VERSION 5.8 ;
BUSBITCHARS "[]" ;
DIVIDERCHAR "/" ;
UNITS
    DATABASE MICRONS 1000 ;
END UNITS

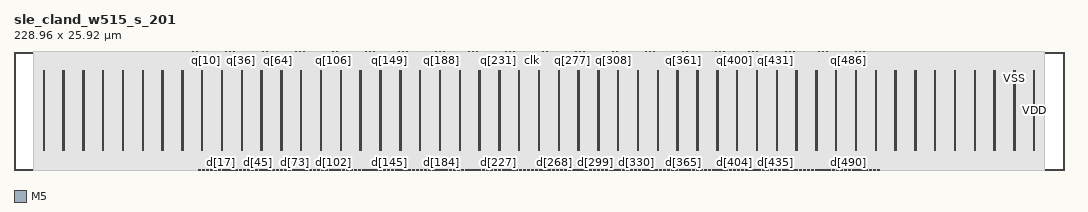
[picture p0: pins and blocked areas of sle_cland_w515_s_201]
MACRO sle_cland_w515_s_201
  FOREIGN sle_cland_w515_s_201 0 0 ;
  CLASS BLOCK ;
  SIZE 228.96 BY 25.92 ;
  PIN clk
    DIRECTION INPUT ;
    USE SIGNAL ;
    PORT
      LAYER M5 ;
        RECT  113.04 25.836 113.064 25.92 ;
    END
  END clk
  PIN d[0]
    DIRECTION INPUT ;
    USE SIGNAL ;
    PORT
      LAYER M5 ;
        RECT  40.176 0 40.2 0.084 ;
    END
  END d[0]
  PIN d[100]
    DIRECTION INPUT ;
    USE SIGNAL ;
    PORT
      LAYER M5 ;
        RECT  68.976 0 69 0.084 ;
    END
  END d[100]
  PIN d[101]
    DIRECTION INPUT ;
    USE SIGNAL ;
    PORT
      LAYER M5 ;
        RECT  69.264 0 69.288 0.084 ;
    END
  END d[101]
  PIN d[102]
    DIRECTION INPUT ;
    USE SIGNAL ;
    PORT
      LAYER M5 ;
        RECT  69.552 0 69.576 0.084 ;
    END
  END d[102]
  PIN d[103]
    DIRECTION INPUT ;
    USE SIGNAL ;
    PORT
      LAYER M5 ;
        RECT  69.84 0 69.864 0.084 ;
    END
  END d[103]
  PIN d[104]
    DIRECTION INPUT ;
    USE SIGNAL ;
    PORT
      LAYER M5 ;
        RECT  70.128 0 70.152 0.084 ;
    END
  END d[104]
  PIN d[105]
    DIRECTION INPUT ;
    USE SIGNAL ;
    PORT
      LAYER M5 ;
        RECT  70.416 0 70.44 0.084 ;
    END
  END d[105]
  PIN d[106]
    DIRECTION INPUT ;
    USE SIGNAL ;
    PORT
      LAYER M5 ;
        RECT  70.704 0 70.728 0.084 ;
    END
  END d[106]
  PIN d[107]
    DIRECTION INPUT ;
    USE SIGNAL ;
    PORT
      LAYER M5 ;
        RECT  70.992 0 71.016 0.084 ;
    END
  END d[107]
  PIN d[108]
    DIRECTION INPUT ;
    USE SIGNAL ;
    PORT
      LAYER M5 ;
        RECT  71.28 0 71.304 0.084 ;
    END
  END d[108]
  PIN d[109]
    DIRECTION INPUT ;
    USE SIGNAL ;
    PORT
      LAYER M5 ;
        RECT  71.568 0 71.592 0.084 ;
    END
  END d[109]
  PIN d[10]
    DIRECTION INPUT ;
    USE SIGNAL ;
    PORT
      LAYER M5 ;
        RECT  43.056 0 43.08 0.084 ;
    END
  END d[10]
  PIN d[110]
    DIRECTION INPUT ;
    USE SIGNAL ;
    PORT
      LAYER M5 ;
        RECT  71.856 0 71.88 0.084 ;
    END
  END d[110]
  PIN d[111]
    DIRECTION INPUT ;
    USE SIGNAL ;
    PORT
      LAYER M5 ;
        RECT  72.144 0 72.168 0.084 ;
    END
  END d[111]
  PIN d[112]
    DIRECTION INPUT ;
    USE SIGNAL ;
    PORT
      LAYER M5 ;
        RECT  72.432 0 72.456 0.084 ;
    END
  END d[112]
  PIN d[113]
    DIRECTION INPUT ;
    USE SIGNAL ;
    PORT
      LAYER M5 ;
        RECT  72.72 0 72.744 0.084 ;
    END
  END d[113]
  PIN d[114]
    DIRECTION INPUT ;
    USE SIGNAL ;
    PORT
      LAYER M5 ;
        RECT  73.008 0 73.032 0.084 ;
    END
  END d[114]
  PIN d[115]
    DIRECTION INPUT ;
    USE SIGNAL ;
    PORT
      LAYER M5 ;
        RECT  73.296 0 73.32 0.084 ;
    END
  END d[115]
  PIN d[116]
    DIRECTION INPUT ;
    USE SIGNAL ;
    PORT
      LAYER M5 ;
        RECT  73.584 0 73.608 0.084 ;
    END
  END d[116]
  PIN d[117]
    DIRECTION INPUT ;
    USE SIGNAL ;
    PORT
      LAYER M5 ;
        RECT  73.872 0 73.896 0.084 ;
    END
  END d[117]
  PIN d[118]
    DIRECTION INPUT ;
    USE SIGNAL ;
    PORT
      LAYER M5 ;
        RECT  74.16 0 74.184 0.084 ;
    END
  END d[118]
  PIN d[119]
    DIRECTION INPUT ;
    USE SIGNAL ;
    PORT
      LAYER M5 ;
        RECT  74.448 0 74.472 0.084 ;
    END
  END d[119]
  PIN d[11]
    DIRECTION INPUT ;
    USE SIGNAL ;
    PORT
      LAYER M5 ;
        RECT  43.344 0 43.368 0.084 ;
    END
  END d[11]
  PIN d[120]
    DIRECTION INPUT ;
    USE SIGNAL ;
    PORT
      LAYER M5 ;
        RECT  74.736 0 74.76 0.084 ;
    END
  END d[120]
  PIN d[121]
    DIRECTION INPUT ;
    USE SIGNAL ;
    PORT
      LAYER M5 ;
        RECT  75.024 0 75.048 0.084 ;
    END
  END d[121]
  PIN d[122]
    DIRECTION INPUT ;
    USE SIGNAL ;
    PORT
      LAYER M5 ;
        RECT  75.312 0 75.336 0.084 ;
    END
  END d[122]
  PIN d[123]
    DIRECTION INPUT ;
    USE SIGNAL ;
    PORT
      LAYER M5 ;
        RECT  75.6 0 75.624 0.084 ;
    END
  END d[123]
  PIN d[124]
    DIRECTION INPUT ;
    USE SIGNAL ;
    PORT
      LAYER M5 ;
        RECT  75.888 0 75.912 0.084 ;
    END
  END d[124]
  PIN d[125]
    DIRECTION INPUT ;
    USE SIGNAL ;
    PORT
      LAYER M5 ;
        RECT  76.176 0 76.2 0.084 ;
    END
  END d[125]
  PIN d[126]
    DIRECTION INPUT ;
    USE SIGNAL ;
    PORT
      LAYER M5 ;
        RECT  76.464 0 76.488 0.084 ;
    END
  END d[126]
  PIN d[127]
    DIRECTION INPUT ;
    USE SIGNAL ;
    PORT
      LAYER M5 ;
        RECT  76.752 0 76.776 0.084 ;
    END
  END d[127]
  PIN d[128]
    DIRECTION INPUT ;
    USE SIGNAL ;
    PORT
      LAYER M5 ;
        RECT  77.04 0 77.064 0.084 ;
    END
  END d[128]
  PIN d[129]
    DIRECTION INPUT ;
    USE SIGNAL ;
    PORT
      LAYER M5 ;
        RECT  77.328 0 77.352 0.084 ;
    END
  END d[129]
  PIN d[12]
    DIRECTION INPUT ;
    USE SIGNAL ;
    PORT
      LAYER M5 ;
        RECT  43.632 0 43.656 0.084 ;
    END
  END d[12]
  PIN d[130]
    DIRECTION INPUT ;
    USE SIGNAL ;
    PORT
      LAYER M5 ;
        RECT  77.616 0 77.64 0.084 ;
    END
  END d[130]
  PIN d[131]
    DIRECTION INPUT ;
    USE SIGNAL ;
    PORT
      LAYER M5 ;
        RECT  77.904 0 77.928 0.084 ;
    END
  END d[131]
  PIN d[132]
    DIRECTION INPUT ;
    USE SIGNAL ;
    PORT
      LAYER M5 ;
        RECT  78.192 0 78.216 0.084 ;
    END
  END d[132]
  PIN d[133]
    DIRECTION INPUT ;
    USE SIGNAL ;
    PORT
      LAYER M5 ;
        RECT  78.48 0 78.504 0.084 ;
    END
  END d[133]
  PIN d[134]
    DIRECTION INPUT ;
    USE SIGNAL ;
    PORT
      LAYER M5 ;
        RECT  78.768 0 78.792 0.084 ;
    END
  END d[134]
  PIN d[135]
    DIRECTION INPUT ;
    USE SIGNAL ;
    PORT
      LAYER M5 ;
        RECT  79.056 0 79.08 0.084 ;
    END
  END d[135]
  PIN d[136]
    DIRECTION INPUT ;
    USE SIGNAL ;
    PORT
      LAYER M5 ;
        RECT  79.344 0 79.368 0.084 ;
    END
  END d[136]
  PIN d[137]
    DIRECTION INPUT ;
    USE SIGNAL ;
    PORT
      LAYER M5 ;
        RECT  79.632 0 79.656 0.084 ;
    END
  END d[137]
  PIN d[138]
    DIRECTION INPUT ;
    USE SIGNAL ;
    PORT
      LAYER M5 ;
        RECT  79.92 0 79.944 0.084 ;
    END
  END d[138]
  PIN d[139]
    DIRECTION INPUT ;
    USE SIGNAL ;
    PORT
      LAYER M5 ;
        RECT  80.208 0 80.232 0.084 ;
    END
  END d[139]
  PIN d[13]
    DIRECTION INPUT ;
    USE SIGNAL ;
    PORT
      LAYER M5 ;
        RECT  43.92 0 43.944 0.084 ;
    END
  END d[13]
  PIN d[140]
    DIRECTION INPUT ;
    USE SIGNAL ;
    PORT
      LAYER M5 ;
        RECT  80.496 0 80.52 0.084 ;
    END
  END d[140]
  PIN d[141]
    DIRECTION INPUT ;
    USE SIGNAL ;
    PORT
      LAYER M5 ;
        RECT  80.784 0 80.808 0.084 ;
    END
  END d[141]
  PIN d[142]
    DIRECTION INPUT ;
    USE SIGNAL ;
    PORT
      LAYER M5 ;
        RECT  81.072 0 81.096 0.084 ;
    END
  END d[142]
  PIN d[143]
    DIRECTION INPUT ;
    USE SIGNAL ;
    PORT
      LAYER M5 ;
        RECT  81.36 0 81.384 0.084 ;
    END
  END d[143]
  PIN d[144]
    DIRECTION INPUT ;
    USE SIGNAL ;
    PORT
      LAYER M5 ;
        RECT  81.648 0 81.672 0.084 ;
    END
  END d[144]
  PIN d[145]
    DIRECTION INPUT ;
    USE SIGNAL ;
    PORT
      LAYER M5 ;
        RECT  81.936 0 81.96 0.084 ;
    END
  END d[145]
  PIN d[146]
    DIRECTION INPUT ;
    USE SIGNAL ;
    PORT
      LAYER M5 ;
        RECT  82.224 0 82.248 0.084 ;
    END
  END d[146]
  PIN d[147]
    DIRECTION INPUT ;
    USE SIGNAL ;
    PORT
      LAYER M5 ;
        RECT  82.512 0 82.536 0.084 ;
    END
  END d[147]
  PIN d[148]
    DIRECTION INPUT ;
    USE SIGNAL ;
    PORT
      LAYER M5 ;
        RECT  82.8 0 82.824 0.084 ;
    END
  END d[148]
  PIN d[149]
    DIRECTION INPUT ;
    USE SIGNAL ;
    PORT
      LAYER M5 ;
        RECT  83.088 0 83.112 0.084 ;
    END
  END d[149]
  PIN d[14]
    DIRECTION INPUT ;
    USE SIGNAL ;
    PORT
      LAYER M5 ;
        RECT  44.208 0 44.232 0.084 ;
    END
  END d[14]
  PIN d[150]
    DIRECTION INPUT ;
    USE SIGNAL ;
    PORT
      LAYER M5 ;
        RECT  83.376 0 83.4 0.084 ;
    END
  END d[150]
  PIN d[151]
    DIRECTION INPUT ;
    USE SIGNAL ;
    PORT
      LAYER M5 ;
        RECT  83.664 0 83.688 0.084 ;
    END
  END d[151]
  PIN d[152]
    DIRECTION INPUT ;
    USE SIGNAL ;
    PORT
      LAYER M5 ;
        RECT  83.952 0 83.976 0.084 ;
    END
  END d[152]
  PIN d[153]
    DIRECTION INPUT ;
    USE SIGNAL ;
    PORT
      LAYER M5 ;
        RECT  84.24 0 84.264 0.084 ;
    END
  END d[153]
  PIN d[154]
    DIRECTION INPUT ;
    USE SIGNAL ;
    PORT
      LAYER M5 ;
        RECT  84.528 0 84.552 0.084 ;
    END
  END d[154]
  PIN d[155]
    DIRECTION INPUT ;
    USE SIGNAL ;
    PORT
      LAYER M5 ;
        RECT  84.816 0 84.84 0.084 ;
    END
  END d[155]
  PIN d[156]
    DIRECTION INPUT ;
    USE SIGNAL ;
    PORT
      LAYER M5 ;
        RECT  85.104 0 85.128 0.084 ;
    END
  END d[156]
  PIN d[157]
    DIRECTION INPUT ;
    USE SIGNAL ;
    PORT
      LAYER M5 ;
        RECT  85.392 0 85.416 0.084 ;
    END
  END d[157]
  PIN d[158]
    DIRECTION INPUT ;
    USE SIGNAL ;
    PORT
      LAYER M5 ;
        RECT  85.68 0 85.704 0.084 ;
    END
  END d[158]
  PIN d[159]
    DIRECTION INPUT ;
    USE SIGNAL ;
    PORT
      LAYER M5 ;
        RECT  85.968 0 85.992 0.084 ;
    END
  END d[159]
  PIN d[15]
    DIRECTION INPUT ;
    USE SIGNAL ;
    PORT
      LAYER M5 ;
        RECT  44.496 0 44.52 0.084 ;
    END
  END d[15]
  PIN d[160]
    DIRECTION INPUT ;
    USE SIGNAL ;
    PORT
      LAYER M5 ;
        RECT  86.256 0 86.28 0.084 ;
    END
  END d[160]
  PIN d[161]
    DIRECTION INPUT ;
    USE SIGNAL ;
    PORT
      LAYER M5 ;
        RECT  86.544 0 86.568 0.084 ;
    END
  END d[161]
  PIN d[162]
    DIRECTION INPUT ;
    USE SIGNAL ;
    PORT
      LAYER M5 ;
        RECT  86.832 0 86.856 0.084 ;
    END
  END d[162]
  PIN d[163]
    DIRECTION INPUT ;
    USE SIGNAL ;
    PORT
      LAYER M5 ;
        RECT  87.12 0 87.144 0.084 ;
    END
  END d[163]
  PIN d[164]
    DIRECTION INPUT ;
    USE SIGNAL ;
    PORT
      LAYER M5 ;
        RECT  87.408 0 87.432 0.084 ;
    END
  END d[164]
  PIN d[165]
    DIRECTION INPUT ;
    USE SIGNAL ;
    PORT
      LAYER M5 ;
        RECT  87.696 0 87.72 0.084 ;
    END
  END d[165]
  PIN d[166]
    DIRECTION INPUT ;
    USE SIGNAL ;
    PORT
      LAYER M5 ;
        RECT  87.984 0 88.008 0.084 ;
    END
  END d[166]
  PIN d[167]
    DIRECTION INPUT ;
    USE SIGNAL ;
    PORT
      LAYER M5 ;
        RECT  88.272 0 88.296 0.084 ;
    END
  END d[167]
  PIN d[168]
    DIRECTION INPUT ;
    USE SIGNAL ;
    PORT
      LAYER M5 ;
        RECT  88.56 0 88.584 0.084 ;
    END
  END d[168]
  PIN d[169]
    DIRECTION INPUT ;
    USE SIGNAL ;
    PORT
      LAYER M5 ;
        RECT  88.848 0 88.872 0.084 ;
    END
  END d[169]
  PIN d[16]
    DIRECTION INPUT ;
    USE SIGNAL ;
    PORT
      LAYER M5 ;
        RECT  44.784 0 44.808 0.084 ;
    END
  END d[16]
  PIN d[170]
    DIRECTION INPUT ;
    USE SIGNAL ;
    PORT
      LAYER M5 ;
        RECT  89.136 0 89.16 0.084 ;
    END
  END d[170]
  PIN d[171]
    DIRECTION INPUT ;
    USE SIGNAL ;
    PORT
      LAYER M5 ;
        RECT  89.424 0 89.448 0.084 ;
    END
  END d[171]
  PIN d[172]
    DIRECTION INPUT ;
    USE SIGNAL ;
    PORT
      LAYER M5 ;
        RECT  89.712 0 89.736 0.084 ;
    END
  END d[172]
  PIN d[173]
    DIRECTION INPUT ;
    USE SIGNAL ;
    PORT
      LAYER M5 ;
        RECT  90 0 90.024 0.084 ;
    END
  END d[173]
  PIN d[174]
    DIRECTION INPUT ;
    USE SIGNAL ;
    PORT
      LAYER M5 ;
        RECT  90.288 0 90.312 0.084 ;
    END
  END d[174]
  PIN d[175]
    DIRECTION INPUT ;
    USE SIGNAL ;
    PORT
      LAYER M5 ;
        RECT  90.576 0 90.6 0.084 ;
    END
  END d[175]
  PIN d[176]
    DIRECTION INPUT ;
    USE SIGNAL ;
    PORT
      LAYER M5 ;
        RECT  90.864 0 90.888 0.084 ;
    END
  END d[176]
  PIN d[177]
    DIRECTION INPUT ;
    USE SIGNAL ;
    PORT
      LAYER M5 ;
        RECT  91.152 0 91.176 0.084 ;
    END
  END d[177]
  PIN d[178]
    DIRECTION INPUT ;
    USE SIGNAL ;
    PORT
      LAYER M5 ;
        RECT  91.44 0 91.464 0.084 ;
    END
  END d[178]
  PIN d[179]
    DIRECTION INPUT ;
    USE SIGNAL ;
    PORT
      LAYER M5 ;
        RECT  91.728 0 91.752 0.084 ;
    END
  END d[179]
  PIN d[17]
    DIRECTION INPUT ;
    USE SIGNAL ;
    PORT
      LAYER M5 ;
        RECT  45.072 0 45.096 0.084 ;
    END
  END d[17]
  PIN d[180]
    DIRECTION INPUT ;
    USE SIGNAL ;
    PORT
      LAYER M5 ;
        RECT  92.016 0 92.04 0.084 ;
    END
  END d[180]
  PIN d[181]
    DIRECTION INPUT ;
    USE SIGNAL ;
    PORT
      LAYER M5 ;
        RECT  92.304 0 92.328 0.084 ;
    END
  END d[181]
  PIN d[182]
    DIRECTION INPUT ;
    USE SIGNAL ;
    PORT
      LAYER M5 ;
        RECT  92.592 0 92.616 0.084 ;
    END
  END d[182]
  PIN d[183]
    DIRECTION INPUT ;
    USE SIGNAL ;
    PORT
      LAYER M5 ;
        RECT  92.88 0 92.904 0.084 ;
    END
  END d[183]
  PIN d[184]
    DIRECTION INPUT ;
    USE SIGNAL ;
    PORT
      LAYER M5 ;
        RECT  93.168 0 93.192 0.084 ;
    END
  END d[184]
  PIN d[185]
    DIRECTION INPUT ;
    USE SIGNAL ;
    PORT
      LAYER M5 ;
        RECT  93.456 0 93.48 0.084 ;
    END
  END d[185]
  PIN d[186]
    DIRECTION INPUT ;
    USE SIGNAL ;
    PORT
      LAYER M5 ;
        RECT  93.744 0 93.768 0.084 ;
    END
  END d[186]
  PIN d[187]
    DIRECTION INPUT ;
    USE SIGNAL ;
    PORT
      LAYER M5 ;
        RECT  94.032 0 94.056 0.084 ;
    END
  END d[187]
  PIN d[188]
    DIRECTION INPUT ;
    USE SIGNAL ;
    PORT
      LAYER M5 ;
        RECT  94.32 0 94.344 0.084 ;
    END
  END d[188]
  PIN d[189]
    DIRECTION INPUT ;
    USE SIGNAL ;
    PORT
      LAYER M5 ;
        RECT  94.608 0 94.632 0.084 ;
    END
  END d[189]
  PIN d[18]
    DIRECTION INPUT ;
    USE SIGNAL ;
    PORT
      LAYER M5 ;
        RECT  45.36 0 45.384 0.084 ;
    END
  END d[18]
  PIN d[190]
    DIRECTION INPUT ;
    USE SIGNAL ;
    PORT
      LAYER M5 ;
        RECT  94.896 0 94.92 0.084 ;
    END
  END d[190]
  PIN d[191]
    DIRECTION INPUT ;
    USE SIGNAL ;
    PORT
      LAYER M5 ;
        RECT  95.184 0 95.208 0.084 ;
    END
  END d[191]
  PIN d[192]
    DIRECTION INPUT ;
    USE SIGNAL ;
    PORT
      LAYER M5 ;
        RECT  95.472 0 95.496 0.084 ;
    END
  END d[192]
  PIN d[193]
    DIRECTION INPUT ;
    USE SIGNAL ;
    PORT
      LAYER M5 ;
        RECT  95.76 0 95.784 0.084 ;
    END
  END d[193]
  PIN d[194]
    DIRECTION INPUT ;
    USE SIGNAL ;
    PORT
      LAYER M5 ;
        RECT  96.048 0 96.072 0.084 ;
    END
  END d[194]
  PIN d[195]
    DIRECTION INPUT ;
    USE SIGNAL ;
    PORT
      LAYER M5 ;
        RECT  96.336 0 96.36 0.084 ;
    END
  END d[195]
  PIN d[196]
    DIRECTION INPUT ;
    USE SIGNAL ;
    PORT
      LAYER M5 ;
        RECT  96.624 0 96.648 0.084 ;
    END
  END d[196]
  PIN d[197]
    DIRECTION INPUT ;
    USE SIGNAL ;
    PORT
      LAYER M5 ;
        RECT  96.912 0 96.936 0.084 ;
    END
  END d[197]
  PIN d[198]
    DIRECTION INPUT ;
    USE SIGNAL ;
    PORT
      LAYER M5 ;
        RECT  97.2 0 97.224 0.084 ;
    END
  END d[198]
  PIN d[199]
    DIRECTION INPUT ;
    USE SIGNAL ;
    PORT
      LAYER M5 ;
        RECT  97.488 0 97.512 0.084 ;
    END
  END d[199]
  PIN d[19]
    DIRECTION INPUT ;
    USE SIGNAL ;
    PORT
      LAYER M5 ;
        RECT  45.648 0 45.672 0.084 ;
    END
  END d[19]
  PIN d[1]
    DIRECTION INPUT ;
    USE SIGNAL ;
    PORT
      LAYER M5 ;
        RECT  40.464 0 40.488 0.084 ;
    END
  END d[1]
  PIN d[200]
    DIRECTION INPUT ;
    USE SIGNAL ;
    PORT
      LAYER M5 ;
        RECT  97.776 0 97.8 0.084 ;
    END
  END d[200]
  PIN d[201]
    DIRECTION INPUT ;
    USE SIGNAL ;
    PORT
      LAYER M5 ;
        RECT  98.064 0 98.088 0.084 ;
    END
  END d[201]
  PIN d[202]
    DIRECTION INPUT ;
    USE SIGNAL ;
    PORT
      LAYER M5 ;
        RECT  98.352 0 98.376 0.084 ;
    END
  END d[202]
  PIN d[203]
    DIRECTION INPUT ;
    USE SIGNAL ;
    PORT
      LAYER M5 ;
        RECT  98.64 0 98.664 0.084 ;
    END
  END d[203]
  PIN d[204]
    DIRECTION INPUT ;
    USE SIGNAL ;
    PORT
      LAYER M5 ;
        RECT  98.928 0 98.952 0.084 ;
    END
  END d[204]
  PIN d[205]
    DIRECTION INPUT ;
    USE SIGNAL ;
    PORT
      LAYER M5 ;
        RECT  99.216 0 99.24 0.084 ;
    END
  END d[205]
  PIN d[206]
    DIRECTION INPUT ;
    USE SIGNAL ;
    PORT
      LAYER M5 ;
        RECT  99.504 0 99.528 0.084 ;
    END
  END d[206]
  PIN d[207]
    DIRECTION INPUT ;
    USE SIGNAL ;
    PORT
      LAYER M5 ;
        RECT  99.792 0 99.816 0.084 ;
    END
  END d[207]
  PIN d[208]
    DIRECTION INPUT ;
    USE SIGNAL ;
    PORT
      LAYER M5 ;
        RECT  100.08 0 100.104 0.084 ;
    END
  END d[208]
  PIN d[209]
    DIRECTION INPUT ;
    USE SIGNAL ;
    PORT
      LAYER M5 ;
        RECT  100.368 0 100.392 0.084 ;
    END
  END d[209]
  PIN d[20]
    DIRECTION INPUT ;
    USE SIGNAL ;
    PORT
      LAYER M5 ;
        RECT  45.936 0 45.96 0.084 ;
    END
  END d[20]
  PIN d[210]
    DIRECTION INPUT ;
    USE SIGNAL ;
    PORT
      LAYER M5 ;
        RECT  100.656 0 100.68 0.084 ;
    END
  END d[210]
  PIN d[211]
    DIRECTION INPUT ;
    USE SIGNAL ;
    PORT
      LAYER M5 ;
        RECT  100.944 0 100.968 0.084 ;
    END
  END d[211]
  PIN d[212]
    DIRECTION INPUT ;
    USE SIGNAL ;
    PORT
      LAYER M5 ;
        RECT  101.232 0 101.256 0.084 ;
    END
  END d[212]
  PIN d[213]
    DIRECTION INPUT ;
    USE SIGNAL ;
    PORT
      LAYER M5 ;
        RECT  101.52 0 101.544 0.084 ;
    END
  END d[213]
  PIN d[214]
    DIRECTION INPUT ;
    USE SIGNAL ;
    PORT
      LAYER M5 ;
        RECT  101.808 0 101.832 0.084 ;
    END
  END d[214]
  PIN d[215]
    DIRECTION INPUT ;
    USE SIGNAL ;
    PORT
      LAYER M5 ;
        RECT  102.096 0 102.12 0.084 ;
    END
  END d[215]
  PIN d[216]
    DIRECTION INPUT ;
    USE SIGNAL ;
    PORT
      LAYER M5 ;
        RECT  102.384 0 102.408 0.084 ;
    END
  END d[216]
  PIN d[217]
    DIRECTION INPUT ;
    USE SIGNAL ;
    PORT
      LAYER M5 ;
        RECT  102.672 0 102.696 0.084 ;
    END
  END d[217]
  PIN d[218]
    DIRECTION INPUT ;
    USE SIGNAL ;
    PORT
      LAYER M5 ;
        RECT  102.96 0 102.984 0.084 ;
    END
  END d[218]
  PIN d[219]
    DIRECTION INPUT ;
    USE SIGNAL ;
    PORT
      LAYER M5 ;
        RECT  103.248 0 103.272 0.084 ;
    END
  END d[219]
  PIN d[21]
    DIRECTION INPUT ;
    USE SIGNAL ;
    PORT
      LAYER M5 ;
        RECT  46.224 0 46.248 0.084 ;
    END
  END d[21]
  PIN d[220]
    DIRECTION INPUT ;
    USE SIGNAL ;
    PORT
      LAYER M5 ;
        RECT  103.536 0 103.56 0.084 ;
    END
  END d[220]
  PIN d[221]
    DIRECTION INPUT ;
    USE SIGNAL ;
    PORT
      LAYER M5 ;
        RECT  103.824 0 103.848 0.084 ;
    END
  END d[221]
  PIN d[222]
    DIRECTION INPUT ;
    USE SIGNAL ;
    PORT
      LAYER M5 ;
        RECT  104.112 0 104.136 0.084 ;
    END
  END d[222]
  PIN d[223]
    DIRECTION INPUT ;
    USE SIGNAL ;
    PORT
      LAYER M5 ;
        RECT  104.4 0 104.424 0.084 ;
    END
  END d[223]
  PIN d[224]
    DIRECTION INPUT ;
    USE SIGNAL ;
    PORT
      LAYER M5 ;
        RECT  104.688 0 104.712 0.084 ;
    END
  END d[224]
  PIN d[225]
    DIRECTION INPUT ;
    USE SIGNAL ;
    PORT
      LAYER M5 ;
        RECT  104.976 0 105 0.084 ;
    END
  END d[225]
  PIN d[226]
    DIRECTION INPUT ;
    USE SIGNAL ;
    PORT
      LAYER M5 ;
        RECT  105.264 0 105.288 0.084 ;
    END
  END d[226]
  PIN d[227]
    DIRECTION INPUT ;
    USE SIGNAL ;
    PORT
      LAYER M5 ;
        RECT  105.552 0 105.576 0.084 ;
    END
  END d[227]
  PIN d[228]
    DIRECTION INPUT ;
    USE SIGNAL ;
    PORT
      LAYER M5 ;
        RECT  105.84 0 105.864 0.084 ;
    END
  END d[228]
  PIN d[229]
    DIRECTION INPUT ;
    USE SIGNAL ;
    PORT
      LAYER M5 ;
        RECT  106.128 0 106.152 0.084 ;
    END
  END d[229]
  PIN d[22]
    DIRECTION INPUT ;
    USE SIGNAL ;
    PORT
      LAYER M5 ;
        RECT  46.512 0 46.536 0.084 ;
    END
  END d[22]
  PIN d[230]
    DIRECTION INPUT ;
    USE SIGNAL ;
    PORT
      LAYER M5 ;
        RECT  106.416 0 106.44 0.084 ;
    END
  END d[230]
  PIN d[231]
    DIRECTION INPUT ;
    USE SIGNAL ;
    PORT
      LAYER M5 ;
        RECT  106.704 0 106.728 0.084 ;
    END
  END d[231]
  PIN d[232]
    DIRECTION INPUT ;
    USE SIGNAL ;
    PORT
      LAYER M5 ;
        RECT  106.992 0 107.016 0.084 ;
    END
  END d[232]
  PIN d[233]
    DIRECTION INPUT ;
    USE SIGNAL ;
    PORT
      LAYER M5 ;
        RECT  107.28 0 107.304 0.084 ;
    END
  END d[233]
  PIN d[234]
    DIRECTION INPUT ;
    USE SIGNAL ;
    PORT
      LAYER M5 ;
        RECT  107.568 0 107.592 0.084 ;
    END
  END d[234]
  PIN d[235]
    DIRECTION INPUT ;
    USE SIGNAL ;
    PORT
      LAYER M5 ;
        RECT  107.856 0 107.88 0.084 ;
    END
  END d[235]
  PIN d[236]
    DIRECTION INPUT ;
    USE SIGNAL ;
    PORT
      LAYER M5 ;
        RECT  108.144 0 108.168 0.084 ;
    END
  END d[236]
  PIN d[237]
    DIRECTION INPUT ;
    USE SIGNAL ;
    PORT
      LAYER M5 ;
        RECT  108.432 0 108.456 0.084 ;
    END
  END d[237]
  PIN d[238]
    DIRECTION INPUT ;
    USE SIGNAL ;
    PORT
      LAYER M5 ;
        RECT  108.72 0 108.744 0.084 ;
    END
  END d[238]
  PIN d[239]
    DIRECTION INPUT ;
    USE SIGNAL ;
    PORT
      LAYER M5 ;
        RECT  109.008 0 109.032 0.084 ;
    END
  END d[239]
  PIN d[23]
    DIRECTION INPUT ;
    USE SIGNAL ;
    PORT
      LAYER M5 ;
        RECT  46.8 0 46.824 0.084 ;
    END
  END d[23]
  PIN d[240]
    DIRECTION INPUT ;
    USE SIGNAL ;
    PORT
      LAYER M5 ;
        RECT  109.296 0 109.32 0.084 ;
    END
  END d[240]
  PIN d[241]
    DIRECTION INPUT ;
    USE SIGNAL ;
    PORT
      LAYER M5 ;
        RECT  109.584 0 109.608 0.084 ;
    END
  END d[241]
  PIN d[242]
    DIRECTION INPUT ;
    USE SIGNAL ;
    PORT
      LAYER M5 ;
        RECT  109.872 0 109.896 0.084 ;
    END
  END d[242]
  PIN d[243]
    DIRECTION INPUT ;
    USE SIGNAL ;
    PORT
      LAYER M5 ;
        RECT  110.16 0 110.184 0.084 ;
    END
  END d[243]
  PIN d[244]
    DIRECTION INPUT ;
    USE SIGNAL ;
    PORT
      LAYER M5 ;
        RECT  110.448 0 110.472 0.084 ;
    END
  END d[244]
  PIN d[245]
    DIRECTION INPUT ;
    USE SIGNAL ;
    PORT
      LAYER M5 ;
        RECT  110.736 0 110.76 0.084 ;
    END
  END d[245]
  PIN d[246]
    DIRECTION INPUT ;
    USE SIGNAL ;
    PORT
      LAYER M5 ;
        RECT  111.024 0 111.048 0.084 ;
    END
  END d[246]
  PIN d[247]
    DIRECTION INPUT ;
    USE SIGNAL ;
    PORT
      LAYER M5 ;
        RECT  111.312 0 111.336 0.084 ;
    END
  END d[247]
  PIN d[248]
    DIRECTION INPUT ;
    USE SIGNAL ;
    PORT
      LAYER M5 ;
        RECT  111.6 0 111.624 0.084 ;
    END
  END d[248]
  PIN d[249]
    DIRECTION INPUT ;
    USE SIGNAL ;
    PORT
      LAYER M5 ;
        RECT  111.888 0 111.912 0.084 ;
    END
  END d[249]
  PIN d[24]
    DIRECTION INPUT ;
    USE SIGNAL ;
    PORT
      LAYER M5 ;
        RECT  47.088 0 47.112 0.084 ;
    END
  END d[24]
  PIN d[250]
    DIRECTION INPUT ;
    USE SIGNAL ;
    PORT
      LAYER M5 ;
        RECT  112.176 0 112.2 0.084 ;
    END
  END d[250]
  PIN d[251]
    DIRECTION INPUT ;
    USE SIGNAL ;
    PORT
      LAYER M5 ;
        RECT  112.464 0 112.488 0.084 ;
    END
  END d[251]
  PIN d[252]
    DIRECTION INPUT ;
    USE SIGNAL ;
    PORT
      LAYER M5 ;
        RECT  112.752 0 112.776 0.084 ;
    END
  END d[252]
  PIN d[253]
    DIRECTION INPUT ;
    USE SIGNAL ;
    PORT
      LAYER M5 ;
        RECT  113.04 0 113.064 0.084 ;
    END
  END d[253]
  PIN d[254]
    DIRECTION INPUT ;
    USE SIGNAL ;
    PORT
      LAYER M5 ;
        RECT  113.328 0 113.352 0.084 ;
    END
  END d[254]
  PIN d[255]
    DIRECTION INPUT ;
    USE SIGNAL ;
    PORT
      LAYER M5 ;
        RECT  113.616 0 113.64 0.084 ;
    END
  END d[255]
  PIN d[256]
    DIRECTION INPUT ;
    USE SIGNAL ;
    PORT
      LAYER M5 ;
        RECT  113.904 0 113.928 0.084 ;
    END
  END d[256]
  PIN d[257]
    DIRECTION INPUT ;
    USE SIGNAL ;
    PORT
      LAYER M5 ;
        RECT  114.768 0 114.792 0.084 ;
    END
  END d[257]
  PIN d[258]
    DIRECTION INPUT ;
    USE SIGNAL ;
    PORT
      LAYER M5 ;
        RECT  115.056 0 115.08 0.084 ;
    END
  END d[258]
  PIN d[259]
    DIRECTION INPUT ;
    USE SIGNAL ;
    PORT
      LAYER M5 ;
        RECT  115.344 0 115.368 0.084 ;
    END
  END d[259]
  PIN d[25]
    DIRECTION INPUT ;
    USE SIGNAL ;
    PORT
      LAYER M5 ;
        RECT  47.376 0 47.4 0.084 ;
    END
  END d[25]
  PIN d[260]
    DIRECTION INPUT ;
    USE SIGNAL ;
    PORT
      LAYER M5 ;
        RECT  115.632 0 115.656 0.084 ;
    END
  END d[260]
  PIN d[261]
    DIRECTION INPUT ;
    USE SIGNAL ;
    PORT
      LAYER M5 ;
        RECT  115.92 0 115.944 0.084 ;
    END
  END d[261]
  PIN d[262]
    DIRECTION INPUT ;
    USE SIGNAL ;
    PORT
      LAYER M5 ;
        RECT  116.208 0 116.232 0.084 ;
    END
  END d[262]
  PIN d[263]
    DIRECTION INPUT ;
    USE SIGNAL ;
    PORT
      LAYER M5 ;
        RECT  116.496 0 116.52 0.084 ;
    END
  END d[263]
  PIN d[264]
    DIRECTION INPUT ;
    USE SIGNAL ;
    PORT
      LAYER M5 ;
        RECT  116.784 0 116.808 0.084 ;
    END
  END d[264]
  PIN d[265]
    DIRECTION INPUT ;
    USE SIGNAL ;
    PORT
      LAYER M5 ;
        RECT  117.072 0 117.096 0.084 ;
    END
  END d[265]
  PIN d[266]
    DIRECTION INPUT ;
    USE SIGNAL ;
    PORT
      LAYER M5 ;
        RECT  117.36 0 117.384 0.084 ;
    END
  END d[266]
  PIN d[267]
    DIRECTION INPUT ;
    USE SIGNAL ;
    PORT
      LAYER M5 ;
        RECT  117.648 0 117.672 0.084 ;
    END
  END d[267]
  PIN d[268]
    DIRECTION INPUT ;
    USE SIGNAL ;
    PORT
      LAYER M5 ;
        RECT  117.936 0 117.96 0.084 ;
    END
  END d[268]
  PIN d[269]
    DIRECTION INPUT ;
    USE SIGNAL ;
    PORT
      LAYER M5 ;
        RECT  118.224 0 118.248 0.084 ;
    END
  END d[269]
  PIN d[26]
    DIRECTION INPUT ;
    USE SIGNAL ;
    PORT
      LAYER M5 ;
        RECT  47.664 0 47.688 0.084 ;
    END
  END d[26]
  PIN d[270]
    DIRECTION INPUT ;
    USE SIGNAL ;
    PORT
      LAYER M5 ;
        RECT  118.512 0 118.536 0.084 ;
    END
  END d[270]
  PIN d[271]
    DIRECTION INPUT ;
    USE SIGNAL ;
    PORT
      LAYER M5 ;
        RECT  118.8 0 118.824 0.084 ;
    END
  END d[271]
  PIN d[272]
    DIRECTION INPUT ;
    USE SIGNAL ;
    PORT
      LAYER M5 ;
        RECT  119.088 0 119.112 0.084 ;
    END
  END d[272]
  PIN d[273]
    DIRECTION INPUT ;
    USE SIGNAL ;
    PORT
      LAYER M5 ;
        RECT  119.376 0 119.4 0.084 ;
    END
  END d[273]
  PIN d[274]
    DIRECTION INPUT ;
    USE SIGNAL ;
    PORT
      LAYER M5 ;
        RECT  119.664 0 119.688 0.084 ;
    END
  END d[274]
  PIN d[275]
    DIRECTION INPUT ;
    USE SIGNAL ;
    PORT
      LAYER M5 ;
        RECT  119.952 0 119.976 0.084 ;
    END
  END d[275]
  PIN d[276]
    DIRECTION INPUT ;
    USE SIGNAL ;
    PORT
      LAYER M5 ;
        RECT  120.24 0 120.264 0.084 ;
    END
  END d[276]
  PIN d[277]
    DIRECTION INPUT ;
    USE SIGNAL ;
    PORT
      LAYER M5 ;
        RECT  120.528 0 120.552 0.084 ;
    END
  END d[277]
  PIN d[278]
    DIRECTION INPUT ;
    USE SIGNAL ;
    PORT
      LAYER M5 ;
        RECT  120.816 0 120.84 0.084 ;
    END
  END d[278]
  PIN d[279]
    DIRECTION INPUT ;
    USE SIGNAL ;
    PORT
      LAYER M5 ;
        RECT  121.104 0 121.128 0.084 ;
    END
  END d[279]
  PIN d[27]
    DIRECTION INPUT ;
    USE SIGNAL ;
    PORT
      LAYER M5 ;
        RECT  47.952 0 47.976 0.084 ;
    END
  END d[27]
  PIN d[280]
    DIRECTION INPUT ;
    USE SIGNAL ;
    PORT
      LAYER M5 ;
        RECT  121.392 0 121.416 0.084 ;
    END
  END d[280]
  PIN d[281]
    DIRECTION INPUT ;
    USE SIGNAL ;
    PORT
      LAYER M5 ;
        RECT  121.68 0 121.704 0.084 ;
    END
  END d[281]
  PIN d[282]
    DIRECTION INPUT ;
    USE SIGNAL ;
    PORT
      LAYER M5 ;
        RECT  121.968 0 121.992 0.084 ;
    END
  END d[282]
  PIN d[283]
    DIRECTION INPUT ;
    USE SIGNAL ;
    PORT
      LAYER M5 ;
        RECT  122.256 0 122.28 0.084 ;
    END
  END d[283]
  PIN d[284]
    DIRECTION INPUT ;
    USE SIGNAL ;
    PORT
      LAYER M5 ;
        RECT  122.544 0 122.568 0.084 ;
    END
  END d[284]
  PIN d[285]
    DIRECTION INPUT ;
    USE SIGNAL ;
    PORT
      LAYER M5 ;
        RECT  122.832 0 122.856 0.084 ;
    END
  END d[285]
  PIN d[286]
    DIRECTION INPUT ;
    USE SIGNAL ;
    PORT
      LAYER M5 ;
        RECT  123.12 0 123.144 0.084 ;
    END
  END d[286]
  PIN d[287]
    DIRECTION INPUT ;
    USE SIGNAL ;
    PORT
      LAYER M5 ;
        RECT  123.408 0 123.432 0.084 ;
    END
  END d[287]
  PIN d[288]
    DIRECTION INPUT ;
    USE SIGNAL ;
    PORT
      LAYER M5 ;
        RECT  123.696 0 123.72 0.084 ;
    END
  END d[288]
  PIN d[289]
    DIRECTION INPUT ;
    USE SIGNAL ;
    PORT
      LAYER M5 ;
        RECT  123.984 0 124.008 0.084 ;
    END
  END d[289]
  PIN d[28]
    DIRECTION INPUT ;
    USE SIGNAL ;
    PORT
      LAYER M5 ;
        RECT  48.24 0 48.264 0.084 ;
    END
  END d[28]
  PIN d[290]
    DIRECTION INPUT ;
    USE SIGNAL ;
    PORT
      LAYER M5 ;
        RECT  124.272 0 124.296 0.084 ;
    END
  END d[290]
  PIN d[291]
    DIRECTION INPUT ;
    USE SIGNAL ;
    PORT
      LAYER M5 ;
        RECT  124.56 0 124.584 0.084 ;
    END
  END d[291]
  PIN d[292]
    DIRECTION INPUT ;
    USE SIGNAL ;
    PORT
      LAYER M5 ;
        RECT  124.848 0 124.872 0.084 ;
    END
  END d[292]
  PIN d[293]
    DIRECTION INPUT ;
    USE SIGNAL ;
    PORT
      LAYER M5 ;
        RECT  125.136 0 125.16 0.084 ;
    END
  END d[293]
  PIN d[294]
    DIRECTION INPUT ;
    USE SIGNAL ;
    PORT
      LAYER M5 ;
        RECT  125.424 0 125.448 0.084 ;
    END
  END d[294]
  PIN d[295]
    DIRECTION INPUT ;
    USE SIGNAL ;
    PORT
      LAYER M5 ;
        RECT  125.712 0 125.736 0.084 ;
    END
  END d[295]
  PIN d[296]
    DIRECTION INPUT ;
    USE SIGNAL ;
    PORT
      LAYER M5 ;
        RECT  126 0 126.024 0.084 ;
    END
  END d[296]
  PIN d[297]
    DIRECTION INPUT ;
    USE SIGNAL ;
    PORT
      LAYER M5 ;
        RECT  126.288 0 126.312 0.084 ;
    END
  END d[297]
  PIN d[298]
    DIRECTION INPUT ;
    USE SIGNAL ;
    PORT
      LAYER M5 ;
        RECT  126.576 0 126.6 0.084 ;
    END
  END d[298]
  PIN d[299]
    DIRECTION INPUT ;
    USE SIGNAL ;
    PORT
      LAYER M5 ;
        RECT  126.864 0 126.888 0.084 ;
    END
  END d[299]
  PIN d[29]
    DIRECTION INPUT ;
    USE SIGNAL ;
    PORT
      LAYER M5 ;
        RECT  48.528 0 48.552 0.084 ;
    END
  END d[29]
  PIN d[2]
    DIRECTION INPUT ;
    USE SIGNAL ;
    PORT
      LAYER M5 ;
        RECT  40.752 0 40.776 0.084 ;
    END
  END d[2]
  PIN d[300]
    DIRECTION INPUT ;
    USE SIGNAL ;
    PORT
      LAYER M5 ;
        RECT  127.152 0 127.176 0.084 ;
    END
  END d[300]
  PIN d[301]
    DIRECTION INPUT ;
    USE SIGNAL ;
    PORT
      LAYER M5 ;
        RECT  127.44 0 127.464 0.084 ;
    END
  END d[301]
  PIN d[302]
    DIRECTION INPUT ;
    USE SIGNAL ;
    PORT
      LAYER M5 ;
        RECT  127.728 0 127.752 0.084 ;
    END
  END d[302]
  PIN d[303]
    DIRECTION INPUT ;
    USE SIGNAL ;
    PORT
      LAYER M5 ;
        RECT  128.016 0 128.04 0.084 ;
    END
  END d[303]
  PIN d[304]
    DIRECTION INPUT ;
    USE SIGNAL ;
    PORT
      LAYER M5 ;
        RECT  128.304 0 128.328 0.084 ;
    END
  END d[304]
  PIN d[305]
    DIRECTION INPUT ;
    USE SIGNAL ;
    PORT
      LAYER M5 ;
        RECT  128.592 0 128.616 0.084 ;
    END
  END d[305]
  PIN d[306]
    DIRECTION INPUT ;
    USE SIGNAL ;
    PORT
      LAYER M5 ;
        RECT  128.88 0 128.904 0.084 ;
    END
  END d[306]
  PIN d[307]
    DIRECTION INPUT ;
    USE SIGNAL ;
    PORT
      LAYER M5 ;
        RECT  129.168 0 129.192 0.084 ;
    END
  END d[307]
  PIN d[308]
    DIRECTION INPUT ;
    USE SIGNAL ;
    PORT
      LAYER M5 ;
        RECT  129.456 0 129.48 0.084 ;
    END
  END d[308]
  PIN d[309]
    DIRECTION INPUT ;
    USE SIGNAL ;
    PORT
      LAYER M5 ;
        RECT  129.744 0 129.768 0.084 ;
    END
  END d[309]
  PIN d[30]
    DIRECTION INPUT ;
    USE SIGNAL ;
    PORT
      LAYER M5 ;
        RECT  48.816 0 48.84 0.084 ;
    END
  END d[30]
  PIN d[310]
    DIRECTION INPUT ;
    USE SIGNAL ;
    PORT
      LAYER M5 ;
        RECT  130.032 0 130.056 0.084 ;
    END
  END d[310]
  PIN d[311]
    DIRECTION INPUT ;
    USE SIGNAL ;
    PORT
      LAYER M5 ;
        RECT  130.32 0 130.344 0.084 ;
    END
  END d[311]
  PIN d[312]
    DIRECTION INPUT ;
    USE SIGNAL ;
    PORT
      LAYER M5 ;
        RECT  130.608 0 130.632 0.084 ;
    END
  END d[312]
  PIN d[313]
    DIRECTION INPUT ;
    USE SIGNAL ;
    PORT
      LAYER M5 ;
        RECT  130.896 0 130.92 0.084 ;
    END
  END d[313]
  PIN d[314]
    DIRECTION INPUT ;
    USE SIGNAL ;
    PORT
      LAYER M5 ;
        RECT  131.184 0 131.208 0.084 ;
    END
  END d[314]
  PIN d[315]
    DIRECTION INPUT ;
    USE SIGNAL ;
    PORT
      LAYER M5 ;
        RECT  131.472 0 131.496 0.084 ;
    END
  END d[315]
  PIN d[316]
    DIRECTION INPUT ;
    USE SIGNAL ;
    PORT
      LAYER M5 ;
        RECT  131.76 0 131.784 0.084 ;
    END
  END d[316]
  PIN d[317]
    DIRECTION INPUT ;
    USE SIGNAL ;
    PORT
      LAYER M5 ;
        RECT  132.048 0 132.072 0.084 ;
    END
  END d[317]
  PIN d[318]
    DIRECTION INPUT ;
    USE SIGNAL ;
    PORT
      LAYER M5 ;
        RECT  132.336 0 132.36 0.084 ;
    END
  END d[318]
  PIN d[319]
    DIRECTION INPUT ;
    USE SIGNAL ;
    PORT
      LAYER M5 ;
        RECT  132.624 0 132.648 0.084 ;
    END
  END d[319]
  PIN d[31]
    DIRECTION INPUT ;
    USE SIGNAL ;
    PORT
      LAYER M5 ;
        RECT  49.104 0 49.128 0.084 ;
    END
  END d[31]
  PIN d[320]
    DIRECTION INPUT ;
    USE SIGNAL ;
    PORT
      LAYER M5 ;
        RECT  132.912 0 132.936 0.084 ;
    END
  END d[320]
  PIN d[321]
    DIRECTION INPUT ;
    USE SIGNAL ;
    PORT
      LAYER M5 ;
        RECT  133.2 0 133.224 0.084 ;
    END
  END d[321]
  PIN d[322]
    DIRECTION INPUT ;
    USE SIGNAL ;
    PORT
      LAYER M5 ;
        RECT  133.488 0 133.512 0.084 ;
    END
  END d[322]
  PIN d[323]
    DIRECTION INPUT ;
    USE SIGNAL ;
    PORT
      LAYER M5 ;
        RECT  133.776 0 133.8 0.084 ;
    END
  END d[323]
  PIN d[324]
    DIRECTION INPUT ;
    USE SIGNAL ;
    PORT
      LAYER M5 ;
        RECT  134.064 0 134.088 0.084 ;
    END
  END d[324]
  PIN d[325]
    DIRECTION INPUT ;
    USE SIGNAL ;
    PORT
      LAYER M5 ;
        RECT  134.352 0 134.376 0.084 ;
    END
  END d[325]
  PIN d[326]
    DIRECTION INPUT ;
    USE SIGNAL ;
    PORT
      LAYER M5 ;
        RECT  134.64 0 134.664 0.084 ;
    END
  END d[326]
  PIN d[327]
    DIRECTION INPUT ;
    USE SIGNAL ;
    PORT
      LAYER M5 ;
        RECT  134.928 0 134.952 0.084 ;
    END
  END d[327]
  PIN d[328]
    DIRECTION INPUT ;
    USE SIGNAL ;
    PORT
      LAYER M5 ;
        RECT  135.216 0 135.24 0.084 ;
    END
  END d[328]
  PIN d[329]
    DIRECTION INPUT ;
    USE SIGNAL ;
    PORT
      LAYER M5 ;
        RECT  135.504 0 135.528 0.084 ;
    END
  END d[329]
  PIN d[32]
    DIRECTION INPUT ;
    USE SIGNAL ;
    PORT
      LAYER M5 ;
        RECT  49.392 0 49.416 0.084 ;
    END
  END d[32]
  PIN d[330]
    DIRECTION INPUT ;
    USE SIGNAL ;
    PORT
      LAYER M5 ;
        RECT  135.792 0 135.816 0.084 ;
    END
  END d[330]
  PIN d[331]
    DIRECTION INPUT ;
    USE SIGNAL ;
    PORT
      LAYER M5 ;
        RECT  136.08 0 136.104 0.084 ;
    END
  END d[331]
  PIN d[332]
    DIRECTION INPUT ;
    USE SIGNAL ;
    PORT
      LAYER M5 ;
        RECT  136.368 0 136.392 0.084 ;
    END
  END d[332]
  PIN d[333]
    DIRECTION INPUT ;
    USE SIGNAL ;
    PORT
      LAYER M5 ;
        RECT  136.656 0 136.68 0.084 ;
    END
  END d[333]
  PIN d[334]
    DIRECTION INPUT ;
    USE SIGNAL ;
    PORT
      LAYER M5 ;
        RECT  136.944 0 136.968 0.084 ;
    END
  END d[334]
  PIN d[335]
    DIRECTION INPUT ;
    USE SIGNAL ;
    PORT
      LAYER M5 ;
        RECT  137.232 0 137.256 0.084 ;
    END
  END d[335]
  PIN d[336]
    DIRECTION INPUT ;
    USE SIGNAL ;
    PORT
      LAYER M5 ;
        RECT  137.52 0 137.544 0.084 ;
    END
  END d[336]
  PIN d[337]
    DIRECTION INPUT ;
    USE SIGNAL ;
    PORT
      LAYER M5 ;
        RECT  137.808 0 137.832 0.084 ;
    END
  END d[337]
  PIN d[338]
    DIRECTION INPUT ;
    USE SIGNAL ;
    PORT
      LAYER M5 ;
        RECT  138.096 0 138.12 0.084 ;
    END
  END d[338]
  PIN d[339]
    DIRECTION INPUT ;
    USE SIGNAL ;
    PORT
      LAYER M5 ;
        RECT  138.384 0 138.408 0.084 ;
    END
  END d[339]
  PIN d[33]
    DIRECTION INPUT ;
    USE SIGNAL ;
    PORT
      LAYER M5 ;
        RECT  49.68 0 49.704 0.084 ;
    END
  END d[33]
  PIN d[340]
    DIRECTION INPUT ;
    USE SIGNAL ;
    PORT
      LAYER M5 ;
        RECT  138.672 0 138.696 0.084 ;
    END
  END d[340]
  PIN d[341]
    DIRECTION INPUT ;
    USE SIGNAL ;
    PORT
      LAYER M5 ;
        RECT  138.96 0 138.984 0.084 ;
    END
  END d[341]
  PIN d[342]
    DIRECTION INPUT ;
    USE SIGNAL ;
    PORT
      LAYER M5 ;
        RECT  139.248 0 139.272 0.084 ;
    END
  END d[342]
  PIN d[343]
    DIRECTION INPUT ;
    USE SIGNAL ;
    PORT
      LAYER M5 ;
        RECT  139.536 0 139.56 0.084 ;
    END
  END d[343]
  PIN d[344]
    DIRECTION INPUT ;
    USE SIGNAL ;
    PORT
      LAYER M5 ;
        RECT  139.824 0 139.848 0.084 ;
    END
  END d[344]
  PIN d[345]
    DIRECTION INPUT ;
    USE SIGNAL ;
    PORT
      LAYER M5 ;
        RECT  140.112 0 140.136 0.084 ;
    END
  END d[345]
  PIN d[346]
    DIRECTION INPUT ;
    USE SIGNAL ;
    PORT
      LAYER M5 ;
        RECT  140.4 0 140.424 0.084 ;
    END
  END d[346]
  PIN d[347]
    DIRECTION INPUT ;
    USE SIGNAL ;
    PORT
      LAYER M5 ;
        RECT  140.688 0 140.712 0.084 ;
    END
  END d[347]
  PIN d[348]
    DIRECTION INPUT ;
    USE SIGNAL ;
    PORT
      LAYER M5 ;
        RECT  140.976 0 141 0.084 ;
    END
  END d[348]
  PIN d[349]
    DIRECTION INPUT ;
    USE SIGNAL ;
    PORT
      LAYER M5 ;
        RECT  141.264 0 141.288 0.084 ;
    END
  END d[349]
  PIN d[34]
    DIRECTION INPUT ;
    USE SIGNAL ;
    PORT
      LAYER M5 ;
        RECT  49.968 0 49.992 0.084 ;
    END
  END d[34]
  PIN d[350]
    DIRECTION INPUT ;
    USE SIGNAL ;
    PORT
      LAYER M5 ;
        RECT  141.552 0 141.576 0.084 ;
    END
  END d[350]
  PIN d[351]
    DIRECTION INPUT ;
    USE SIGNAL ;
    PORT
      LAYER M5 ;
        RECT  141.84 0 141.864 0.084 ;
    END
  END d[351]
  PIN d[352]
    DIRECTION INPUT ;
    USE SIGNAL ;
    PORT
      LAYER M5 ;
        RECT  142.128 0 142.152 0.084 ;
    END
  END d[352]
  PIN d[353]
    DIRECTION INPUT ;
    USE SIGNAL ;
    PORT
      LAYER M5 ;
        RECT  142.416 0 142.44 0.084 ;
    END
  END d[353]
  PIN d[354]
    DIRECTION INPUT ;
    USE SIGNAL ;
    PORT
      LAYER M5 ;
        RECT  142.704 0 142.728 0.084 ;
    END
  END d[354]
  PIN d[355]
    DIRECTION INPUT ;
    USE SIGNAL ;
    PORT
      LAYER M5 ;
        RECT  142.992 0 143.016 0.084 ;
    END
  END d[355]
  PIN d[356]
    DIRECTION INPUT ;
    USE SIGNAL ;
    PORT
      LAYER M5 ;
        RECT  143.28 0 143.304 0.084 ;
    END
  END d[356]
  PIN d[357]
    DIRECTION INPUT ;
    USE SIGNAL ;
    PORT
      LAYER M5 ;
        RECT  143.568 0 143.592 0.084 ;
    END
  END d[357]
  PIN d[358]
    DIRECTION INPUT ;
    USE SIGNAL ;
    PORT
      LAYER M5 ;
        RECT  143.856 0 143.88 0.084 ;
    END
  END d[358]
  PIN d[359]
    DIRECTION INPUT ;
    USE SIGNAL ;
    PORT
      LAYER M5 ;
        RECT  144.144 0 144.168 0.084 ;
    END
  END d[359]
  PIN d[35]
    DIRECTION INPUT ;
    USE SIGNAL ;
    PORT
      LAYER M5 ;
        RECT  50.256 0 50.28 0.084 ;
    END
  END d[35]
  PIN d[360]
    DIRECTION INPUT ;
    USE SIGNAL ;
    PORT
      LAYER M5 ;
        RECT  144.432 0 144.456 0.084 ;
    END
  END d[360]
  PIN d[361]
    DIRECTION INPUT ;
    USE SIGNAL ;
    PORT
      LAYER M5 ;
        RECT  144.72 0 144.744 0.084 ;
    END
  END d[361]
  PIN d[362]
    DIRECTION INPUT ;
    USE SIGNAL ;
    PORT
      LAYER M5 ;
        RECT  145.008 0 145.032 0.084 ;
    END
  END d[362]
  PIN d[363]
    DIRECTION INPUT ;
    USE SIGNAL ;
    PORT
      LAYER M5 ;
        RECT  145.296 0 145.32 0.084 ;
    END
  END d[363]
  PIN d[364]
    DIRECTION INPUT ;
    USE SIGNAL ;
    PORT
      LAYER M5 ;
        RECT  145.584 0 145.608 0.084 ;
    END
  END d[364]
  PIN d[365]
    DIRECTION INPUT ;
    USE SIGNAL ;
    PORT
      LAYER M5 ;
        RECT  145.872 0 145.896 0.084 ;
    END
  END d[365]
  PIN d[366]
    DIRECTION INPUT ;
    USE SIGNAL ;
    PORT
      LAYER M5 ;
        RECT  146.16 0 146.184 0.084 ;
    END
  END d[366]
  PIN d[367]
    DIRECTION INPUT ;
    USE SIGNAL ;
    PORT
      LAYER M5 ;
        RECT  146.448 0 146.472 0.084 ;
    END
  END d[367]
  PIN d[368]
    DIRECTION INPUT ;
    USE SIGNAL ;
    PORT
      LAYER M5 ;
        RECT  146.736 0 146.76 0.084 ;
    END
  END d[368]
  PIN d[369]
    DIRECTION INPUT ;
    USE SIGNAL ;
    PORT
      LAYER M5 ;
        RECT  147.024 0 147.048 0.084 ;
    END
  END d[369]
  PIN d[36]
    DIRECTION INPUT ;
    USE SIGNAL ;
    PORT
      LAYER M5 ;
        RECT  50.544 0 50.568 0.084 ;
    END
  END d[36]
  PIN d[370]
    DIRECTION INPUT ;
    USE SIGNAL ;
    PORT
      LAYER M5 ;
        RECT  147.312 0 147.336 0.084 ;
    END
  END d[370]
  PIN d[371]
    DIRECTION INPUT ;
    USE SIGNAL ;
    PORT
      LAYER M5 ;
        RECT  147.6 0 147.624 0.084 ;
    END
  END d[371]
  PIN d[372]
    DIRECTION INPUT ;
    USE SIGNAL ;
    PORT
      LAYER M5 ;
        RECT  147.888 0 147.912 0.084 ;
    END
  END d[372]
  PIN d[373]
    DIRECTION INPUT ;
    USE SIGNAL ;
    PORT
      LAYER M5 ;
        RECT  148.176 0 148.2 0.084 ;
    END
  END d[373]
  PIN d[374]
    DIRECTION INPUT ;
    USE SIGNAL ;
    PORT
      LAYER M5 ;
        RECT  148.464 0 148.488 0.084 ;
    END
  END d[374]
  PIN d[375]
    DIRECTION INPUT ;
    USE SIGNAL ;
    PORT
      LAYER M5 ;
        RECT  148.752 0 148.776 0.084 ;
    END
  END d[375]
  PIN d[376]
    DIRECTION INPUT ;
    USE SIGNAL ;
    PORT
      LAYER M5 ;
        RECT  149.04 0 149.064 0.084 ;
    END
  END d[376]
  PIN d[377]
    DIRECTION INPUT ;
    USE SIGNAL ;
    PORT
      LAYER M5 ;
        RECT  149.328 0 149.352 0.084 ;
    END
  END d[377]
  PIN d[378]
    DIRECTION INPUT ;
    USE SIGNAL ;
    PORT
      LAYER M5 ;
        RECT  149.616 0 149.64 0.084 ;
    END
  END d[378]
  PIN d[379]
    DIRECTION INPUT ;
    USE SIGNAL ;
    PORT
      LAYER M5 ;
        RECT  149.904 0 149.928 0.084 ;
    END
  END d[379]
  PIN d[37]
    DIRECTION INPUT ;
    USE SIGNAL ;
    PORT
      LAYER M5 ;
        RECT  50.832 0 50.856 0.084 ;
    END
  END d[37]
  PIN d[380]
    DIRECTION INPUT ;
    USE SIGNAL ;
    PORT
      LAYER M5 ;
        RECT  150.192 0 150.216 0.084 ;
    END
  END d[380]
  PIN d[381]
    DIRECTION INPUT ;
    USE SIGNAL ;
    PORT
      LAYER M5 ;
        RECT  150.48 0 150.504 0.084 ;
    END
  END d[381]
  PIN d[382]
    DIRECTION INPUT ;
    USE SIGNAL ;
    PORT
      LAYER M5 ;
        RECT  150.768 0 150.792 0.084 ;
    END
  END d[382]
  PIN d[383]
    DIRECTION INPUT ;
    USE SIGNAL ;
    PORT
      LAYER M5 ;
        RECT  151.056 0 151.08 0.084 ;
    END
  END d[383]
  PIN d[384]
    DIRECTION INPUT ;
    USE SIGNAL ;
    PORT
      LAYER M5 ;
        RECT  151.344 0 151.368 0.084 ;
    END
  END d[384]
  PIN d[385]
    DIRECTION INPUT ;
    USE SIGNAL ;
    PORT
      LAYER M5 ;
        RECT  151.632 0 151.656 0.084 ;
    END
  END d[385]
  PIN d[386]
    DIRECTION INPUT ;
    USE SIGNAL ;
    PORT
      LAYER M5 ;
        RECT  151.92 0 151.944 0.084 ;
    END
  END d[386]
  PIN d[387]
    DIRECTION INPUT ;
    USE SIGNAL ;
    PORT
      LAYER M5 ;
        RECT  152.208 0 152.232 0.084 ;
    END
  END d[387]
  PIN d[388]
    DIRECTION INPUT ;
    USE SIGNAL ;
    PORT
      LAYER M5 ;
        RECT  152.496 0 152.52 0.084 ;
    END
  END d[388]
  PIN d[389]
    DIRECTION INPUT ;
    USE SIGNAL ;
    PORT
      LAYER M5 ;
        RECT  152.784 0 152.808 0.084 ;
    END
  END d[389]
  PIN d[38]
    DIRECTION INPUT ;
    USE SIGNAL ;
    PORT
      LAYER M5 ;
        RECT  51.12 0 51.144 0.084 ;
    END
  END d[38]
  PIN d[390]
    DIRECTION INPUT ;
    USE SIGNAL ;
    PORT
      LAYER M5 ;
        RECT  153.072 0 153.096 0.084 ;
    END
  END d[390]
  PIN d[391]
    DIRECTION INPUT ;
    USE SIGNAL ;
    PORT
      LAYER M5 ;
        RECT  153.36 0 153.384 0.084 ;
    END
  END d[391]
  PIN d[392]
    DIRECTION INPUT ;
    USE SIGNAL ;
    PORT
      LAYER M5 ;
        RECT  153.648 0 153.672 0.084 ;
    END
  END d[392]
  PIN d[393]
    DIRECTION INPUT ;
    USE SIGNAL ;
    PORT
      LAYER M5 ;
        RECT  153.936 0 153.96 0.084 ;
    END
  END d[393]
  PIN d[394]
    DIRECTION INPUT ;
    USE SIGNAL ;
    PORT
      LAYER M5 ;
        RECT  154.224 0 154.248 0.084 ;
    END
  END d[394]
  PIN d[395]
    DIRECTION INPUT ;
    USE SIGNAL ;
    PORT
      LAYER M5 ;
        RECT  154.512 0 154.536 0.084 ;
    END
  END d[395]
  PIN d[396]
    DIRECTION INPUT ;
    USE SIGNAL ;
    PORT
      LAYER M5 ;
        RECT  154.8 0 154.824 0.084 ;
    END
  END d[396]
  PIN d[397]
    DIRECTION INPUT ;
    USE SIGNAL ;
    PORT
      LAYER M5 ;
        RECT  155.088 0 155.112 0.084 ;
    END
  END d[397]
  PIN d[398]
    DIRECTION INPUT ;
    USE SIGNAL ;
    PORT
      LAYER M5 ;
        RECT  155.376 0 155.4 0.084 ;
    END
  END d[398]
  PIN d[399]
    DIRECTION INPUT ;
    USE SIGNAL ;
    PORT
      LAYER M5 ;
        RECT  155.664 0 155.688 0.084 ;
    END
  END d[399]
  PIN d[39]
    DIRECTION INPUT ;
    USE SIGNAL ;
    PORT
      LAYER M5 ;
        RECT  51.408 0 51.432 0.084 ;
    END
  END d[39]
  PIN d[3]
    DIRECTION INPUT ;
    USE SIGNAL ;
    PORT
      LAYER M5 ;
        RECT  41.04 0 41.064 0.084 ;
    END
  END d[3]
  PIN d[400]
    DIRECTION INPUT ;
    USE SIGNAL ;
    PORT
      LAYER M5 ;
        RECT  155.952 0 155.976 0.084 ;
    END
  END d[400]
  PIN d[401]
    DIRECTION INPUT ;
    USE SIGNAL ;
    PORT
      LAYER M5 ;
        RECT  156.24 0 156.264 0.084 ;
    END
  END d[401]
  PIN d[402]
    DIRECTION INPUT ;
    USE SIGNAL ;
    PORT
      LAYER M5 ;
        RECT  156.528 0 156.552 0.084 ;
    END
  END d[402]
  PIN d[403]
    DIRECTION INPUT ;
    USE SIGNAL ;
    PORT
      LAYER M5 ;
        RECT  156.816 0 156.84 0.084 ;
    END
  END d[403]
  PIN d[404]
    DIRECTION INPUT ;
    USE SIGNAL ;
    PORT
      LAYER M5 ;
        RECT  157.104 0 157.128 0.084 ;
    END
  END d[404]
  PIN d[405]
    DIRECTION INPUT ;
    USE SIGNAL ;
    PORT
      LAYER M5 ;
        RECT  157.392 0 157.416 0.084 ;
    END
  END d[405]
  PIN d[406]
    DIRECTION INPUT ;
    USE SIGNAL ;
    PORT
      LAYER M5 ;
        RECT  157.68 0 157.704 0.084 ;
    END
  END d[406]
  PIN d[407]
    DIRECTION INPUT ;
    USE SIGNAL ;
    PORT
      LAYER M5 ;
        RECT  157.968 0 157.992 0.084 ;
    END
  END d[407]
  PIN d[408]
    DIRECTION INPUT ;
    USE SIGNAL ;
    PORT
      LAYER M5 ;
        RECT  158.256 0 158.28 0.084 ;
    END
  END d[408]
  PIN d[409]
    DIRECTION INPUT ;
    USE SIGNAL ;
    PORT
      LAYER M5 ;
        RECT  158.544 0 158.568 0.084 ;
    END
  END d[409]
  PIN d[40]
    DIRECTION INPUT ;
    USE SIGNAL ;
    PORT
      LAYER M5 ;
        RECT  51.696 0 51.72 0.084 ;
    END
  END d[40]
  PIN d[410]
    DIRECTION INPUT ;
    USE SIGNAL ;
    PORT
      LAYER M5 ;
        RECT  158.832 0 158.856 0.084 ;
    END
  END d[410]
  PIN d[411]
    DIRECTION INPUT ;
    USE SIGNAL ;
    PORT
      LAYER M5 ;
        RECT  159.12 0 159.144 0.084 ;
    END
  END d[411]
  PIN d[412]
    DIRECTION INPUT ;
    USE SIGNAL ;
    PORT
      LAYER M5 ;
        RECT  159.408 0 159.432 0.084 ;
    END
  END d[412]
  PIN d[413]
    DIRECTION INPUT ;
    USE SIGNAL ;
    PORT
      LAYER M5 ;
        RECT  159.696 0 159.72 0.084 ;
    END
  END d[413]
  PIN d[414]
    DIRECTION INPUT ;
    USE SIGNAL ;
    PORT
      LAYER M5 ;
        RECT  159.984 0 160.008 0.084 ;
    END
  END d[414]
  PIN d[415]
    DIRECTION INPUT ;
    USE SIGNAL ;
    PORT
      LAYER M5 ;
        RECT  160.272 0 160.296 0.084 ;
    END
  END d[415]
  PIN d[416]
    DIRECTION INPUT ;
    USE SIGNAL ;
    PORT
      LAYER M5 ;
        RECT  160.56 0 160.584 0.084 ;
    END
  END d[416]
  PIN d[417]
    DIRECTION INPUT ;
    USE SIGNAL ;
    PORT
      LAYER M5 ;
        RECT  160.848 0 160.872 0.084 ;
    END
  END d[417]
  PIN d[418]
    DIRECTION INPUT ;
    USE SIGNAL ;
    PORT
      LAYER M5 ;
        RECT  161.136 0 161.16 0.084 ;
    END
  END d[418]
  PIN d[419]
    DIRECTION INPUT ;
    USE SIGNAL ;
    PORT
      LAYER M5 ;
        RECT  161.424 0 161.448 0.084 ;
    END
  END d[419]
  PIN d[41]
    DIRECTION INPUT ;
    USE SIGNAL ;
    PORT
      LAYER M5 ;
        RECT  51.984 0 52.008 0.084 ;
    END
  END d[41]
  PIN d[420]
    DIRECTION INPUT ;
    USE SIGNAL ;
    PORT
      LAYER M5 ;
        RECT  161.712 0 161.736 0.084 ;
    END
  END d[420]
  PIN d[421]
    DIRECTION INPUT ;
    USE SIGNAL ;
    PORT
      LAYER M5 ;
        RECT  162 0 162.024 0.084 ;
    END
  END d[421]
  PIN d[422]
    DIRECTION INPUT ;
    USE SIGNAL ;
    PORT
      LAYER M5 ;
        RECT  162.288 0 162.312 0.084 ;
    END
  END d[422]
  PIN d[423]
    DIRECTION INPUT ;
    USE SIGNAL ;
    PORT
      LAYER M5 ;
        RECT  162.576 0 162.6 0.084 ;
    END
  END d[423]
  PIN d[424]
    DIRECTION INPUT ;
    USE SIGNAL ;
    PORT
      LAYER M5 ;
        RECT  162.864 0 162.888 0.084 ;
    END
  END d[424]
  PIN d[425]
    DIRECTION INPUT ;
    USE SIGNAL ;
    PORT
      LAYER M5 ;
        RECT  163.152 0 163.176 0.084 ;
    END
  END d[425]
  PIN d[426]
    DIRECTION INPUT ;
    USE SIGNAL ;
    PORT
      LAYER M5 ;
        RECT  163.44 0 163.464 0.084 ;
    END
  END d[426]
  PIN d[427]
    DIRECTION INPUT ;
    USE SIGNAL ;
    PORT
      LAYER M5 ;
        RECT  163.728 0 163.752 0.084 ;
    END
  END d[427]
  PIN d[428]
    DIRECTION INPUT ;
    USE SIGNAL ;
    PORT
      LAYER M5 ;
        RECT  164.016 0 164.04 0.084 ;
    END
  END d[428]
  PIN d[429]
    DIRECTION INPUT ;
    USE SIGNAL ;
    PORT
      LAYER M5 ;
        RECT  164.304 0 164.328 0.084 ;
    END
  END d[429]
  PIN d[42]
    DIRECTION INPUT ;
    USE SIGNAL ;
    PORT
      LAYER M5 ;
        RECT  52.272 0 52.296 0.084 ;
    END
  END d[42]
  PIN d[430]
    DIRECTION INPUT ;
    USE SIGNAL ;
    PORT
      LAYER M5 ;
        RECT  164.592 0 164.616 0.084 ;
    END
  END d[430]
  PIN d[431]
    DIRECTION INPUT ;
    USE SIGNAL ;
    PORT
      LAYER M5 ;
        RECT  164.88 0 164.904 0.084 ;
    END
  END d[431]
  PIN d[432]
    DIRECTION INPUT ;
    USE SIGNAL ;
    PORT
      LAYER M5 ;
        RECT  165.168 0 165.192 0.084 ;
    END
  END d[432]
  PIN d[433]
    DIRECTION INPUT ;
    USE SIGNAL ;
    PORT
      LAYER M5 ;
        RECT  165.456 0 165.48 0.084 ;
    END
  END d[433]
  PIN d[434]
    DIRECTION INPUT ;
    USE SIGNAL ;
    PORT
      LAYER M5 ;
        RECT  165.744 0 165.768 0.084 ;
    END
  END d[434]
  PIN d[435]
    DIRECTION INPUT ;
    USE SIGNAL ;
    PORT
      LAYER M5 ;
        RECT  166.032 0 166.056 0.084 ;
    END
  END d[435]
  PIN d[436]
    DIRECTION INPUT ;
    USE SIGNAL ;
    PORT
      LAYER M5 ;
        RECT  166.32 0 166.344 0.084 ;
    END
  END d[436]
  PIN d[437]
    DIRECTION INPUT ;
    USE SIGNAL ;
    PORT
      LAYER M5 ;
        RECT  166.608 0 166.632 0.084 ;
    END
  END d[437]
  PIN d[438]
    DIRECTION INPUT ;
    USE SIGNAL ;
    PORT
      LAYER M5 ;
        RECT  166.896 0 166.92 0.084 ;
    END
  END d[438]
  PIN d[439]
    DIRECTION INPUT ;
    USE SIGNAL ;
    PORT
      LAYER M5 ;
        RECT  167.184 0 167.208 0.084 ;
    END
  END d[439]
  PIN d[43]
    DIRECTION INPUT ;
    USE SIGNAL ;
    PORT
      LAYER M5 ;
        RECT  52.56 0 52.584 0.084 ;
    END
  END d[43]
  PIN d[440]
    DIRECTION INPUT ;
    USE SIGNAL ;
    PORT
      LAYER M5 ;
        RECT  167.472 0 167.496 0.084 ;
    END
  END d[440]
  PIN d[441]
    DIRECTION INPUT ;
    USE SIGNAL ;
    PORT
      LAYER M5 ;
        RECT  167.76 0 167.784 0.084 ;
    END
  END d[441]
  PIN d[442]
    DIRECTION INPUT ;
    USE SIGNAL ;
    PORT
      LAYER M5 ;
        RECT  168.048 0 168.072 0.084 ;
    END
  END d[442]
  PIN d[443]
    DIRECTION INPUT ;
    USE SIGNAL ;
    PORT
      LAYER M5 ;
        RECT  168.336 0 168.36 0.084 ;
    END
  END d[443]
  PIN d[444]
    DIRECTION INPUT ;
    USE SIGNAL ;
    PORT
      LAYER M5 ;
        RECT  168.624 0 168.648 0.084 ;
    END
  END d[444]
  PIN d[445]
    DIRECTION INPUT ;
    USE SIGNAL ;
    PORT
      LAYER M5 ;
        RECT  168.912 0 168.936 0.084 ;
    END
  END d[445]
  PIN d[446]
    DIRECTION INPUT ;
    USE SIGNAL ;
    PORT
      LAYER M5 ;
        RECT  169.2 0 169.224 0.084 ;
    END
  END d[446]
  PIN d[447]
    DIRECTION INPUT ;
    USE SIGNAL ;
    PORT
      LAYER M5 ;
        RECT  169.488 0 169.512 0.084 ;
    END
  END d[447]
  PIN d[448]
    DIRECTION INPUT ;
    USE SIGNAL ;
    PORT
      LAYER M5 ;
        RECT  169.776 0 169.8 0.084 ;
    END
  END d[448]
  PIN d[449]
    DIRECTION INPUT ;
    USE SIGNAL ;
    PORT
      LAYER M5 ;
        RECT  170.064 0 170.088 0.084 ;
    END
  END d[449]
  PIN d[44]
    DIRECTION INPUT ;
    USE SIGNAL ;
    PORT
      LAYER M5 ;
        RECT  52.848 0 52.872 0.084 ;
    END
  END d[44]
  PIN d[450]
    DIRECTION INPUT ;
    USE SIGNAL ;
    PORT
      LAYER M5 ;
        RECT  170.352 0 170.376 0.084 ;
    END
  END d[450]
  PIN d[451]
    DIRECTION INPUT ;
    USE SIGNAL ;
    PORT
      LAYER M5 ;
        RECT  170.64 0 170.664 0.084 ;
    END
  END d[451]
  PIN d[452]
    DIRECTION INPUT ;
    USE SIGNAL ;
    PORT
      LAYER M5 ;
        RECT  170.928 0 170.952 0.084 ;
    END
  END d[452]
  PIN d[453]
    DIRECTION INPUT ;
    USE SIGNAL ;
    PORT
      LAYER M5 ;
        RECT  171.216 0 171.24 0.084 ;
    END
  END d[453]
  PIN d[454]
    DIRECTION INPUT ;
    USE SIGNAL ;
    PORT
      LAYER M5 ;
        RECT  171.504 0 171.528 0.084 ;
    END
  END d[454]
  PIN d[455]
    DIRECTION INPUT ;
    USE SIGNAL ;
    PORT
      LAYER M5 ;
        RECT  171.792 0 171.816 0.084 ;
    END
  END d[455]
  PIN d[456]
    DIRECTION INPUT ;
    USE SIGNAL ;
    PORT
      LAYER M5 ;
        RECT  172.08 0 172.104 0.084 ;
    END
  END d[456]
  PIN d[457]
    DIRECTION INPUT ;
    USE SIGNAL ;
    PORT
      LAYER M5 ;
        RECT  172.368 0 172.392 0.084 ;
    END
  END d[457]
  PIN d[458]
    DIRECTION INPUT ;
    USE SIGNAL ;
    PORT
      LAYER M5 ;
        RECT  172.656 0 172.68 0.084 ;
    END
  END d[458]
  PIN d[459]
    DIRECTION INPUT ;
    USE SIGNAL ;
    PORT
      LAYER M5 ;
        RECT  172.944 0 172.968 0.084 ;
    END
  END d[459]
  PIN d[45]
    DIRECTION INPUT ;
    USE SIGNAL ;
    PORT
      LAYER M5 ;
        RECT  53.136 0 53.16 0.084 ;
    END
  END d[45]
  PIN d[460]
    DIRECTION INPUT ;
    USE SIGNAL ;
    PORT
      LAYER M5 ;
        RECT  173.232 0 173.256 0.084 ;
    END
  END d[460]
  PIN d[461]
    DIRECTION INPUT ;
    USE SIGNAL ;
    PORT
      LAYER M5 ;
        RECT  173.52 0 173.544 0.084 ;
    END
  END d[461]
  PIN d[462]
    DIRECTION INPUT ;
    USE SIGNAL ;
    PORT
      LAYER M5 ;
        RECT  173.808 0 173.832 0.084 ;
    END
  END d[462]
  PIN d[463]
    DIRECTION INPUT ;
    USE SIGNAL ;
    PORT
      LAYER M5 ;
        RECT  174.096 0 174.12 0.084 ;
    END
  END d[463]
  PIN d[464]
    DIRECTION INPUT ;
    USE SIGNAL ;
    PORT
      LAYER M5 ;
        RECT  174.384 0 174.408 0.084 ;
    END
  END d[464]
  PIN d[465]
    DIRECTION INPUT ;
    USE SIGNAL ;
    PORT
      LAYER M5 ;
        RECT  174.672 0 174.696 0.084 ;
    END
  END d[465]
  PIN d[466]
    DIRECTION INPUT ;
    USE SIGNAL ;
    PORT
      LAYER M5 ;
        RECT  174.96 0 174.984 0.084 ;
    END
  END d[466]
  PIN d[467]
    DIRECTION INPUT ;
    USE SIGNAL ;
    PORT
      LAYER M5 ;
        RECT  175.248 0 175.272 0.084 ;
    END
  END d[467]
  PIN d[468]
    DIRECTION INPUT ;
    USE SIGNAL ;
    PORT
      LAYER M5 ;
        RECT  175.536 0 175.56 0.084 ;
    END
  END d[468]
  PIN d[469]
    DIRECTION INPUT ;
    USE SIGNAL ;
    PORT
      LAYER M5 ;
        RECT  175.824 0 175.848 0.084 ;
    END
  END d[469]
  PIN d[46]
    DIRECTION INPUT ;
    USE SIGNAL ;
    PORT
      LAYER M5 ;
        RECT  53.424 0 53.448 0.084 ;
    END
  END d[46]
  PIN d[470]
    DIRECTION INPUT ;
    USE SIGNAL ;
    PORT
      LAYER M5 ;
        RECT  176.112 0 176.136 0.084 ;
    END
  END d[470]
  PIN d[471]
    DIRECTION INPUT ;
    USE SIGNAL ;
    PORT
      LAYER M5 ;
        RECT  176.4 0 176.424 0.084 ;
    END
  END d[471]
  PIN d[472]
    DIRECTION INPUT ;
    USE SIGNAL ;
    PORT
      LAYER M5 ;
        RECT  176.688 0 176.712 0.084 ;
    END
  END d[472]
  PIN d[473]
    DIRECTION INPUT ;
    USE SIGNAL ;
    PORT
      LAYER M5 ;
        RECT  176.976 0 177 0.084 ;
    END
  END d[473]
  PIN d[474]
    DIRECTION INPUT ;
    USE SIGNAL ;
    PORT
      LAYER M5 ;
        RECT  177.264 0 177.288 0.084 ;
    END
  END d[474]
  PIN d[475]
    DIRECTION INPUT ;
    USE SIGNAL ;
    PORT
      LAYER M5 ;
        RECT  177.552 0 177.576 0.084 ;
    END
  END d[475]
  PIN d[476]
    DIRECTION INPUT ;
    USE SIGNAL ;
    PORT
      LAYER M5 ;
        RECT  177.84 0 177.864 0.084 ;
    END
  END d[476]
  PIN d[477]
    DIRECTION INPUT ;
    USE SIGNAL ;
    PORT
      LAYER M5 ;
        RECT  178.128 0 178.152 0.084 ;
    END
  END d[477]
  PIN d[478]
    DIRECTION INPUT ;
    USE SIGNAL ;
    PORT
      LAYER M5 ;
        RECT  178.416 0 178.44 0.084 ;
    END
  END d[478]
  PIN d[479]
    DIRECTION INPUT ;
    USE SIGNAL ;
    PORT
      LAYER M5 ;
        RECT  178.704 0 178.728 0.084 ;
    END
  END d[479]
  PIN d[47]
    DIRECTION INPUT ;
    USE SIGNAL ;
    PORT
      LAYER M5 ;
        RECT  53.712 0 53.736 0.084 ;
    END
  END d[47]
  PIN d[480]
    DIRECTION INPUT ;
    USE SIGNAL ;
    PORT
      LAYER M5 ;
        RECT  178.992 0 179.016 0.084 ;
    END
  END d[480]
  PIN d[481]
    DIRECTION INPUT ;
    USE SIGNAL ;
    PORT
      LAYER M5 ;
        RECT  179.28 0 179.304 0.084 ;
    END
  END d[481]
  PIN d[482]
    DIRECTION INPUT ;
    USE SIGNAL ;
    PORT
      LAYER M5 ;
        RECT  179.568 0 179.592 0.084 ;
    END
  END d[482]
  PIN d[483]
    DIRECTION INPUT ;
    USE SIGNAL ;
    PORT
      LAYER M5 ;
        RECT  179.856 0 179.88 0.084 ;
    END
  END d[483]
  PIN d[484]
    DIRECTION INPUT ;
    USE SIGNAL ;
    PORT
      LAYER M5 ;
        RECT  180.144 0 180.168 0.084 ;
    END
  END d[484]
  PIN d[485]
    DIRECTION INPUT ;
    USE SIGNAL ;
    PORT
      LAYER M5 ;
        RECT  180.432 0 180.456 0.084 ;
    END
  END d[485]
  PIN d[486]
    DIRECTION INPUT ;
    USE SIGNAL ;
    PORT
      LAYER M5 ;
        RECT  180.72 0 180.744 0.084 ;
    END
  END d[486]
  PIN d[487]
    DIRECTION INPUT ;
    USE SIGNAL ;
    PORT
      LAYER M5 ;
        RECT  181.008 0 181.032 0.084 ;
    END
  END d[487]
  PIN d[488]
    DIRECTION INPUT ;
    USE SIGNAL ;
    PORT
      LAYER M5 ;
        RECT  181.296 0 181.32 0.084 ;
    END
  END d[488]
  PIN d[489]
    DIRECTION INPUT ;
    USE SIGNAL ;
    PORT
      LAYER M5 ;
        RECT  181.584 0 181.608 0.084 ;
    END
  END d[489]
  PIN d[48]
    DIRECTION INPUT ;
    USE SIGNAL ;
    PORT
      LAYER M5 ;
        RECT  54 0 54.024 0.084 ;
    END
  END d[48]
  PIN d[490]
    DIRECTION INPUT ;
    USE SIGNAL ;
    PORT
      LAYER M5 ;
        RECT  181.872 0 181.896 0.084 ;
    END
  END d[490]
  PIN d[491]
    DIRECTION INPUT ;
    USE SIGNAL ;
    PORT
      LAYER M5 ;
        RECT  182.16 0 182.184 0.084 ;
    END
  END d[491]
  PIN d[492]
    DIRECTION INPUT ;
    USE SIGNAL ;
    PORT
      LAYER M5 ;
        RECT  182.448 0 182.472 0.084 ;
    END
  END d[492]
  PIN d[493]
    DIRECTION INPUT ;
    USE SIGNAL ;
    PORT
      LAYER M5 ;
        RECT  182.736 0 182.76 0.084 ;
    END
  END d[493]
  PIN d[494]
    DIRECTION INPUT ;
    USE SIGNAL ;
    PORT
      LAYER M5 ;
        RECT  183.024 0 183.048 0.084 ;
    END
  END d[494]
  PIN d[495]
    DIRECTION INPUT ;
    USE SIGNAL ;
    PORT
      LAYER M5 ;
        RECT  183.312 0 183.336 0.084 ;
    END
  END d[495]
  PIN d[496]
    DIRECTION INPUT ;
    USE SIGNAL ;
    PORT
      LAYER M5 ;
        RECT  183.6 0 183.624 0.084 ;
    END
  END d[496]
  PIN d[497]
    DIRECTION INPUT ;
    USE SIGNAL ;
    PORT
      LAYER M5 ;
        RECT  183.888 0 183.912 0.084 ;
    END
  END d[497]
  PIN d[498]
    DIRECTION INPUT ;
    USE SIGNAL ;
    PORT
      LAYER M5 ;
        RECT  184.176 0 184.2 0.084 ;
    END
  END d[498]
  PIN d[499]
    DIRECTION INPUT ;
    USE SIGNAL ;
    PORT
      LAYER M5 ;
        RECT  184.464 0 184.488 0.084 ;
    END
  END d[499]
  PIN d[49]
    DIRECTION INPUT ;
    USE SIGNAL ;
    PORT
      LAYER M5 ;
        RECT  54.288 0 54.312 0.084 ;
    END
  END d[49]
  PIN d[4]
    DIRECTION INPUT ;
    USE SIGNAL ;
    PORT
      LAYER M5 ;
        RECT  41.328 0 41.352 0.084 ;
    END
  END d[4]
  PIN d[500]
    DIRECTION INPUT ;
    USE SIGNAL ;
    PORT
      LAYER M5 ;
        RECT  184.752 0 184.776 0.084 ;
    END
  END d[500]
  PIN d[501]
    DIRECTION INPUT ;
    USE SIGNAL ;
    PORT
      LAYER M5 ;
        RECT  185.04 0 185.064 0.084 ;
    END
  END d[501]
  PIN d[502]
    DIRECTION INPUT ;
    USE SIGNAL ;
    PORT
      LAYER M5 ;
        RECT  185.328 0 185.352 0.084 ;
    END
  END d[502]
  PIN d[503]
    DIRECTION INPUT ;
    USE SIGNAL ;
    PORT
      LAYER M5 ;
        RECT  185.616 0 185.64 0.084 ;
    END
  END d[503]
  PIN d[504]
    DIRECTION INPUT ;
    USE SIGNAL ;
    PORT
      LAYER M5 ;
        RECT  185.904 0 185.928 0.084 ;
    END
  END d[504]
  PIN d[505]
    DIRECTION INPUT ;
    USE SIGNAL ;
    PORT
      LAYER M5 ;
        RECT  186.192 0 186.216 0.084 ;
    END
  END d[505]
  PIN d[506]
    DIRECTION INPUT ;
    USE SIGNAL ;
    PORT
      LAYER M5 ;
        RECT  186.48 0 186.504 0.084 ;
    END
  END d[506]
  PIN d[507]
    DIRECTION INPUT ;
    USE SIGNAL ;
    PORT
      LAYER M5 ;
        RECT  186.768 0 186.792 0.084 ;
    END
  END d[507]
  PIN d[508]
    DIRECTION INPUT ;
    USE SIGNAL ;
    PORT
      LAYER M5 ;
        RECT  187.056 0 187.08 0.084 ;
    END
  END d[508]
  PIN d[509]
    DIRECTION INPUT ;
    USE SIGNAL ;
    PORT
      LAYER M5 ;
        RECT  187.344 0 187.368 0.084 ;
    END
  END d[509]
  PIN d[50]
    DIRECTION INPUT ;
    USE SIGNAL ;
    PORT
      LAYER M5 ;
        RECT  54.576 0 54.6 0.084 ;
    END
  END d[50]
  PIN d[510]
    DIRECTION INPUT ;
    USE SIGNAL ;
    PORT
      LAYER M5 ;
        RECT  187.632 0 187.656 0.084 ;
    END
  END d[510]
  PIN d[511]
    DIRECTION INPUT ;
    USE SIGNAL ;
    PORT
      LAYER M5 ;
        RECT  187.92 0 187.944 0.084 ;
    END
  END d[511]
  PIN d[512]
    DIRECTION INPUT ;
    USE SIGNAL ;
    PORT
      LAYER M5 ;
        RECT  188.208 0 188.232 0.084 ;
    END
  END d[512]
  PIN d[513]
    DIRECTION INPUT ;
    USE SIGNAL ;
    PORT
      LAYER M5 ;
        RECT  188.496 0 188.52 0.084 ;
    END
  END d[513]
  PIN d[514]
    DIRECTION INPUT ;
    USE SIGNAL ;
    PORT
      LAYER M5 ;
        RECT  188.784 0 188.808 0.084 ;
    END
  END d[514]
  PIN d[51]
    DIRECTION INPUT ;
    USE SIGNAL ;
    PORT
      LAYER M5 ;
        RECT  54.864 0 54.888 0.084 ;
    END
  END d[51]
  PIN d[52]
    DIRECTION INPUT ;
    USE SIGNAL ;
    PORT
      LAYER M5 ;
        RECT  55.152 0 55.176 0.084 ;
    END
  END d[52]
  PIN d[53]
    DIRECTION INPUT ;
    USE SIGNAL ;
    PORT
      LAYER M5 ;
        RECT  55.44 0 55.464 0.084 ;
    END
  END d[53]
  PIN d[54]
    DIRECTION INPUT ;
    USE SIGNAL ;
    PORT
      LAYER M5 ;
        RECT  55.728 0 55.752 0.084 ;
    END
  END d[54]
  PIN d[55]
    DIRECTION INPUT ;
    USE SIGNAL ;
    PORT
      LAYER M5 ;
        RECT  56.016 0 56.04 0.084 ;
    END
  END d[55]
  PIN d[56]
    DIRECTION INPUT ;
    USE SIGNAL ;
    PORT
      LAYER M5 ;
        RECT  56.304 0 56.328 0.084 ;
    END
  END d[56]
  PIN d[57]
    DIRECTION INPUT ;
    USE SIGNAL ;
    PORT
      LAYER M5 ;
        RECT  56.592 0 56.616 0.084 ;
    END
  END d[57]
  PIN d[58]
    DIRECTION INPUT ;
    USE SIGNAL ;
    PORT
      LAYER M5 ;
        RECT  56.88 0 56.904 0.084 ;
    END
  END d[58]
  PIN d[59]
    DIRECTION INPUT ;
    USE SIGNAL ;
    PORT
      LAYER M5 ;
        RECT  57.168 0 57.192 0.084 ;
    END
  END d[59]
  PIN d[5]
    DIRECTION INPUT ;
    USE SIGNAL ;
    PORT
      LAYER M5 ;
        RECT  41.616 0 41.64 0.084 ;
    END
  END d[5]
  PIN d[60]
    DIRECTION INPUT ;
    USE SIGNAL ;
    PORT
      LAYER M5 ;
        RECT  57.456 0 57.48 0.084 ;
    END
  END d[60]
  PIN d[61]
    DIRECTION INPUT ;
    USE SIGNAL ;
    PORT
      LAYER M5 ;
        RECT  57.744 0 57.768 0.084 ;
    END
  END d[61]
  PIN d[62]
    DIRECTION INPUT ;
    USE SIGNAL ;
    PORT
      LAYER M5 ;
        RECT  58.032 0 58.056 0.084 ;
    END
  END d[62]
  PIN d[63]
    DIRECTION INPUT ;
    USE SIGNAL ;
    PORT
      LAYER M5 ;
        RECT  58.32 0 58.344 0.084 ;
    END
  END d[63]
  PIN d[64]
    DIRECTION INPUT ;
    USE SIGNAL ;
    PORT
      LAYER M5 ;
        RECT  58.608 0 58.632 0.084 ;
    END
  END d[64]
  PIN d[65]
    DIRECTION INPUT ;
    USE SIGNAL ;
    PORT
      LAYER M5 ;
        RECT  58.896 0 58.92 0.084 ;
    END
  END d[65]
  PIN d[66]
    DIRECTION INPUT ;
    USE SIGNAL ;
    PORT
      LAYER M5 ;
        RECT  59.184 0 59.208 0.084 ;
    END
  END d[66]
  PIN d[67]
    DIRECTION INPUT ;
    USE SIGNAL ;
    PORT
      LAYER M5 ;
        RECT  59.472 0 59.496 0.084 ;
    END
  END d[67]
  PIN d[68]
    DIRECTION INPUT ;
    USE SIGNAL ;
    PORT
      LAYER M5 ;
        RECT  59.76 0 59.784 0.084 ;
    END
  END d[68]
  PIN d[69]
    DIRECTION INPUT ;
    USE SIGNAL ;
    PORT
      LAYER M5 ;
        RECT  60.048 0 60.072 0.084 ;
    END
  END d[69]
  PIN d[6]
    DIRECTION INPUT ;
    USE SIGNAL ;
    PORT
      LAYER M5 ;
        RECT  41.904 0 41.928 0.084 ;
    END
  END d[6]
  PIN d[70]
    DIRECTION INPUT ;
    USE SIGNAL ;
    PORT
      LAYER M5 ;
        RECT  60.336 0 60.36 0.084 ;
    END
  END d[70]
  PIN d[71]
    DIRECTION INPUT ;
    USE SIGNAL ;
    PORT
      LAYER M5 ;
        RECT  60.624 0 60.648 0.084 ;
    END
  END d[71]
  PIN d[72]
    DIRECTION INPUT ;
    USE SIGNAL ;
    PORT
      LAYER M5 ;
        RECT  60.912 0 60.936 0.084 ;
    END
  END d[72]
  PIN d[73]
    DIRECTION INPUT ;
    USE SIGNAL ;
    PORT
      LAYER M5 ;
        RECT  61.2 0 61.224 0.084 ;
    END
  END d[73]
  PIN d[74]
    DIRECTION INPUT ;
    USE SIGNAL ;
    PORT
      LAYER M5 ;
        RECT  61.488 0 61.512 0.084 ;
    END
  END d[74]
  PIN d[75]
    DIRECTION INPUT ;
    USE SIGNAL ;
    PORT
      LAYER M5 ;
        RECT  61.776 0 61.8 0.084 ;
    END
  END d[75]
  PIN d[76]
    DIRECTION INPUT ;
    USE SIGNAL ;
    PORT
      LAYER M5 ;
        RECT  62.064 0 62.088 0.084 ;
    END
  END d[76]
  PIN d[77]
    DIRECTION INPUT ;
    USE SIGNAL ;
    PORT
      LAYER M5 ;
        RECT  62.352 0 62.376 0.084 ;
    END
  END d[77]
  PIN d[78]
    DIRECTION INPUT ;
    USE SIGNAL ;
    PORT
      LAYER M5 ;
        RECT  62.64 0 62.664 0.084 ;
    END
  END d[78]
  PIN d[79]
    DIRECTION INPUT ;
    USE SIGNAL ;
    PORT
      LAYER M5 ;
        RECT  62.928 0 62.952 0.084 ;
    END
  END d[79]
  PIN d[7]
    DIRECTION INPUT ;
    USE SIGNAL ;
    PORT
      LAYER M5 ;
        RECT  42.192 0 42.216 0.084 ;
    END
  END d[7]
  PIN d[80]
    DIRECTION INPUT ;
    USE SIGNAL ;
    PORT
      LAYER M5 ;
        RECT  63.216 0 63.24 0.084 ;
    END
  END d[80]
  PIN d[81]
    DIRECTION INPUT ;
    USE SIGNAL ;
    PORT
      LAYER M5 ;
        RECT  63.504 0 63.528 0.084 ;
    END
  END d[81]
  PIN d[82]
    DIRECTION INPUT ;
    USE SIGNAL ;
    PORT
      LAYER M5 ;
        RECT  63.792 0 63.816 0.084 ;
    END
  END d[82]
  PIN d[83]
    DIRECTION INPUT ;
    USE SIGNAL ;
    PORT
      LAYER M5 ;
        RECT  64.08 0 64.104 0.084 ;
    END
  END d[83]
  PIN d[84]
    DIRECTION INPUT ;
    USE SIGNAL ;
    PORT
      LAYER M5 ;
        RECT  64.368 0 64.392 0.084 ;
    END
  END d[84]
  PIN d[85]
    DIRECTION INPUT ;
    USE SIGNAL ;
    PORT
      LAYER M5 ;
        RECT  64.656 0 64.68 0.084 ;
    END
  END d[85]
  PIN d[86]
    DIRECTION INPUT ;
    USE SIGNAL ;
    PORT
      LAYER M5 ;
        RECT  64.944 0 64.968 0.084 ;
    END
  END d[86]
  PIN d[87]
    DIRECTION INPUT ;
    USE SIGNAL ;
    PORT
      LAYER M5 ;
        RECT  65.232 0 65.256 0.084 ;
    END
  END d[87]
  PIN d[88]
    DIRECTION INPUT ;
    USE SIGNAL ;
    PORT
      LAYER M5 ;
        RECT  65.52 0 65.544 0.084 ;
    END
  END d[88]
  PIN d[89]
    DIRECTION INPUT ;
    USE SIGNAL ;
    PORT
      LAYER M5 ;
        RECT  65.808 0 65.832 0.084 ;
    END
  END d[89]
  PIN d[8]
    DIRECTION INPUT ;
    USE SIGNAL ;
    PORT
      LAYER M5 ;
        RECT  42.48 0 42.504 0.084 ;
    END
  END d[8]
  PIN d[90]
    DIRECTION INPUT ;
    USE SIGNAL ;
    PORT
      LAYER M5 ;
        RECT  66.096 0 66.12 0.084 ;
    END
  END d[90]
  PIN d[91]
    DIRECTION INPUT ;
    USE SIGNAL ;
    PORT
      LAYER M5 ;
        RECT  66.384 0 66.408 0.084 ;
    END
  END d[91]
  PIN d[92]
    DIRECTION INPUT ;
    USE SIGNAL ;
    PORT
      LAYER M5 ;
        RECT  66.672 0 66.696 0.084 ;
    END
  END d[92]
  PIN d[93]
    DIRECTION INPUT ;
    USE SIGNAL ;
    PORT
      LAYER M5 ;
        RECT  66.96 0 66.984 0.084 ;
    END
  END d[93]
  PIN d[94]
    DIRECTION INPUT ;
    USE SIGNAL ;
    PORT
      LAYER M5 ;
        RECT  67.248 0 67.272 0.084 ;
    END
  END d[94]
  PIN d[95]
    DIRECTION INPUT ;
    USE SIGNAL ;
    PORT
      LAYER M5 ;
        RECT  67.536 0 67.56 0.084 ;
    END
  END d[95]
  PIN d[96]
    DIRECTION INPUT ;
    USE SIGNAL ;
    PORT
      LAYER M5 ;
        RECT  67.824 0 67.848 0.084 ;
    END
  END d[96]
  PIN d[97]
    DIRECTION INPUT ;
    USE SIGNAL ;
    PORT
      LAYER M5 ;
        RECT  68.112 0 68.136 0.084 ;
    END
  END d[97]
  PIN d[98]
    DIRECTION INPUT ;
    USE SIGNAL ;
    PORT
      LAYER M5 ;
        RECT  68.4 0 68.424 0.084 ;
    END
  END d[98]
  PIN d[99]
    DIRECTION INPUT ;
    USE SIGNAL ;
    PORT
      LAYER M5 ;
        RECT  68.688 0 68.712 0.084 ;
    END
  END d[99]
  PIN d[9]
    DIRECTION INPUT ;
    USE SIGNAL ;
    PORT
      LAYER M5 ;
        RECT  42.768 0 42.792 0.084 ;
    END
  END d[9]
  PIN fault
    DIRECTION OUTPUT ;
    USE SIGNAL ;
    PORT
      LAYER M5 ;
        RECT  113.904 25.836 113.928 25.92 ;
    END
  END fault
  PIN fclk
    DIRECTION INPUT ;
    USE SIGNAL ;
    PORT
      LAYER M5 ;
        RECT  114.192 0 114.216 0.084 ;
    END
  END fclk
  PIN q[0]
    DIRECTION OUTPUT ;
    USE SIGNAL ;
    PORT
      LAYER M5 ;
        RECT  39.024 25.836 39.048 25.92 ;
    END
  END q[0]
  PIN q[100]
    DIRECTION OUTPUT ;
    USE SIGNAL ;
    PORT
      LAYER M5 ;
        RECT  67.824 25.836 67.848 25.92 ;
    END
  END q[100]
  PIN q[101]
    DIRECTION OUTPUT ;
    USE SIGNAL ;
    PORT
      LAYER M5 ;
        RECT  68.112 25.836 68.136 25.92 ;
    END
  END q[101]
  PIN q[102]
    DIRECTION OUTPUT ;
    USE SIGNAL ;
    PORT
      LAYER M5 ;
        RECT  68.4 25.836 68.424 25.92 ;
    END
  END q[102]
  PIN q[103]
    DIRECTION OUTPUT ;
    USE SIGNAL ;
    PORT
      LAYER M5 ;
        RECT  68.688 25.836 68.712 25.92 ;
    END
  END q[103]
  PIN q[104]
    DIRECTION OUTPUT ;
    USE SIGNAL ;
    PORT
      LAYER M5 ;
        RECT  68.976 25.836 69 25.92 ;
    END
  END q[104]
  PIN q[105]
    DIRECTION OUTPUT ;
    USE SIGNAL ;
    PORT
      LAYER M5 ;
        RECT  69.264 25.836 69.288 25.92 ;
    END
  END q[105]
  PIN q[106]
    DIRECTION OUTPUT ;
    USE SIGNAL ;
    PORT
      LAYER M5 ;
        RECT  69.552 25.836 69.576 25.92 ;
    END
  END q[106]
  PIN q[107]
    DIRECTION OUTPUT ;
    USE SIGNAL ;
    PORT
      LAYER M5 ;
        RECT  69.84 25.836 69.864 25.92 ;
    END
  END q[107]
  PIN q[108]
    DIRECTION OUTPUT ;
    USE SIGNAL ;
    PORT
      LAYER M5 ;
        RECT  70.128 25.836 70.152 25.92 ;
    END
  END q[108]
  PIN q[109]
    DIRECTION OUTPUT ;
    USE SIGNAL ;
    PORT
      LAYER M5 ;
        RECT  70.416 25.836 70.44 25.92 ;
    END
  END q[109]
  PIN q[10]
    DIRECTION OUTPUT ;
    USE SIGNAL ;
    PORT
      LAYER M5 ;
        RECT  41.904 25.836 41.928 25.92 ;
    END
  END q[10]
  PIN q[110]
    DIRECTION OUTPUT ;
    USE SIGNAL ;
    PORT
      LAYER M5 ;
        RECT  70.704 25.836 70.728 25.92 ;
    END
  END q[110]
  PIN q[111]
    DIRECTION OUTPUT ;
    USE SIGNAL ;
    PORT
      LAYER M5 ;
        RECT  70.992 25.836 71.016 25.92 ;
    END
  END q[111]
  PIN q[112]
    DIRECTION OUTPUT ;
    USE SIGNAL ;
    PORT
      LAYER M5 ;
        RECT  71.28 25.836 71.304 25.92 ;
    END
  END q[112]
  PIN q[113]
    DIRECTION OUTPUT ;
    USE SIGNAL ;
    PORT
      LAYER M5 ;
        RECT  71.568 25.836 71.592 25.92 ;
    END
  END q[113]
  PIN q[114]
    DIRECTION OUTPUT ;
    USE SIGNAL ;
    PORT
      LAYER M5 ;
        RECT  71.856 25.836 71.88 25.92 ;
    END
  END q[114]
  PIN q[115]
    DIRECTION OUTPUT ;
    USE SIGNAL ;
    PORT
      LAYER M5 ;
        RECT  72.144 25.836 72.168 25.92 ;
    END
  END q[115]
  PIN q[116]
    DIRECTION OUTPUT ;
    USE SIGNAL ;
    PORT
      LAYER M5 ;
        RECT  72.432 25.836 72.456 25.92 ;
    END
  END q[116]
  PIN q[117]
    DIRECTION OUTPUT ;
    USE SIGNAL ;
    PORT
      LAYER M5 ;
        RECT  72.72 25.836 72.744 25.92 ;
    END
  END q[117]
  PIN q[118]
    DIRECTION OUTPUT ;
    USE SIGNAL ;
    PORT
      LAYER M5 ;
        RECT  73.008 25.836 73.032 25.92 ;
    END
  END q[118]
  PIN q[119]
    DIRECTION OUTPUT ;
    USE SIGNAL ;
    PORT
      LAYER M5 ;
        RECT  73.296 25.836 73.32 25.92 ;
    END
  END q[119]
  PIN q[11]
    DIRECTION OUTPUT ;
    USE SIGNAL ;
    PORT
      LAYER M5 ;
        RECT  42.192 25.836 42.216 25.92 ;
    END
  END q[11]
  PIN q[120]
    DIRECTION OUTPUT ;
    USE SIGNAL ;
    PORT
      LAYER M5 ;
        RECT  73.584 25.836 73.608 25.92 ;
    END
  END q[120]
  PIN q[121]
    DIRECTION OUTPUT ;
    USE SIGNAL ;
    PORT
      LAYER M5 ;
        RECT  73.872 25.836 73.896 25.92 ;
    END
  END q[121]
  PIN q[122]
    DIRECTION OUTPUT ;
    USE SIGNAL ;
    PORT
      LAYER M5 ;
        RECT  74.16 25.836 74.184 25.92 ;
    END
  END q[122]
  PIN q[123]
    DIRECTION OUTPUT ;
    USE SIGNAL ;
    PORT
      LAYER M5 ;
        RECT  74.448 25.836 74.472 25.92 ;
    END
  END q[123]
  PIN q[124]
    DIRECTION OUTPUT ;
    USE SIGNAL ;
    PORT
      LAYER M5 ;
        RECT  74.736 25.836 74.76 25.92 ;
    END
  END q[124]
  PIN q[125]
    DIRECTION OUTPUT ;
    USE SIGNAL ;
    PORT
      LAYER M5 ;
        RECT  75.024 25.836 75.048 25.92 ;
    END
  END q[125]
  PIN q[126]
    DIRECTION OUTPUT ;
    USE SIGNAL ;
    PORT
      LAYER M5 ;
        RECT  75.312 25.836 75.336 25.92 ;
    END
  END q[126]
  PIN q[127]
    DIRECTION OUTPUT ;
    USE SIGNAL ;
    PORT
      LAYER M5 ;
        RECT  75.6 25.836 75.624 25.92 ;
    END
  END q[127]
  PIN q[128]
    DIRECTION OUTPUT ;
    USE SIGNAL ;
    PORT
      LAYER M5 ;
        RECT  75.888 25.836 75.912 25.92 ;
    END
  END q[128]
  PIN q[129]
    DIRECTION OUTPUT ;
    USE SIGNAL ;
    PORT
      LAYER M5 ;
        RECT  76.176 25.836 76.2 25.92 ;
    END
  END q[129]
  PIN q[12]
    DIRECTION OUTPUT ;
    USE SIGNAL ;
    PORT
      LAYER M5 ;
        RECT  42.48 25.836 42.504 25.92 ;
    END
  END q[12]
  PIN q[130]
    DIRECTION OUTPUT ;
    USE SIGNAL ;
    PORT
      LAYER M5 ;
        RECT  76.464 25.836 76.488 25.92 ;
    END
  END q[130]
  PIN q[131]
    DIRECTION OUTPUT ;
    USE SIGNAL ;
    PORT
      LAYER M5 ;
        RECT  76.752 25.836 76.776 25.92 ;
    END
  END q[131]
  PIN q[132]
    DIRECTION OUTPUT ;
    USE SIGNAL ;
    PORT
      LAYER M5 ;
        RECT  77.04 25.836 77.064 25.92 ;
    END
  END q[132]
  PIN q[133]
    DIRECTION OUTPUT ;
    USE SIGNAL ;
    PORT
      LAYER M5 ;
        RECT  77.328 25.836 77.352 25.92 ;
    END
  END q[133]
  PIN q[134]
    DIRECTION OUTPUT ;
    USE SIGNAL ;
    PORT
      LAYER M5 ;
        RECT  77.616 25.836 77.64 25.92 ;
    END
  END q[134]
  PIN q[135]
    DIRECTION OUTPUT ;
    USE SIGNAL ;
    PORT
      LAYER M5 ;
        RECT  77.904 25.836 77.928 25.92 ;
    END
  END q[135]
  PIN q[136]
    DIRECTION OUTPUT ;
    USE SIGNAL ;
    PORT
      LAYER M5 ;
        RECT  78.192 25.836 78.216 25.92 ;
    END
  END q[136]
  PIN q[137]
    DIRECTION OUTPUT ;
    USE SIGNAL ;
    PORT
      LAYER M5 ;
        RECT  78.48 25.836 78.504 25.92 ;
    END
  END q[137]
  PIN q[138]
    DIRECTION OUTPUT ;
    USE SIGNAL ;
    PORT
      LAYER M5 ;
        RECT  78.768 25.836 78.792 25.92 ;
    END
  END q[138]
  PIN q[139]
    DIRECTION OUTPUT ;
    USE SIGNAL ;
    PORT
      LAYER M5 ;
        RECT  79.056 25.836 79.08 25.92 ;
    END
  END q[139]
  PIN q[13]
    DIRECTION OUTPUT ;
    USE SIGNAL ;
    PORT
      LAYER M5 ;
        RECT  42.768 25.836 42.792 25.92 ;
    END
  END q[13]
  PIN q[140]
    DIRECTION OUTPUT ;
    USE SIGNAL ;
    PORT
      LAYER M5 ;
        RECT  79.344 25.836 79.368 25.92 ;
    END
  END q[140]
  PIN q[141]
    DIRECTION OUTPUT ;
    USE SIGNAL ;
    PORT
      LAYER M5 ;
        RECT  79.632 25.836 79.656 25.92 ;
    END
  END q[141]
  PIN q[142]
    DIRECTION OUTPUT ;
    USE SIGNAL ;
    PORT
      LAYER M5 ;
        RECT  79.92 25.836 79.944 25.92 ;
    END
  END q[142]
  PIN q[143]
    DIRECTION OUTPUT ;
    USE SIGNAL ;
    PORT
      LAYER M5 ;
        RECT  80.208 25.836 80.232 25.92 ;
    END
  END q[143]
  PIN q[144]
    DIRECTION OUTPUT ;
    USE SIGNAL ;
    PORT
      LAYER M5 ;
        RECT  80.496 25.836 80.52 25.92 ;
    END
  END q[144]
  PIN q[145]
    DIRECTION OUTPUT ;
    USE SIGNAL ;
    PORT
      LAYER M5 ;
        RECT  80.784 25.836 80.808 25.92 ;
    END
  END q[145]
  PIN q[146]
    DIRECTION OUTPUT ;
    USE SIGNAL ;
    PORT
      LAYER M5 ;
        RECT  81.072 25.836 81.096 25.92 ;
    END
  END q[146]
  PIN q[147]
    DIRECTION OUTPUT ;
    USE SIGNAL ;
    PORT
      LAYER M5 ;
        RECT  81.36 25.836 81.384 25.92 ;
    END
  END q[147]
  PIN q[148]
    DIRECTION OUTPUT ;
    USE SIGNAL ;
    PORT
      LAYER M5 ;
        RECT  81.648 25.836 81.672 25.92 ;
    END
  END q[148]
  PIN q[149]
    DIRECTION OUTPUT ;
    USE SIGNAL ;
    PORT
      LAYER M5 ;
        RECT  81.936 25.836 81.96 25.92 ;
    END
  END q[149]
  PIN q[14]
    DIRECTION OUTPUT ;
    USE SIGNAL ;
    PORT
      LAYER M5 ;
        RECT  43.056 25.836 43.08 25.92 ;
    END
  END q[14]
  PIN q[150]
    DIRECTION OUTPUT ;
    USE SIGNAL ;
    PORT
      LAYER M5 ;
        RECT  82.224 25.836 82.248 25.92 ;
    END
  END q[150]
  PIN q[151]
    DIRECTION OUTPUT ;
    USE SIGNAL ;
    PORT
      LAYER M5 ;
        RECT  82.512 25.836 82.536 25.92 ;
    END
  END q[151]
  PIN q[152]
    DIRECTION OUTPUT ;
    USE SIGNAL ;
    PORT
      LAYER M5 ;
        RECT  82.8 25.836 82.824 25.92 ;
    END
  END q[152]
  PIN q[153]
    DIRECTION OUTPUT ;
    USE SIGNAL ;
    PORT
      LAYER M5 ;
        RECT  83.088 25.836 83.112 25.92 ;
    END
  END q[153]
  PIN q[154]
    DIRECTION OUTPUT ;
    USE SIGNAL ;
    PORT
      LAYER M5 ;
        RECT  83.376 25.836 83.4 25.92 ;
    END
  END q[154]
  PIN q[155]
    DIRECTION OUTPUT ;
    USE SIGNAL ;
    PORT
      LAYER M5 ;
        RECT  83.664 25.836 83.688 25.92 ;
    END
  END q[155]
  PIN q[156]
    DIRECTION OUTPUT ;
    USE SIGNAL ;
    PORT
      LAYER M5 ;
        RECT  83.952 25.836 83.976 25.92 ;
    END
  END q[156]
  PIN q[157]
    DIRECTION OUTPUT ;
    USE SIGNAL ;
    PORT
      LAYER M5 ;
        RECT  84.24 25.836 84.264 25.92 ;
    END
  END q[157]
  PIN q[158]
    DIRECTION OUTPUT ;
    USE SIGNAL ;
    PORT
      LAYER M5 ;
        RECT  84.528 25.836 84.552 25.92 ;
    END
  END q[158]
  PIN q[159]
    DIRECTION OUTPUT ;
    USE SIGNAL ;
    PORT
      LAYER M5 ;
        RECT  84.816 25.836 84.84 25.92 ;
    END
  END q[159]
  PIN q[15]
    DIRECTION OUTPUT ;
    USE SIGNAL ;
    PORT
      LAYER M5 ;
        RECT  43.344 25.836 43.368 25.92 ;
    END
  END q[15]
  PIN q[160]
    DIRECTION OUTPUT ;
    USE SIGNAL ;
    PORT
      LAYER M5 ;
        RECT  85.104 25.836 85.128 25.92 ;
    END
  END q[160]
  PIN q[161]
    DIRECTION OUTPUT ;
    USE SIGNAL ;
    PORT
      LAYER M5 ;
        RECT  85.392 25.836 85.416 25.92 ;
    END
  END q[161]
  PIN q[162]
    DIRECTION OUTPUT ;
    USE SIGNAL ;
    PORT
      LAYER M5 ;
        RECT  85.68 25.836 85.704 25.92 ;
    END
  END q[162]
  PIN q[163]
    DIRECTION OUTPUT ;
    USE SIGNAL ;
    PORT
      LAYER M5 ;
        RECT  85.968 25.836 85.992 25.92 ;
    END
  END q[163]
  PIN q[164]
    DIRECTION OUTPUT ;
    USE SIGNAL ;
    PORT
      LAYER M5 ;
        RECT  86.256 25.836 86.28 25.92 ;
    END
  END q[164]
  PIN q[165]
    DIRECTION OUTPUT ;
    USE SIGNAL ;
    PORT
      LAYER M5 ;
        RECT  86.544 25.836 86.568 25.92 ;
    END
  END q[165]
  PIN q[166]
    DIRECTION OUTPUT ;
    USE SIGNAL ;
    PORT
      LAYER M5 ;
        RECT  86.832 25.836 86.856 25.92 ;
    END
  END q[166]
  PIN q[167]
    DIRECTION OUTPUT ;
    USE SIGNAL ;
    PORT
      LAYER M5 ;
        RECT  87.12 25.836 87.144 25.92 ;
    END
  END q[167]
  PIN q[168]
    DIRECTION OUTPUT ;
    USE SIGNAL ;
    PORT
      LAYER M5 ;
        RECT  87.408 25.836 87.432 25.92 ;
    END
  END q[168]
  PIN q[169]
    DIRECTION OUTPUT ;
    USE SIGNAL ;
    PORT
      LAYER M5 ;
        RECT  87.696 25.836 87.72 25.92 ;
    END
  END q[169]
  PIN q[16]
    DIRECTION OUTPUT ;
    USE SIGNAL ;
    PORT
      LAYER M5 ;
        RECT  43.632 25.836 43.656 25.92 ;
    END
  END q[16]
  PIN q[170]
    DIRECTION OUTPUT ;
    USE SIGNAL ;
    PORT
      LAYER M5 ;
        RECT  87.984 25.836 88.008 25.92 ;
    END
  END q[170]
  PIN q[171]
    DIRECTION OUTPUT ;
    USE SIGNAL ;
    PORT
      LAYER M5 ;
        RECT  88.272 25.836 88.296 25.92 ;
    END
  END q[171]
  PIN q[172]
    DIRECTION OUTPUT ;
    USE SIGNAL ;
    PORT
      LAYER M5 ;
        RECT  88.56 25.836 88.584 25.92 ;
    END
  END q[172]
  PIN q[173]
    DIRECTION OUTPUT ;
    USE SIGNAL ;
    PORT
      LAYER M5 ;
        RECT  88.848 25.836 88.872 25.92 ;
    END
  END q[173]
  PIN q[174]
    DIRECTION OUTPUT ;
    USE SIGNAL ;
    PORT
      LAYER M5 ;
        RECT  89.136 25.836 89.16 25.92 ;
    END
  END q[174]
  PIN q[175]
    DIRECTION OUTPUT ;
    USE SIGNAL ;
    PORT
      LAYER M5 ;
        RECT  89.424 25.836 89.448 25.92 ;
    END
  END q[175]
  PIN q[176]
    DIRECTION OUTPUT ;
    USE SIGNAL ;
    PORT
      LAYER M5 ;
        RECT  89.712 25.836 89.736 25.92 ;
    END
  END q[176]
  PIN q[177]
    DIRECTION OUTPUT ;
    USE SIGNAL ;
    PORT
      LAYER M5 ;
        RECT  90 25.836 90.024 25.92 ;
    END
  END q[177]
  PIN q[178]
    DIRECTION OUTPUT ;
    USE SIGNAL ;
    PORT
      LAYER M5 ;
        RECT  90.288 25.836 90.312 25.92 ;
    END
  END q[178]
  PIN q[179]
    DIRECTION OUTPUT ;
    USE SIGNAL ;
    PORT
      LAYER M5 ;
        RECT  90.576 25.836 90.6 25.92 ;
    END
  END q[179]
  PIN q[17]
    DIRECTION OUTPUT ;
    USE SIGNAL ;
    PORT
      LAYER M5 ;
        RECT  43.92 25.836 43.944 25.92 ;
    END
  END q[17]
  PIN q[180]
    DIRECTION OUTPUT ;
    USE SIGNAL ;
    PORT
      LAYER M5 ;
        RECT  90.864 25.836 90.888 25.92 ;
    END
  END q[180]
  PIN q[181]
    DIRECTION OUTPUT ;
    USE SIGNAL ;
    PORT
      LAYER M5 ;
        RECT  91.152 25.836 91.176 25.92 ;
    END
  END q[181]
  PIN q[182]
    DIRECTION OUTPUT ;
    USE SIGNAL ;
    PORT
      LAYER M5 ;
        RECT  91.44 25.836 91.464 25.92 ;
    END
  END q[182]
  PIN q[183]
    DIRECTION OUTPUT ;
    USE SIGNAL ;
    PORT
      LAYER M5 ;
        RECT  91.728 25.836 91.752 25.92 ;
    END
  END q[183]
  PIN q[184]
    DIRECTION OUTPUT ;
    USE SIGNAL ;
    PORT
      LAYER M5 ;
        RECT  92.016 25.836 92.04 25.92 ;
    END
  END q[184]
  PIN q[185]
    DIRECTION OUTPUT ;
    USE SIGNAL ;
    PORT
      LAYER M5 ;
        RECT  92.304 25.836 92.328 25.92 ;
    END
  END q[185]
  PIN q[186]
    DIRECTION OUTPUT ;
    USE SIGNAL ;
    PORT
      LAYER M5 ;
        RECT  92.592 25.836 92.616 25.92 ;
    END
  END q[186]
  PIN q[187]
    DIRECTION OUTPUT ;
    USE SIGNAL ;
    PORT
      LAYER M5 ;
        RECT  92.88 25.836 92.904 25.92 ;
    END
  END q[187]
  PIN q[188]
    DIRECTION OUTPUT ;
    USE SIGNAL ;
    PORT
      LAYER M5 ;
        RECT  93.168 25.836 93.192 25.92 ;
    END
  END q[188]
  PIN q[189]
    DIRECTION OUTPUT ;
    USE SIGNAL ;
    PORT
      LAYER M5 ;
        RECT  93.456 25.836 93.48 25.92 ;
    END
  END q[189]
  PIN q[18]
    DIRECTION OUTPUT ;
    USE SIGNAL ;
    PORT
      LAYER M5 ;
        RECT  44.208 25.836 44.232 25.92 ;
    END
  END q[18]
  PIN q[190]
    DIRECTION OUTPUT ;
    USE SIGNAL ;
    PORT
      LAYER M5 ;
        RECT  93.744 25.836 93.768 25.92 ;
    END
  END q[190]
  PIN q[191]
    DIRECTION OUTPUT ;
    USE SIGNAL ;
    PORT
      LAYER M5 ;
        RECT  94.032 25.836 94.056 25.92 ;
    END
  END q[191]
  PIN q[192]
    DIRECTION OUTPUT ;
    USE SIGNAL ;
    PORT
      LAYER M5 ;
        RECT  94.32 25.836 94.344 25.92 ;
    END
  END q[192]
  PIN q[193]
    DIRECTION OUTPUT ;
    USE SIGNAL ;
    PORT
      LAYER M5 ;
        RECT  94.608 25.836 94.632 25.92 ;
    END
  END q[193]
  PIN q[194]
    DIRECTION OUTPUT ;
    USE SIGNAL ;
    PORT
      LAYER M5 ;
        RECT  94.896 25.836 94.92 25.92 ;
    END
  END q[194]
  PIN q[195]
    DIRECTION OUTPUT ;
    USE SIGNAL ;
    PORT
      LAYER M5 ;
        RECT  95.184 25.836 95.208 25.92 ;
    END
  END q[195]
  PIN q[196]
    DIRECTION OUTPUT ;
    USE SIGNAL ;
    PORT
      LAYER M5 ;
        RECT  95.472 25.836 95.496 25.92 ;
    END
  END q[196]
  PIN q[197]
    DIRECTION OUTPUT ;
    USE SIGNAL ;
    PORT
      LAYER M5 ;
        RECT  95.76 25.836 95.784 25.92 ;
    END
  END q[197]
  PIN q[198]
    DIRECTION OUTPUT ;
    USE SIGNAL ;
    PORT
      LAYER M5 ;
        RECT  96.048 25.836 96.072 25.92 ;
    END
  END q[198]
  PIN q[199]
    DIRECTION OUTPUT ;
    USE SIGNAL ;
    PORT
      LAYER M5 ;
        RECT  96.336 25.836 96.36 25.92 ;
    END
  END q[199]
  PIN q[19]
    DIRECTION OUTPUT ;
    USE SIGNAL ;
    PORT
      LAYER M5 ;
        RECT  44.496 25.836 44.52 25.92 ;
    END
  END q[19]
  PIN q[1]
    DIRECTION OUTPUT ;
    USE SIGNAL ;
    PORT
      LAYER M5 ;
        RECT  39.312 25.836 39.336 25.92 ;
    END
  END q[1]
  PIN q[200]
    DIRECTION OUTPUT ;
    USE SIGNAL ;
    PORT
      LAYER M5 ;
        RECT  96.624 25.836 96.648 25.92 ;
    END
  END q[200]
  PIN q[201]
    DIRECTION OUTPUT ;
    USE SIGNAL ;
    PORT
      LAYER M5 ;
        RECT  96.912 25.836 96.936 25.92 ;
    END
  END q[201]
  PIN q[202]
    DIRECTION OUTPUT ;
    USE SIGNAL ;
    PORT
      LAYER M5 ;
        RECT  97.2 25.836 97.224 25.92 ;
    END
  END q[202]
  PIN q[203]
    DIRECTION OUTPUT ;
    USE SIGNAL ;
    PORT
      LAYER M5 ;
        RECT  97.488 25.836 97.512 25.92 ;
    END
  END q[203]
  PIN q[204]
    DIRECTION OUTPUT ;
    USE SIGNAL ;
    PORT
      LAYER M5 ;
        RECT  97.776 25.836 97.8 25.92 ;
    END
  END q[204]
  PIN q[205]
    DIRECTION OUTPUT ;
    USE SIGNAL ;
    PORT
      LAYER M5 ;
        RECT  98.064 25.836 98.088 25.92 ;
    END
  END q[205]
  PIN q[206]
    DIRECTION OUTPUT ;
    USE SIGNAL ;
    PORT
      LAYER M5 ;
        RECT  98.352 25.836 98.376 25.92 ;
    END
  END q[206]
  PIN q[207]
    DIRECTION OUTPUT ;
    USE SIGNAL ;
    PORT
      LAYER M5 ;
        RECT  98.64 25.836 98.664 25.92 ;
    END
  END q[207]
  PIN q[208]
    DIRECTION OUTPUT ;
    USE SIGNAL ;
    PORT
      LAYER M5 ;
        RECT  98.928 25.836 98.952 25.92 ;
    END
  END q[208]
  PIN q[209]
    DIRECTION OUTPUT ;
    USE SIGNAL ;
    PORT
      LAYER M5 ;
        RECT  99.216 25.836 99.24 25.92 ;
    END
  END q[209]
  PIN q[20]
    DIRECTION OUTPUT ;
    USE SIGNAL ;
    PORT
      LAYER M5 ;
        RECT  44.784 25.836 44.808 25.92 ;
    END
  END q[20]
  PIN q[210]
    DIRECTION OUTPUT ;
    USE SIGNAL ;
    PORT
      LAYER M5 ;
        RECT  99.504 25.836 99.528 25.92 ;
    END
  END q[210]
  PIN q[211]
    DIRECTION OUTPUT ;
    USE SIGNAL ;
    PORT
      LAYER M5 ;
        RECT  99.792 25.836 99.816 25.92 ;
    END
  END q[211]
  PIN q[212]
    DIRECTION OUTPUT ;
    USE SIGNAL ;
    PORT
      LAYER M5 ;
        RECT  100.08 25.836 100.104 25.92 ;
    END
  END q[212]
  PIN q[213]
    DIRECTION OUTPUT ;
    USE SIGNAL ;
    PORT
      LAYER M5 ;
        RECT  100.368 25.836 100.392 25.92 ;
    END
  END q[213]
  PIN q[214]
    DIRECTION OUTPUT ;
    USE SIGNAL ;
    PORT
      LAYER M5 ;
        RECT  100.656 25.836 100.68 25.92 ;
    END
  END q[214]
  PIN q[215]
    DIRECTION OUTPUT ;
    USE SIGNAL ;
    PORT
      LAYER M5 ;
        RECT  100.944 25.836 100.968 25.92 ;
    END
  END q[215]
  PIN q[216]
    DIRECTION OUTPUT ;
    USE SIGNAL ;
    PORT
      LAYER M5 ;
        RECT  101.232 25.836 101.256 25.92 ;
    END
  END q[216]
  PIN q[217]
    DIRECTION OUTPUT ;
    USE SIGNAL ;
    PORT
      LAYER M5 ;
        RECT  101.52 25.836 101.544 25.92 ;
    END
  END q[217]
  PIN q[218]
    DIRECTION OUTPUT ;
    USE SIGNAL ;
    PORT
      LAYER M5 ;
        RECT  101.808 25.836 101.832 25.92 ;
    END
  END q[218]
  PIN q[219]
    DIRECTION OUTPUT ;
    USE SIGNAL ;
    PORT
      LAYER M5 ;
        RECT  102.096 25.836 102.12 25.92 ;
    END
  END q[219]
  PIN q[21]
    DIRECTION OUTPUT ;
    USE SIGNAL ;
    PORT
      LAYER M5 ;
        RECT  45.072 25.836 45.096 25.92 ;
    END
  END q[21]
  PIN q[220]
    DIRECTION OUTPUT ;
    USE SIGNAL ;
    PORT
      LAYER M5 ;
        RECT  102.384 25.836 102.408 25.92 ;
    END
  END q[220]
  PIN q[221]
    DIRECTION OUTPUT ;
    USE SIGNAL ;
    PORT
      LAYER M5 ;
        RECT  102.672 25.836 102.696 25.92 ;
    END
  END q[221]
  PIN q[222]
    DIRECTION OUTPUT ;
    USE SIGNAL ;
    PORT
      LAYER M5 ;
        RECT  102.96 25.836 102.984 25.92 ;
    END
  END q[222]
  PIN q[223]
    DIRECTION OUTPUT ;
    USE SIGNAL ;
    PORT
      LAYER M5 ;
        RECT  103.248 25.836 103.272 25.92 ;
    END
  END q[223]
  PIN q[224]
    DIRECTION OUTPUT ;
    USE SIGNAL ;
    PORT
      LAYER M5 ;
        RECT  103.536 25.836 103.56 25.92 ;
    END
  END q[224]
  PIN q[225]
    DIRECTION OUTPUT ;
    USE SIGNAL ;
    PORT
      LAYER M5 ;
        RECT  103.824 25.836 103.848 25.92 ;
    END
  END q[225]
  PIN q[226]
    DIRECTION OUTPUT ;
    USE SIGNAL ;
    PORT
      LAYER M5 ;
        RECT  104.112 25.836 104.136 25.92 ;
    END
  END q[226]
  PIN q[227]
    DIRECTION OUTPUT ;
    USE SIGNAL ;
    PORT
      LAYER M5 ;
        RECT  104.4 25.836 104.424 25.92 ;
    END
  END q[227]
  PIN q[228]
    DIRECTION OUTPUT ;
    USE SIGNAL ;
    PORT
      LAYER M5 ;
        RECT  104.688 25.836 104.712 25.92 ;
    END
  END q[228]
  PIN q[229]
    DIRECTION OUTPUT ;
    USE SIGNAL ;
    PORT
      LAYER M5 ;
        RECT  104.976 25.836 105 25.92 ;
    END
  END q[229]
  PIN q[22]
    DIRECTION OUTPUT ;
    USE SIGNAL ;
    PORT
      LAYER M5 ;
        RECT  45.36 25.836 45.384 25.92 ;
    END
  END q[22]
  PIN q[230]
    DIRECTION OUTPUT ;
    USE SIGNAL ;
    PORT
      LAYER M5 ;
        RECT  105.264 25.836 105.288 25.92 ;
    END
  END q[230]
  PIN q[231]
    DIRECTION OUTPUT ;
    USE SIGNAL ;
    PORT
      LAYER M5 ;
        RECT  105.552 25.836 105.576 25.92 ;
    END
  END q[231]
  PIN q[232]
    DIRECTION OUTPUT ;
    USE SIGNAL ;
    PORT
      LAYER M5 ;
        RECT  105.84 25.836 105.864 25.92 ;
    END
  END q[232]
  PIN q[233]
    DIRECTION OUTPUT ;
    USE SIGNAL ;
    PORT
      LAYER M5 ;
        RECT  106.128 25.836 106.152 25.92 ;
    END
  END q[233]
  PIN q[234]
    DIRECTION OUTPUT ;
    USE SIGNAL ;
    PORT
      LAYER M5 ;
        RECT  106.416 25.836 106.44 25.92 ;
    END
  END q[234]
  PIN q[235]
    DIRECTION OUTPUT ;
    USE SIGNAL ;
    PORT
      LAYER M5 ;
        RECT  106.704 25.836 106.728 25.92 ;
    END
  END q[235]
  PIN q[236]
    DIRECTION OUTPUT ;
    USE SIGNAL ;
    PORT
      LAYER M5 ;
        RECT  106.992 25.836 107.016 25.92 ;
    END
  END q[236]
  PIN q[237]
    DIRECTION OUTPUT ;
    USE SIGNAL ;
    PORT
      LAYER M5 ;
        RECT  107.28 25.836 107.304 25.92 ;
    END
  END q[237]
  PIN q[238]
    DIRECTION OUTPUT ;
    USE SIGNAL ;
    PORT
      LAYER M5 ;
        RECT  107.568 25.836 107.592 25.92 ;
    END
  END q[238]
  PIN q[239]
    DIRECTION OUTPUT ;
    USE SIGNAL ;
    PORT
      LAYER M5 ;
        RECT  107.856 25.836 107.88 25.92 ;
    END
  END q[239]
  PIN q[23]
    DIRECTION OUTPUT ;
    USE SIGNAL ;
    PORT
      LAYER M5 ;
        RECT  45.648 25.836 45.672 25.92 ;
    END
  END q[23]
  PIN q[240]
    DIRECTION OUTPUT ;
    USE SIGNAL ;
    PORT
      LAYER M5 ;
        RECT  108.144 25.836 108.168 25.92 ;
    END
  END q[240]
  PIN q[241]
    DIRECTION OUTPUT ;
    USE SIGNAL ;
    PORT
      LAYER M5 ;
        RECT  108.432 25.836 108.456 25.92 ;
    END
  END q[241]
  PIN q[242]
    DIRECTION OUTPUT ;
    USE SIGNAL ;
    PORT
      LAYER M5 ;
        RECT  108.72 25.836 108.744 25.92 ;
    END
  END q[242]
  PIN q[243]
    DIRECTION OUTPUT ;
    USE SIGNAL ;
    PORT
      LAYER M5 ;
        RECT  109.008 25.836 109.032 25.92 ;
    END
  END q[243]
  PIN q[244]
    DIRECTION OUTPUT ;
    USE SIGNAL ;
    PORT
      LAYER M5 ;
        RECT  109.296 25.836 109.32 25.92 ;
    END
  END q[244]
  PIN q[245]
    DIRECTION OUTPUT ;
    USE SIGNAL ;
    PORT
      LAYER M5 ;
        RECT  109.584 25.836 109.608 25.92 ;
    END
  END q[245]
  PIN q[246]
    DIRECTION OUTPUT ;
    USE SIGNAL ;
    PORT
      LAYER M5 ;
        RECT  109.872 25.836 109.896 25.92 ;
    END
  END q[246]
  PIN q[247]
    DIRECTION OUTPUT ;
    USE SIGNAL ;
    PORT
      LAYER M5 ;
        RECT  110.16 25.836 110.184 25.92 ;
    END
  END q[247]
  PIN q[248]
    DIRECTION OUTPUT ;
    USE SIGNAL ;
    PORT
      LAYER M5 ;
        RECT  110.448 25.836 110.472 25.92 ;
    END
  END q[248]
  PIN q[249]
    DIRECTION OUTPUT ;
    USE SIGNAL ;
    PORT
      LAYER M5 ;
        RECT  110.736 25.836 110.76 25.92 ;
    END
  END q[249]
  PIN q[24]
    DIRECTION OUTPUT ;
    USE SIGNAL ;
    PORT
      LAYER M5 ;
        RECT  45.936 25.836 45.96 25.92 ;
    END
  END q[24]
  PIN q[250]
    DIRECTION OUTPUT ;
    USE SIGNAL ;
    PORT
      LAYER M5 ;
        RECT  111.024 25.836 111.048 25.92 ;
    END
  END q[250]
  PIN q[251]
    DIRECTION OUTPUT ;
    USE SIGNAL ;
    PORT
      LAYER M5 ;
        RECT  111.312 25.836 111.336 25.92 ;
    END
  END q[251]
  PIN q[252]
    DIRECTION OUTPUT ;
    USE SIGNAL ;
    PORT
      LAYER M5 ;
        RECT  111.6 25.836 111.624 25.92 ;
    END
  END q[252]
  PIN q[253]
    DIRECTION OUTPUT ;
    USE SIGNAL ;
    PORT
      LAYER M5 ;
        RECT  111.888 25.836 111.912 25.92 ;
    END
  END q[253]
  PIN q[254]
    DIRECTION OUTPUT ;
    USE SIGNAL ;
    PORT
      LAYER M5 ;
        RECT  112.176 25.836 112.2 25.92 ;
    END
  END q[254]
  PIN q[255]
    DIRECTION OUTPUT ;
    USE SIGNAL ;
    PORT
      LAYER M5 ;
        RECT  112.464 25.836 112.488 25.92 ;
    END
  END q[255]
  PIN q[256]
    DIRECTION OUTPUT ;
    USE SIGNAL ;
    PORT
      LAYER M5 ;
        RECT  112.752 25.836 112.776 25.92 ;
    END
  END q[256]
  PIN q[257]
    DIRECTION OUTPUT ;
    USE SIGNAL ;
    PORT
      LAYER M5 ;
        RECT  115.92 25.836 115.944 25.92 ;
    END
  END q[257]
  PIN q[258]
    DIRECTION OUTPUT ;
    USE SIGNAL ;
    PORT
      LAYER M5 ;
        RECT  116.208 25.836 116.232 25.92 ;
    END
  END q[258]
  PIN q[259]
    DIRECTION OUTPUT ;
    USE SIGNAL ;
    PORT
      LAYER M5 ;
        RECT  116.496 25.836 116.52 25.92 ;
    END
  END q[259]
  PIN q[25]
    DIRECTION OUTPUT ;
    USE SIGNAL ;
    PORT
      LAYER M5 ;
        RECT  46.224 25.836 46.248 25.92 ;
    END
  END q[25]
  PIN q[260]
    DIRECTION OUTPUT ;
    USE SIGNAL ;
    PORT
      LAYER M5 ;
        RECT  116.784 25.836 116.808 25.92 ;
    END
  END q[260]
  PIN q[261]
    DIRECTION OUTPUT ;
    USE SIGNAL ;
    PORT
      LAYER M5 ;
        RECT  117.072 25.836 117.096 25.92 ;
    END
  END q[261]
  PIN q[262]
    DIRECTION OUTPUT ;
    USE SIGNAL ;
    PORT
      LAYER M5 ;
        RECT  117.36 25.836 117.384 25.92 ;
    END
  END q[262]
  PIN q[263]
    DIRECTION OUTPUT ;
    USE SIGNAL ;
    PORT
      LAYER M5 ;
        RECT  117.648 25.836 117.672 25.92 ;
    END
  END q[263]
  PIN q[264]
    DIRECTION OUTPUT ;
    USE SIGNAL ;
    PORT
      LAYER M5 ;
        RECT  117.936 25.836 117.96 25.92 ;
    END
  END q[264]
  PIN q[265]
    DIRECTION OUTPUT ;
    USE SIGNAL ;
    PORT
      LAYER M5 ;
        RECT  118.224 25.836 118.248 25.92 ;
    END
  END q[265]
  PIN q[266]
    DIRECTION OUTPUT ;
    USE SIGNAL ;
    PORT
      LAYER M5 ;
        RECT  118.512 25.836 118.536 25.92 ;
    END
  END q[266]
  PIN q[267]
    DIRECTION OUTPUT ;
    USE SIGNAL ;
    PORT
      LAYER M5 ;
        RECT  118.8 25.836 118.824 25.92 ;
    END
  END q[267]
  PIN q[268]
    DIRECTION OUTPUT ;
    USE SIGNAL ;
    PORT
      LAYER M5 ;
        RECT  119.088 25.836 119.112 25.92 ;
    END
  END q[268]
  PIN q[269]
    DIRECTION OUTPUT ;
    USE SIGNAL ;
    PORT
      LAYER M5 ;
        RECT  119.376 25.836 119.4 25.92 ;
    END
  END q[269]
  PIN q[26]
    DIRECTION OUTPUT ;
    USE SIGNAL ;
    PORT
      LAYER M5 ;
        RECT  46.512 25.836 46.536 25.92 ;
    END
  END q[26]
  PIN q[270]
    DIRECTION OUTPUT ;
    USE SIGNAL ;
    PORT
      LAYER M5 ;
        RECT  119.664 25.836 119.688 25.92 ;
    END
  END q[270]
  PIN q[271]
    DIRECTION OUTPUT ;
    USE SIGNAL ;
    PORT
      LAYER M5 ;
        RECT  119.952 25.836 119.976 25.92 ;
    END
  END q[271]
  PIN q[272]
    DIRECTION OUTPUT ;
    USE SIGNAL ;
    PORT
      LAYER M5 ;
        RECT  120.24 25.836 120.264 25.92 ;
    END
  END q[272]
  PIN q[273]
    DIRECTION OUTPUT ;
    USE SIGNAL ;
    PORT
      LAYER M5 ;
        RECT  120.528 25.836 120.552 25.92 ;
    END
  END q[273]
  PIN q[274]
    DIRECTION OUTPUT ;
    USE SIGNAL ;
    PORT
      LAYER M5 ;
        RECT  120.816 25.836 120.84 25.92 ;
    END
  END q[274]
  PIN q[275]
    DIRECTION OUTPUT ;
    USE SIGNAL ;
    PORT
      LAYER M5 ;
        RECT  121.104 25.836 121.128 25.92 ;
    END
  END q[275]
  PIN q[276]
    DIRECTION OUTPUT ;
    USE SIGNAL ;
    PORT
      LAYER M5 ;
        RECT  121.392 25.836 121.416 25.92 ;
    END
  END q[276]
  PIN q[277]
    DIRECTION OUTPUT ;
    USE SIGNAL ;
    PORT
      LAYER M5 ;
        RECT  121.68 25.836 121.704 25.92 ;
    END
  END q[277]
  PIN q[278]
    DIRECTION OUTPUT ;
    USE SIGNAL ;
    PORT
      LAYER M5 ;
        RECT  121.968 25.836 121.992 25.92 ;
    END
  END q[278]
  PIN q[279]
    DIRECTION OUTPUT ;
    USE SIGNAL ;
    PORT
      LAYER M5 ;
        RECT  122.256 25.836 122.28 25.92 ;
    END
  END q[279]
  PIN q[27]
    DIRECTION OUTPUT ;
    USE SIGNAL ;
    PORT
      LAYER M5 ;
        RECT  46.8 25.836 46.824 25.92 ;
    END
  END q[27]
  PIN q[280]
    DIRECTION OUTPUT ;
    USE SIGNAL ;
    PORT
      LAYER M5 ;
        RECT  122.544 25.836 122.568 25.92 ;
    END
  END q[280]
  PIN q[281]
    DIRECTION OUTPUT ;
    USE SIGNAL ;
    PORT
      LAYER M5 ;
        RECT  122.832 25.836 122.856 25.92 ;
    END
  END q[281]
  PIN q[282]
    DIRECTION OUTPUT ;
    USE SIGNAL ;
    PORT
      LAYER M5 ;
        RECT  123.12 25.836 123.144 25.92 ;
    END
  END q[282]
  PIN q[283]
    DIRECTION OUTPUT ;
    USE SIGNAL ;
    PORT
      LAYER M5 ;
        RECT  123.408 25.836 123.432 25.92 ;
    END
  END q[283]
  PIN q[284]
    DIRECTION OUTPUT ;
    USE SIGNAL ;
    PORT
      LAYER M5 ;
        RECT  123.696 25.836 123.72 25.92 ;
    END
  END q[284]
  PIN q[285]
    DIRECTION OUTPUT ;
    USE SIGNAL ;
    PORT
      LAYER M5 ;
        RECT  123.984 25.836 124.008 25.92 ;
    END
  END q[285]
  PIN q[286]
    DIRECTION OUTPUT ;
    USE SIGNAL ;
    PORT
      LAYER M5 ;
        RECT  124.272 25.836 124.296 25.92 ;
    END
  END q[286]
  PIN q[287]
    DIRECTION OUTPUT ;
    USE SIGNAL ;
    PORT
      LAYER M5 ;
        RECT  124.56 25.836 124.584 25.92 ;
    END
  END q[287]
  PIN q[288]
    DIRECTION OUTPUT ;
    USE SIGNAL ;
    PORT
      LAYER M5 ;
        RECT  124.848 25.836 124.872 25.92 ;
    END
  END q[288]
  PIN q[289]
    DIRECTION OUTPUT ;
    USE SIGNAL ;
    PORT
      LAYER M5 ;
        RECT  125.136 25.836 125.16 25.92 ;
    END
  END q[289]
  PIN q[28]
    DIRECTION OUTPUT ;
    USE SIGNAL ;
    PORT
      LAYER M5 ;
        RECT  47.088 25.836 47.112 25.92 ;
    END
  END q[28]
  PIN q[290]
    DIRECTION OUTPUT ;
    USE SIGNAL ;
    PORT
      LAYER M5 ;
        RECT  125.424 25.836 125.448 25.92 ;
    END
  END q[290]
  PIN q[291]
    DIRECTION OUTPUT ;
    USE SIGNAL ;
    PORT
      LAYER M5 ;
        RECT  125.712 25.836 125.736 25.92 ;
    END
  END q[291]
  PIN q[292]
    DIRECTION OUTPUT ;
    USE SIGNAL ;
    PORT
      LAYER M5 ;
        RECT  126 25.836 126.024 25.92 ;
    END
  END q[292]
  PIN q[293]
    DIRECTION OUTPUT ;
    USE SIGNAL ;
    PORT
      LAYER M5 ;
        RECT  126.288 25.836 126.312 25.92 ;
    END
  END q[293]
  PIN q[294]
    DIRECTION OUTPUT ;
    USE SIGNAL ;
    PORT
      LAYER M5 ;
        RECT  126.576 25.836 126.6 25.92 ;
    END
  END q[294]
  PIN q[295]
    DIRECTION OUTPUT ;
    USE SIGNAL ;
    PORT
      LAYER M5 ;
        RECT  126.864 25.836 126.888 25.92 ;
    END
  END q[295]
  PIN q[296]
    DIRECTION OUTPUT ;
    USE SIGNAL ;
    PORT
      LAYER M5 ;
        RECT  127.152 25.836 127.176 25.92 ;
    END
  END q[296]
  PIN q[297]
    DIRECTION OUTPUT ;
    USE SIGNAL ;
    PORT
      LAYER M5 ;
        RECT  127.44 25.836 127.464 25.92 ;
    END
  END q[297]
  PIN q[298]
    DIRECTION OUTPUT ;
    USE SIGNAL ;
    PORT
      LAYER M5 ;
        RECT  127.728 25.836 127.752 25.92 ;
    END
  END q[298]
  PIN q[299]
    DIRECTION OUTPUT ;
    USE SIGNAL ;
    PORT
      LAYER M5 ;
        RECT  128.016 25.836 128.04 25.92 ;
    END
  END q[299]
  PIN q[29]
    DIRECTION OUTPUT ;
    USE SIGNAL ;
    PORT
      LAYER M5 ;
        RECT  47.376 25.836 47.4 25.92 ;
    END
  END q[29]
  PIN q[2]
    DIRECTION OUTPUT ;
    USE SIGNAL ;
    PORT
      LAYER M5 ;
        RECT  39.6 25.836 39.624 25.92 ;
    END
  END q[2]
  PIN q[300]
    DIRECTION OUTPUT ;
    USE SIGNAL ;
    PORT
      LAYER M5 ;
        RECT  128.304 25.836 128.328 25.92 ;
    END
  END q[300]
  PIN q[301]
    DIRECTION OUTPUT ;
    USE SIGNAL ;
    PORT
      LAYER M5 ;
        RECT  128.592 25.836 128.616 25.92 ;
    END
  END q[301]
  PIN q[302]
    DIRECTION OUTPUT ;
    USE SIGNAL ;
    PORT
      LAYER M5 ;
        RECT  128.88 25.836 128.904 25.92 ;
    END
  END q[302]
  PIN q[303]
    DIRECTION OUTPUT ;
    USE SIGNAL ;
    PORT
      LAYER M5 ;
        RECT  129.168 25.836 129.192 25.92 ;
    END
  END q[303]
  PIN q[304]
    DIRECTION OUTPUT ;
    USE SIGNAL ;
    PORT
      LAYER M5 ;
        RECT  129.456 25.836 129.48 25.92 ;
    END
  END q[304]
  PIN q[305]
    DIRECTION OUTPUT ;
    USE SIGNAL ;
    PORT
      LAYER M5 ;
        RECT  129.744 25.836 129.768 25.92 ;
    END
  END q[305]
  PIN q[306]
    DIRECTION OUTPUT ;
    USE SIGNAL ;
    PORT
      LAYER M5 ;
        RECT  130.032 25.836 130.056 25.92 ;
    END
  END q[306]
  PIN q[307]
    DIRECTION OUTPUT ;
    USE SIGNAL ;
    PORT
      LAYER M5 ;
        RECT  130.32 25.836 130.344 25.92 ;
    END
  END q[307]
  PIN q[308]
    DIRECTION OUTPUT ;
    USE SIGNAL ;
    PORT
      LAYER M5 ;
        RECT  130.608 25.836 130.632 25.92 ;
    END
  END q[308]
  PIN q[309]
    DIRECTION OUTPUT ;
    USE SIGNAL ;
    PORT
      LAYER M5 ;
        RECT  130.896 25.836 130.92 25.92 ;
    END
  END q[309]
  PIN q[30]
    DIRECTION OUTPUT ;
    USE SIGNAL ;
    PORT
      LAYER M5 ;
        RECT  47.664 25.836 47.688 25.92 ;
    END
  END q[30]
  PIN q[310]
    DIRECTION OUTPUT ;
    USE SIGNAL ;
    PORT
      LAYER M5 ;
        RECT  131.184 25.836 131.208 25.92 ;
    END
  END q[310]
  PIN q[311]
    DIRECTION OUTPUT ;
    USE SIGNAL ;
    PORT
      LAYER M5 ;
        RECT  131.472 25.836 131.496 25.92 ;
    END
  END q[311]
  PIN q[312]
    DIRECTION OUTPUT ;
    USE SIGNAL ;
    PORT
      LAYER M5 ;
        RECT  131.76 25.836 131.784 25.92 ;
    END
  END q[312]
  PIN q[313]
    DIRECTION OUTPUT ;
    USE SIGNAL ;
    PORT
      LAYER M5 ;
        RECT  132.048 25.836 132.072 25.92 ;
    END
  END q[313]
  PIN q[314]
    DIRECTION OUTPUT ;
    USE SIGNAL ;
    PORT
      LAYER M5 ;
        RECT  132.336 25.836 132.36 25.92 ;
    END
  END q[314]
  PIN q[315]
    DIRECTION OUTPUT ;
    USE SIGNAL ;
    PORT
      LAYER M5 ;
        RECT  132.624 25.836 132.648 25.92 ;
    END
  END q[315]
  PIN q[316]
    DIRECTION OUTPUT ;
    USE SIGNAL ;
    PORT
      LAYER M5 ;
        RECT  132.912 25.836 132.936 25.92 ;
    END
  END q[316]
  PIN q[317]
    DIRECTION OUTPUT ;
    USE SIGNAL ;
    PORT
      LAYER M5 ;
        RECT  133.2 25.836 133.224 25.92 ;
    END
  END q[317]
  PIN q[318]
    DIRECTION OUTPUT ;
    USE SIGNAL ;
    PORT
      LAYER M5 ;
        RECT  133.488 25.836 133.512 25.92 ;
    END
  END q[318]
  PIN q[319]
    DIRECTION OUTPUT ;
    USE SIGNAL ;
    PORT
      LAYER M5 ;
        RECT  133.776 25.836 133.8 25.92 ;
    END
  END q[319]
  PIN q[31]
    DIRECTION OUTPUT ;
    USE SIGNAL ;
    PORT
      LAYER M5 ;
        RECT  47.952 25.836 47.976 25.92 ;
    END
  END q[31]
  PIN q[320]
    DIRECTION OUTPUT ;
    USE SIGNAL ;
    PORT
      LAYER M5 ;
        RECT  134.064 25.836 134.088 25.92 ;
    END
  END q[320]
  PIN q[321]
    DIRECTION OUTPUT ;
    USE SIGNAL ;
    PORT
      LAYER M5 ;
        RECT  134.352 25.836 134.376 25.92 ;
    END
  END q[321]
  PIN q[322]
    DIRECTION OUTPUT ;
    USE SIGNAL ;
    PORT
      LAYER M5 ;
        RECT  134.64 25.836 134.664 25.92 ;
    END
  END q[322]
  PIN q[323]
    DIRECTION OUTPUT ;
    USE SIGNAL ;
    PORT
      LAYER M5 ;
        RECT  134.928 25.836 134.952 25.92 ;
    END
  END q[323]
  PIN q[324]
    DIRECTION OUTPUT ;
    USE SIGNAL ;
    PORT
      LAYER M5 ;
        RECT  135.216 25.836 135.24 25.92 ;
    END
  END q[324]
  PIN q[325]
    DIRECTION OUTPUT ;
    USE SIGNAL ;
    PORT
      LAYER M5 ;
        RECT  135.504 25.836 135.528 25.92 ;
    END
  END q[325]
  PIN q[326]
    DIRECTION OUTPUT ;
    USE SIGNAL ;
    PORT
      LAYER M5 ;
        RECT  135.792 25.836 135.816 25.92 ;
    END
  END q[326]
  PIN q[327]
    DIRECTION OUTPUT ;
    USE SIGNAL ;
    PORT
      LAYER M5 ;
        RECT  136.08 25.836 136.104 25.92 ;
    END
  END q[327]
  PIN q[328]
    DIRECTION OUTPUT ;
    USE SIGNAL ;
    PORT
      LAYER M5 ;
        RECT  136.368 25.836 136.392 25.92 ;
    END
  END q[328]
  PIN q[329]
    DIRECTION OUTPUT ;
    USE SIGNAL ;
    PORT
      LAYER M5 ;
        RECT  136.656 25.836 136.68 25.92 ;
    END
  END q[329]
  PIN q[32]
    DIRECTION OUTPUT ;
    USE SIGNAL ;
    PORT
      LAYER M5 ;
        RECT  48.24 25.836 48.264 25.92 ;
    END
  END q[32]
  PIN q[330]
    DIRECTION OUTPUT ;
    USE SIGNAL ;
    PORT
      LAYER M5 ;
        RECT  136.944 25.836 136.968 25.92 ;
    END
  END q[330]
  PIN q[331]
    DIRECTION OUTPUT ;
    USE SIGNAL ;
    PORT
      LAYER M5 ;
        RECT  137.232 25.836 137.256 25.92 ;
    END
  END q[331]
  PIN q[332]
    DIRECTION OUTPUT ;
    USE SIGNAL ;
    PORT
      LAYER M5 ;
        RECT  137.52 25.836 137.544 25.92 ;
    END
  END q[332]
  PIN q[333]
    DIRECTION OUTPUT ;
    USE SIGNAL ;
    PORT
      LAYER M5 ;
        RECT  137.808 25.836 137.832 25.92 ;
    END
  END q[333]
  PIN q[334]
    DIRECTION OUTPUT ;
    USE SIGNAL ;
    PORT
      LAYER M5 ;
        RECT  138.096 25.836 138.12 25.92 ;
    END
  END q[334]
  PIN q[335]
    DIRECTION OUTPUT ;
    USE SIGNAL ;
    PORT
      LAYER M5 ;
        RECT  138.384 25.836 138.408 25.92 ;
    END
  END q[335]
  PIN q[336]
    DIRECTION OUTPUT ;
    USE SIGNAL ;
    PORT
      LAYER M5 ;
        RECT  138.672 25.836 138.696 25.92 ;
    END
  END q[336]
  PIN q[337]
    DIRECTION OUTPUT ;
    USE SIGNAL ;
    PORT
      LAYER M5 ;
        RECT  138.96 25.836 138.984 25.92 ;
    END
  END q[337]
  PIN q[338]
    DIRECTION OUTPUT ;
    USE SIGNAL ;
    PORT
      LAYER M5 ;
        RECT  139.248 25.836 139.272 25.92 ;
    END
  END q[338]
  PIN q[339]
    DIRECTION OUTPUT ;
    USE SIGNAL ;
    PORT
      LAYER M5 ;
        RECT  139.536 25.836 139.56 25.92 ;
    END
  END q[339]
  PIN q[33]
    DIRECTION OUTPUT ;
    USE SIGNAL ;
    PORT
      LAYER M5 ;
        RECT  48.528 25.836 48.552 25.92 ;
    END
  END q[33]
  PIN q[340]
    DIRECTION OUTPUT ;
    USE SIGNAL ;
    PORT
      LAYER M5 ;
        RECT  139.824 25.836 139.848 25.92 ;
    END
  END q[340]
  PIN q[341]
    DIRECTION OUTPUT ;
    USE SIGNAL ;
    PORT
      LAYER M5 ;
        RECT  140.112 25.836 140.136 25.92 ;
    END
  END q[341]
  PIN q[342]
    DIRECTION OUTPUT ;
    USE SIGNAL ;
    PORT
      LAYER M5 ;
        RECT  140.4 25.836 140.424 25.92 ;
    END
  END q[342]
  PIN q[343]
    DIRECTION OUTPUT ;
    USE SIGNAL ;
    PORT
      LAYER M5 ;
        RECT  140.688 25.836 140.712 25.92 ;
    END
  END q[343]
  PIN q[344]
    DIRECTION OUTPUT ;
    USE SIGNAL ;
    PORT
      LAYER M5 ;
        RECT  140.976 25.836 141 25.92 ;
    END
  END q[344]
  PIN q[345]
    DIRECTION OUTPUT ;
    USE SIGNAL ;
    PORT
      LAYER M5 ;
        RECT  141.264 25.836 141.288 25.92 ;
    END
  END q[345]
  PIN q[346]
    DIRECTION OUTPUT ;
    USE SIGNAL ;
    PORT
      LAYER M5 ;
        RECT  141.552 25.836 141.576 25.92 ;
    END
  END q[346]
  PIN q[347]
    DIRECTION OUTPUT ;
    USE SIGNAL ;
    PORT
      LAYER M5 ;
        RECT  141.84 25.836 141.864 25.92 ;
    END
  END q[347]
  PIN q[348]
    DIRECTION OUTPUT ;
    USE SIGNAL ;
    PORT
      LAYER M5 ;
        RECT  142.128 25.836 142.152 25.92 ;
    END
  END q[348]
  PIN q[349]
    DIRECTION OUTPUT ;
    USE SIGNAL ;
    PORT
      LAYER M5 ;
        RECT  142.416 25.836 142.44 25.92 ;
    END
  END q[349]
  PIN q[34]
    DIRECTION OUTPUT ;
    USE SIGNAL ;
    PORT
      LAYER M5 ;
        RECT  48.816 25.836 48.84 25.92 ;
    END
  END q[34]
  PIN q[350]
    DIRECTION OUTPUT ;
    USE SIGNAL ;
    PORT
      LAYER M5 ;
        RECT  142.704 25.836 142.728 25.92 ;
    END
  END q[350]
  PIN q[351]
    DIRECTION OUTPUT ;
    USE SIGNAL ;
    PORT
      LAYER M5 ;
        RECT  142.992 25.836 143.016 25.92 ;
    END
  END q[351]
  PIN q[352]
    DIRECTION OUTPUT ;
    USE SIGNAL ;
    PORT
      LAYER M5 ;
        RECT  143.28 25.836 143.304 25.92 ;
    END
  END q[352]
  PIN q[353]
    DIRECTION OUTPUT ;
    USE SIGNAL ;
    PORT
      LAYER M5 ;
        RECT  143.568 25.836 143.592 25.92 ;
    END
  END q[353]
  PIN q[354]
    DIRECTION OUTPUT ;
    USE SIGNAL ;
    PORT
      LAYER M5 ;
        RECT  143.856 25.836 143.88 25.92 ;
    END
  END q[354]
  PIN q[355]
    DIRECTION OUTPUT ;
    USE SIGNAL ;
    PORT
      LAYER M5 ;
        RECT  144.144 25.836 144.168 25.92 ;
    END
  END q[355]
  PIN q[356]
    DIRECTION OUTPUT ;
    USE SIGNAL ;
    PORT
      LAYER M5 ;
        RECT  144.432 25.836 144.456 25.92 ;
    END
  END q[356]
  PIN q[357]
    DIRECTION OUTPUT ;
    USE SIGNAL ;
    PORT
      LAYER M5 ;
        RECT  144.72 25.836 144.744 25.92 ;
    END
  END q[357]
  PIN q[358]
    DIRECTION OUTPUT ;
    USE SIGNAL ;
    PORT
      LAYER M5 ;
        RECT  145.008 25.836 145.032 25.92 ;
    END
  END q[358]
  PIN q[359]
    DIRECTION OUTPUT ;
    USE SIGNAL ;
    PORT
      LAYER M5 ;
        RECT  145.296 25.836 145.32 25.92 ;
    END
  END q[359]
  PIN q[35]
    DIRECTION OUTPUT ;
    USE SIGNAL ;
    PORT
      LAYER M5 ;
        RECT  49.104 25.836 49.128 25.92 ;
    END
  END q[35]
  PIN q[360]
    DIRECTION OUTPUT ;
    USE SIGNAL ;
    PORT
      LAYER M5 ;
        RECT  145.584 25.836 145.608 25.92 ;
    END
  END q[360]
  PIN q[361]
    DIRECTION OUTPUT ;
    USE SIGNAL ;
    PORT
      LAYER M5 ;
        RECT  145.872 25.836 145.896 25.92 ;
    END
  END q[361]
  PIN q[362]
    DIRECTION OUTPUT ;
    USE SIGNAL ;
    PORT
      LAYER M5 ;
        RECT  146.16 25.836 146.184 25.92 ;
    END
  END q[362]
  PIN q[363]
    DIRECTION OUTPUT ;
    USE SIGNAL ;
    PORT
      LAYER M5 ;
        RECT  146.448 25.836 146.472 25.92 ;
    END
  END q[363]
  PIN q[364]
    DIRECTION OUTPUT ;
    USE SIGNAL ;
    PORT
      LAYER M5 ;
        RECT  146.736 25.836 146.76 25.92 ;
    END
  END q[364]
  PIN q[365]
    DIRECTION OUTPUT ;
    USE SIGNAL ;
    PORT
      LAYER M5 ;
        RECT  147.024 25.836 147.048 25.92 ;
    END
  END q[365]
  PIN q[366]
    DIRECTION OUTPUT ;
    USE SIGNAL ;
    PORT
      LAYER M5 ;
        RECT  147.312 25.836 147.336 25.92 ;
    END
  END q[366]
  PIN q[367]
    DIRECTION OUTPUT ;
    USE SIGNAL ;
    PORT
      LAYER M5 ;
        RECT  147.6 25.836 147.624 25.92 ;
    END
  END q[367]
  PIN q[368]
    DIRECTION OUTPUT ;
    USE SIGNAL ;
    PORT
      LAYER M5 ;
        RECT  147.888 25.836 147.912 25.92 ;
    END
  END q[368]
  PIN q[369]
    DIRECTION OUTPUT ;
    USE SIGNAL ;
    PORT
      LAYER M5 ;
        RECT  148.176 25.836 148.2 25.92 ;
    END
  END q[369]
  PIN q[36]
    DIRECTION OUTPUT ;
    USE SIGNAL ;
    PORT
      LAYER M5 ;
        RECT  49.392 25.836 49.416 25.92 ;
    END
  END q[36]
  PIN q[370]
    DIRECTION OUTPUT ;
    USE SIGNAL ;
    PORT
      LAYER M5 ;
        RECT  148.464 25.836 148.488 25.92 ;
    END
  END q[370]
  PIN q[371]
    DIRECTION OUTPUT ;
    USE SIGNAL ;
    PORT
      LAYER M5 ;
        RECT  148.752 25.836 148.776 25.92 ;
    END
  END q[371]
  PIN q[372]
    DIRECTION OUTPUT ;
    USE SIGNAL ;
    PORT
      LAYER M5 ;
        RECT  149.04 25.836 149.064 25.92 ;
    END
  END q[372]
  PIN q[373]
    DIRECTION OUTPUT ;
    USE SIGNAL ;
    PORT
      LAYER M5 ;
        RECT  149.328 25.836 149.352 25.92 ;
    END
  END q[373]
  PIN q[374]
    DIRECTION OUTPUT ;
    USE SIGNAL ;
    PORT
      LAYER M5 ;
        RECT  149.616 25.836 149.64 25.92 ;
    END
  END q[374]
  PIN q[375]
    DIRECTION OUTPUT ;
    USE SIGNAL ;
    PORT
      LAYER M5 ;
        RECT  149.904 25.836 149.928 25.92 ;
    END
  END q[375]
  PIN q[376]
    DIRECTION OUTPUT ;
    USE SIGNAL ;
    PORT
      LAYER M5 ;
        RECT  150.192 25.836 150.216 25.92 ;
    END
  END q[376]
  PIN q[377]
    DIRECTION OUTPUT ;
    USE SIGNAL ;
    PORT
      LAYER M5 ;
        RECT  150.48 25.836 150.504 25.92 ;
    END
  END q[377]
  PIN q[378]
    DIRECTION OUTPUT ;
    USE SIGNAL ;
    PORT
      LAYER M5 ;
        RECT  150.768 25.836 150.792 25.92 ;
    END
  END q[378]
  PIN q[379]
    DIRECTION OUTPUT ;
    USE SIGNAL ;
    PORT
      LAYER M5 ;
        RECT  151.056 25.836 151.08 25.92 ;
    END
  END q[379]
  PIN q[37]
    DIRECTION OUTPUT ;
    USE SIGNAL ;
    PORT
      LAYER M5 ;
        RECT  49.68 25.836 49.704 25.92 ;
    END
  END q[37]
  PIN q[380]
    DIRECTION OUTPUT ;
    USE SIGNAL ;
    PORT
      LAYER M5 ;
        RECT  151.344 25.836 151.368 25.92 ;
    END
  END q[380]
  PIN q[381]
    DIRECTION OUTPUT ;
    USE SIGNAL ;
    PORT
      LAYER M5 ;
        RECT  151.632 25.836 151.656 25.92 ;
    END
  END q[381]
  PIN q[382]
    DIRECTION OUTPUT ;
    USE SIGNAL ;
    PORT
      LAYER M5 ;
        RECT  151.92 25.836 151.944 25.92 ;
    END
  END q[382]
  PIN q[383]
    DIRECTION OUTPUT ;
    USE SIGNAL ;
    PORT
      LAYER M5 ;
        RECT  152.208 25.836 152.232 25.92 ;
    END
  END q[383]
  PIN q[384]
    DIRECTION OUTPUT ;
    USE SIGNAL ;
    PORT
      LAYER M5 ;
        RECT  152.496 25.836 152.52 25.92 ;
    END
  END q[384]
  PIN q[385]
    DIRECTION OUTPUT ;
    USE SIGNAL ;
    PORT
      LAYER M5 ;
        RECT  152.784 25.836 152.808 25.92 ;
    END
  END q[385]
  PIN q[386]
    DIRECTION OUTPUT ;
    USE SIGNAL ;
    PORT
      LAYER M5 ;
        RECT  153.072 25.836 153.096 25.92 ;
    END
  END q[386]
  PIN q[387]
    DIRECTION OUTPUT ;
    USE SIGNAL ;
    PORT
      LAYER M5 ;
        RECT  153.36 25.836 153.384 25.92 ;
    END
  END q[387]
  PIN q[388]
    DIRECTION OUTPUT ;
    USE SIGNAL ;
    PORT
      LAYER M5 ;
        RECT  153.648 25.836 153.672 25.92 ;
    END
  END q[388]
  PIN q[389]
    DIRECTION OUTPUT ;
    USE SIGNAL ;
    PORT
      LAYER M5 ;
        RECT  153.936 25.836 153.96 25.92 ;
    END
  END q[389]
  PIN q[38]
    DIRECTION OUTPUT ;
    USE SIGNAL ;
    PORT
      LAYER M5 ;
        RECT  49.968 25.836 49.992 25.92 ;
    END
  END q[38]
  PIN q[390]
    DIRECTION OUTPUT ;
    USE SIGNAL ;
    PORT
      LAYER M5 ;
        RECT  154.224 25.836 154.248 25.92 ;
    END
  END q[390]
  PIN q[391]
    DIRECTION OUTPUT ;
    USE SIGNAL ;
    PORT
      LAYER M5 ;
        RECT  154.512 25.836 154.536 25.92 ;
    END
  END q[391]
  PIN q[392]
    DIRECTION OUTPUT ;
    USE SIGNAL ;
    PORT
      LAYER M5 ;
        RECT  154.8 25.836 154.824 25.92 ;
    END
  END q[392]
  PIN q[393]
    DIRECTION OUTPUT ;
    USE SIGNAL ;
    PORT
      LAYER M5 ;
        RECT  155.088 25.836 155.112 25.92 ;
    END
  END q[393]
  PIN q[394]
    DIRECTION OUTPUT ;
    USE SIGNAL ;
    PORT
      LAYER M5 ;
        RECT  155.376 25.836 155.4 25.92 ;
    END
  END q[394]
  PIN q[395]
    DIRECTION OUTPUT ;
    USE SIGNAL ;
    PORT
      LAYER M5 ;
        RECT  155.664 25.836 155.688 25.92 ;
    END
  END q[395]
  PIN q[396]
    DIRECTION OUTPUT ;
    USE SIGNAL ;
    PORT
      LAYER M5 ;
        RECT  155.952 25.836 155.976 25.92 ;
    END
  END q[396]
  PIN q[397]
    DIRECTION OUTPUT ;
    USE SIGNAL ;
    PORT
      LAYER M5 ;
        RECT  156.24 25.836 156.264 25.92 ;
    END
  END q[397]
  PIN q[398]
    DIRECTION OUTPUT ;
    USE SIGNAL ;
    PORT
      LAYER M5 ;
        RECT  156.528 25.836 156.552 25.92 ;
    END
  END q[398]
  PIN q[399]
    DIRECTION OUTPUT ;
    USE SIGNAL ;
    PORT
      LAYER M5 ;
        RECT  156.816 25.836 156.84 25.92 ;
    END
  END q[399]
  PIN q[39]
    DIRECTION OUTPUT ;
    USE SIGNAL ;
    PORT
      LAYER M5 ;
        RECT  50.256 25.836 50.28 25.92 ;
    END
  END q[39]
  PIN q[3]
    DIRECTION OUTPUT ;
    USE SIGNAL ;
    PORT
      LAYER M5 ;
        RECT  39.888 25.836 39.912 25.92 ;
    END
  END q[3]
  PIN q[400]
    DIRECTION OUTPUT ;
    USE SIGNAL ;
    PORT
      LAYER M5 ;
        RECT  157.104 25.836 157.128 25.92 ;
    END
  END q[400]
  PIN q[401]
    DIRECTION OUTPUT ;
    USE SIGNAL ;
    PORT
      LAYER M5 ;
        RECT  157.392 25.836 157.416 25.92 ;
    END
  END q[401]
  PIN q[402]
    DIRECTION OUTPUT ;
    USE SIGNAL ;
    PORT
      LAYER M5 ;
        RECT  157.68 25.836 157.704 25.92 ;
    END
  END q[402]
  PIN q[403]
    DIRECTION OUTPUT ;
    USE SIGNAL ;
    PORT
      LAYER M5 ;
        RECT  157.968 25.836 157.992 25.92 ;
    END
  END q[403]
  PIN q[404]
    DIRECTION OUTPUT ;
    USE SIGNAL ;
    PORT
      LAYER M5 ;
        RECT  158.256 25.836 158.28 25.92 ;
    END
  END q[404]
  PIN q[405]
    DIRECTION OUTPUT ;
    USE SIGNAL ;
    PORT
      LAYER M5 ;
        RECT  158.544 25.836 158.568 25.92 ;
    END
  END q[405]
  PIN q[406]
    DIRECTION OUTPUT ;
    USE SIGNAL ;
    PORT
      LAYER M5 ;
        RECT  158.832 25.836 158.856 25.92 ;
    END
  END q[406]
  PIN q[407]
    DIRECTION OUTPUT ;
    USE SIGNAL ;
    PORT
      LAYER M5 ;
        RECT  159.12 25.836 159.144 25.92 ;
    END
  END q[407]
  PIN q[408]
    DIRECTION OUTPUT ;
    USE SIGNAL ;
    PORT
      LAYER M5 ;
        RECT  159.408 25.836 159.432 25.92 ;
    END
  END q[408]
  PIN q[409]
    DIRECTION OUTPUT ;
    USE SIGNAL ;
    PORT
      LAYER M5 ;
        RECT  159.696 25.836 159.72 25.92 ;
    END
  END q[409]
  PIN q[40]
    DIRECTION OUTPUT ;
    USE SIGNAL ;
    PORT
      LAYER M5 ;
        RECT  50.544 25.836 50.568 25.92 ;
    END
  END q[40]
  PIN q[410]
    DIRECTION OUTPUT ;
    USE SIGNAL ;
    PORT
      LAYER M5 ;
        RECT  159.984 25.836 160.008 25.92 ;
    END
  END q[410]
  PIN q[411]
    DIRECTION OUTPUT ;
    USE SIGNAL ;
    PORT
      LAYER M5 ;
        RECT  160.272 25.836 160.296 25.92 ;
    END
  END q[411]
  PIN q[412]
    DIRECTION OUTPUT ;
    USE SIGNAL ;
    PORT
      LAYER M5 ;
        RECT  160.56 25.836 160.584 25.92 ;
    END
  END q[412]
  PIN q[413]
    DIRECTION OUTPUT ;
    USE SIGNAL ;
    PORT
      LAYER M5 ;
        RECT  160.848 25.836 160.872 25.92 ;
    END
  END q[413]
  PIN q[414]
    DIRECTION OUTPUT ;
    USE SIGNAL ;
    PORT
      LAYER M5 ;
        RECT  161.136 25.836 161.16 25.92 ;
    END
  END q[414]
  PIN q[415]
    DIRECTION OUTPUT ;
    USE SIGNAL ;
    PORT
      LAYER M5 ;
        RECT  161.424 25.836 161.448 25.92 ;
    END
  END q[415]
  PIN q[416]
    DIRECTION OUTPUT ;
    USE SIGNAL ;
    PORT
      LAYER M5 ;
        RECT  161.712 25.836 161.736 25.92 ;
    END
  END q[416]
  PIN q[417]
    DIRECTION OUTPUT ;
    USE SIGNAL ;
    PORT
      LAYER M5 ;
        RECT  162 25.836 162.024 25.92 ;
    END
  END q[417]
  PIN q[418]
    DIRECTION OUTPUT ;
    USE SIGNAL ;
    PORT
      LAYER M5 ;
        RECT  162.288 25.836 162.312 25.92 ;
    END
  END q[418]
  PIN q[419]
    DIRECTION OUTPUT ;
    USE SIGNAL ;
    PORT
      LAYER M5 ;
        RECT  162.576 25.836 162.6 25.92 ;
    END
  END q[419]
  PIN q[41]
    DIRECTION OUTPUT ;
    USE SIGNAL ;
    PORT
      LAYER M5 ;
        RECT  50.832 25.836 50.856 25.92 ;
    END
  END q[41]
  PIN q[420]
    DIRECTION OUTPUT ;
    USE SIGNAL ;
    PORT
      LAYER M5 ;
        RECT  162.864 25.836 162.888 25.92 ;
    END
  END q[420]
  PIN q[421]
    DIRECTION OUTPUT ;
    USE SIGNAL ;
    PORT
      LAYER M5 ;
        RECT  163.152 25.836 163.176 25.92 ;
    END
  END q[421]
  PIN q[422]
    DIRECTION OUTPUT ;
    USE SIGNAL ;
    PORT
      LAYER M5 ;
        RECT  163.44 25.836 163.464 25.92 ;
    END
  END q[422]
  PIN q[423]
    DIRECTION OUTPUT ;
    USE SIGNAL ;
    PORT
      LAYER M5 ;
        RECT  163.728 25.836 163.752 25.92 ;
    END
  END q[423]
  PIN q[424]
    DIRECTION OUTPUT ;
    USE SIGNAL ;
    PORT
      LAYER M5 ;
        RECT  164.016 25.836 164.04 25.92 ;
    END
  END q[424]
  PIN q[425]
    DIRECTION OUTPUT ;
    USE SIGNAL ;
    PORT
      LAYER M5 ;
        RECT  164.304 25.836 164.328 25.92 ;
    END
  END q[425]
  PIN q[426]
    DIRECTION OUTPUT ;
    USE SIGNAL ;
    PORT
      LAYER M5 ;
        RECT  164.592 25.836 164.616 25.92 ;
    END
  END q[426]
  PIN q[427]
    DIRECTION OUTPUT ;
    USE SIGNAL ;
    PORT
      LAYER M5 ;
        RECT  164.88 25.836 164.904 25.92 ;
    END
  END q[427]
  PIN q[428]
    DIRECTION OUTPUT ;
    USE SIGNAL ;
    PORT
      LAYER M5 ;
        RECT  165.168 25.836 165.192 25.92 ;
    END
  END q[428]
  PIN q[429]
    DIRECTION OUTPUT ;
    USE SIGNAL ;
    PORT
      LAYER M5 ;
        RECT  165.456 25.836 165.48 25.92 ;
    END
  END q[429]
  PIN q[42]
    DIRECTION OUTPUT ;
    USE SIGNAL ;
    PORT
      LAYER M5 ;
        RECT  51.12 25.836 51.144 25.92 ;
    END
  END q[42]
  PIN q[430]
    DIRECTION OUTPUT ;
    USE SIGNAL ;
    PORT
      LAYER M5 ;
        RECT  165.744 25.836 165.768 25.92 ;
    END
  END q[430]
  PIN q[431]
    DIRECTION OUTPUT ;
    USE SIGNAL ;
    PORT
      LAYER M5 ;
        RECT  166.032 25.836 166.056 25.92 ;
    END
  END q[431]
  PIN q[432]
    DIRECTION OUTPUT ;
    USE SIGNAL ;
    PORT
      LAYER M5 ;
        RECT  166.32 25.836 166.344 25.92 ;
    END
  END q[432]
  PIN q[433]
    DIRECTION OUTPUT ;
    USE SIGNAL ;
    PORT
      LAYER M5 ;
        RECT  166.608 25.836 166.632 25.92 ;
    END
  END q[433]
  PIN q[434]
    DIRECTION OUTPUT ;
    USE SIGNAL ;
    PORT
      LAYER M5 ;
        RECT  166.896 25.836 166.92 25.92 ;
    END
  END q[434]
  PIN q[435]
    DIRECTION OUTPUT ;
    USE SIGNAL ;
    PORT
      LAYER M5 ;
        RECT  167.184 25.836 167.208 25.92 ;
    END
  END q[435]
  PIN q[436]
    DIRECTION OUTPUT ;
    USE SIGNAL ;
    PORT
      LAYER M5 ;
        RECT  167.472 25.836 167.496 25.92 ;
    END
  END q[436]
  PIN q[437]
    DIRECTION OUTPUT ;
    USE SIGNAL ;
    PORT
      LAYER M5 ;
        RECT  167.76 25.836 167.784 25.92 ;
    END
  END q[437]
  PIN q[438]
    DIRECTION OUTPUT ;
    USE SIGNAL ;
    PORT
      LAYER M5 ;
        RECT  168.048 25.836 168.072 25.92 ;
    END
  END q[438]
  PIN q[439]
    DIRECTION OUTPUT ;
    USE SIGNAL ;
    PORT
      LAYER M5 ;
        RECT  168.336 25.836 168.36 25.92 ;
    END
  END q[439]
  PIN q[43]
    DIRECTION OUTPUT ;
    USE SIGNAL ;
    PORT
      LAYER M5 ;
        RECT  51.408 25.836 51.432 25.92 ;
    END
  END q[43]
  PIN q[440]
    DIRECTION OUTPUT ;
    USE SIGNAL ;
    PORT
      LAYER M5 ;
        RECT  168.624 25.836 168.648 25.92 ;
    END
  END q[440]
  PIN q[441]
    DIRECTION OUTPUT ;
    USE SIGNAL ;
    PORT
      LAYER M5 ;
        RECT  168.912 25.836 168.936 25.92 ;
    END
  END q[441]
  PIN q[442]
    DIRECTION OUTPUT ;
    USE SIGNAL ;
    PORT
      LAYER M5 ;
        RECT  169.2 25.836 169.224 25.92 ;
    END
  END q[442]
  PIN q[443]
    DIRECTION OUTPUT ;
    USE SIGNAL ;
    PORT
      LAYER M5 ;
        RECT  169.488 25.836 169.512 25.92 ;
    END
  END q[443]
  PIN q[444]
    DIRECTION OUTPUT ;
    USE SIGNAL ;
    PORT
      LAYER M5 ;
        RECT  169.776 25.836 169.8 25.92 ;
    END
  END q[444]
  PIN q[445]
    DIRECTION OUTPUT ;
    USE SIGNAL ;
    PORT
      LAYER M5 ;
        RECT  170.064 25.836 170.088 25.92 ;
    END
  END q[445]
  PIN q[446]
    DIRECTION OUTPUT ;
    USE SIGNAL ;
    PORT
      LAYER M5 ;
        RECT  170.352 25.836 170.376 25.92 ;
    END
  END q[446]
  PIN q[447]
    DIRECTION OUTPUT ;
    USE SIGNAL ;
    PORT
      LAYER M5 ;
        RECT  170.64 25.836 170.664 25.92 ;
    END
  END q[447]
  PIN q[448]
    DIRECTION OUTPUT ;
    USE SIGNAL ;
    PORT
      LAYER M5 ;
        RECT  170.928 25.836 170.952 25.92 ;
    END
  END q[448]
  PIN q[449]
    DIRECTION OUTPUT ;
    USE SIGNAL ;
    PORT
      LAYER M5 ;
        RECT  171.216 25.836 171.24 25.92 ;
    END
  END q[449]
  PIN q[44]
    DIRECTION OUTPUT ;
    USE SIGNAL ;
    PORT
      LAYER M5 ;
        RECT  51.696 25.836 51.72 25.92 ;
    END
  END q[44]
  PIN q[450]
    DIRECTION OUTPUT ;
    USE SIGNAL ;
    PORT
      LAYER M5 ;
        RECT  171.504 25.836 171.528 25.92 ;
    END
  END q[450]
  PIN q[451]
    DIRECTION OUTPUT ;
    USE SIGNAL ;
    PORT
      LAYER M5 ;
        RECT  171.792 25.836 171.816 25.92 ;
    END
  END q[451]
  PIN q[452]
    DIRECTION OUTPUT ;
    USE SIGNAL ;
    PORT
      LAYER M5 ;
        RECT  172.08 25.836 172.104 25.92 ;
    END
  END q[452]
  PIN q[453]
    DIRECTION OUTPUT ;
    USE SIGNAL ;
    PORT
      LAYER M5 ;
        RECT  172.368 25.836 172.392 25.92 ;
    END
  END q[453]
  PIN q[454]
    DIRECTION OUTPUT ;
    USE SIGNAL ;
    PORT
      LAYER M5 ;
        RECT  172.656 25.836 172.68 25.92 ;
    END
  END q[454]
  PIN q[455]
    DIRECTION OUTPUT ;
    USE SIGNAL ;
    PORT
      LAYER M5 ;
        RECT  172.944 25.836 172.968 25.92 ;
    END
  END q[455]
  PIN q[456]
    DIRECTION OUTPUT ;
    USE SIGNAL ;
    PORT
      LAYER M5 ;
        RECT  173.232 25.836 173.256 25.92 ;
    END
  END q[456]
  PIN q[457]
    DIRECTION OUTPUT ;
    USE SIGNAL ;
    PORT
      LAYER M5 ;
        RECT  173.52 25.836 173.544 25.92 ;
    END
  END q[457]
  PIN q[458]
    DIRECTION OUTPUT ;
    USE SIGNAL ;
    PORT
      LAYER M5 ;
        RECT  173.808 25.836 173.832 25.92 ;
    END
  END q[458]
  PIN q[459]
    DIRECTION OUTPUT ;
    USE SIGNAL ;
    PORT
      LAYER M5 ;
        RECT  174.096 25.836 174.12 25.92 ;
    END
  END q[459]
  PIN q[45]
    DIRECTION OUTPUT ;
    USE SIGNAL ;
    PORT
      LAYER M5 ;
        RECT  51.984 25.836 52.008 25.92 ;
    END
  END q[45]
  PIN q[460]
    DIRECTION OUTPUT ;
    USE SIGNAL ;
    PORT
      LAYER M5 ;
        RECT  174.384 25.836 174.408 25.92 ;
    END
  END q[460]
  PIN q[461]
    DIRECTION OUTPUT ;
    USE SIGNAL ;
    PORT
      LAYER M5 ;
        RECT  174.672 25.836 174.696 25.92 ;
    END
  END q[461]
  PIN q[462]
    DIRECTION OUTPUT ;
    USE SIGNAL ;
    PORT
      LAYER M5 ;
        RECT  174.96 25.836 174.984 25.92 ;
    END
  END q[462]
  PIN q[463]
    DIRECTION OUTPUT ;
    USE SIGNAL ;
    PORT
      LAYER M5 ;
        RECT  175.248 25.836 175.272 25.92 ;
    END
  END q[463]
  PIN q[464]
    DIRECTION OUTPUT ;
    USE SIGNAL ;
    PORT
      LAYER M5 ;
        RECT  175.536 25.836 175.56 25.92 ;
    END
  END q[464]
  PIN q[465]
    DIRECTION OUTPUT ;
    USE SIGNAL ;
    PORT
      LAYER M5 ;
        RECT  175.824 25.836 175.848 25.92 ;
    END
  END q[465]
  PIN q[466]
    DIRECTION OUTPUT ;
    USE SIGNAL ;
    PORT
      LAYER M5 ;
        RECT  176.112 25.836 176.136 25.92 ;
    END
  END q[466]
  PIN q[467]
    DIRECTION OUTPUT ;
    USE SIGNAL ;
    PORT
      LAYER M5 ;
        RECT  176.4 25.836 176.424 25.92 ;
    END
  END q[467]
  PIN q[468]
    DIRECTION OUTPUT ;
    USE SIGNAL ;
    PORT
      LAYER M5 ;
        RECT  176.688 25.836 176.712 25.92 ;
    END
  END q[468]
  PIN q[469]
    DIRECTION OUTPUT ;
    USE SIGNAL ;
    PORT
      LAYER M5 ;
        RECT  176.976 25.836 177 25.92 ;
    END
  END q[469]
  PIN q[46]
    DIRECTION OUTPUT ;
    USE SIGNAL ;
    PORT
      LAYER M5 ;
        RECT  52.272 25.836 52.296 25.92 ;
    END
  END q[46]
  PIN q[470]
    DIRECTION OUTPUT ;
    USE SIGNAL ;
    PORT
      LAYER M5 ;
        RECT  177.264 25.836 177.288 25.92 ;
    END
  END q[470]
  PIN q[471]
    DIRECTION OUTPUT ;
    USE SIGNAL ;
    PORT
      LAYER M5 ;
        RECT  177.552 25.836 177.576 25.92 ;
    END
  END q[471]
  PIN q[472]
    DIRECTION OUTPUT ;
    USE SIGNAL ;
    PORT
      LAYER M5 ;
        RECT  177.84 25.836 177.864 25.92 ;
    END
  END q[472]
  PIN q[473]
    DIRECTION OUTPUT ;
    USE SIGNAL ;
    PORT
      LAYER M5 ;
        RECT  178.128 25.836 178.152 25.92 ;
    END
  END q[473]
  PIN q[474]
    DIRECTION OUTPUT ;
    USE SIGNAL ;
    PORT
      LAYER M5 ;
        RECT  178.416 25.836 178.44 25.92 ;
    END
  END q[474]
  PIN q[475]
    DIRECTION OUTPUT ;
    USE SIGNAL ;
    PORT
      LAYER M5 ;
        RECT  178.704 25.836 178.728 25.92 ;
    END
  END q[475]
  PIN q[476]
    DIRECTION OUTPUT ;
    USE SIGNAL ;
    PORT
      LAYER M5 ;
        RECT  178.992 25.836 179.016 25.92 ;
    END
  END q[476]
  PIN q[477]
    DIRECTION OUTPUT ;
    USE SIGNAL ;
    PORT
      LAYER M5 ;
        RECT  179.28 25.836 179.304 25.92 ;
    END
  END q[477]
  PIN q[478]
    DIRECTION OUTPUT ;
    USE SIGNAL ;
    PORT
      LAYER M5 ;
        RECT  179.568 25.836 179.592 25.92 ;
    END
  END q[478]
  PIN q[479]
    DIRECTION OUTPUT ;
    USE SIGNAL ;
    PORT
      LAYER M5 ;
        RECT  179.856 25.836 179.88 25.92 ;
    END
  END q[479]
  PIN q[47]
    DIRECTION OUTPUT ;
    USE SIGNAL ;
    PORT
      LAYER M5 ;
        RECT  52.56 25.836 52.584 25.92 ;
    END
  END q[47]
  PIN q[480]
    DIRECTION OUTPUT ;
    USE SIGNAL ;
    PORT
      LAYER M5 ;
        RECT  180.144 25.836 180.168 25.92 ;
    END
  END q[480]
  PIN q[481]
    DIRECTION OUTPUT ;
    USE SIGNAL ;
    PORT
      LAYER M5 ;
        RECT  180.432 25.836 180.456 25.92 ;
    END
  END q[481]
  PIN q[482]
    DIRECTION OUTPUT ;
    USE SIGNAL ;
    PORT
      LAYER M5 ;
        RECT  180.72 25.836 180.744 25.92 ;
    END
  END q[482]
  PIN q[483]
    DIRECTION OUTPUT ;
    USE SIGNAL ;
    PORT
      LAYER M5 ;
        RECT  181.008 25.836 181.032 25.92 ;
    END
  END q[483]
  PIN q[484]
    DIRECTION OUTPUT ;
    USE SIGNAL ;
    PORT
      LAYER M5 ;
        RECT  181.296 25.836 181.32 25.92 ;
    END
  END q[484]
  PIN q[485]
    DIRECTION OUTPUT ;
    USE SIGNAL ;
    PORT
      LAYER M5 ;
        RECT  181.584 25.836 181.608 25.92 ;
    END
  END q[485]
  PIN q[486]
    DIRECTION OUTPUT ;
    USE SIGNAL ;
    PORT
      LAYER M5 ;
        RECT  181.872 25.836 181.896 25.92 ;
    END
  END q[486]
  PIN q[487]
    DIRECTION OUTPUT ;
    USE SIGNAL ;
    PORT
      LAYER M5 ;
        RECT  182.16 25.836 182.184 25.92 ;
    END
  END q[487]
  PIN q[488]
    DIRECTION OUTPUT ;
    USE SIGNAL ;
    PORT
      LAYER M5 ;
        RECT  182.448 25.836 182.472 25.92 ;
    END
  END q[488]
  PIN q[489]
    DIRECTION OUTPUT ;
    USE SIGNAL ;
    PORT
      LAYER M5 ;
        RECT  182.736 25.836 182.76 25.92 ;
    END
  END q[489]
  PIN q[48]
    DIRECTION OUTPUT ;
    USE SIGNAL ;
    PORT
      LAYER M5 ;
        RECT  52.848 25.836 52.872 25.92 ;
    END
  END q[48]
  PIN q[490]
    DIRECTION OUTPUT ;
    USE SIGNAL ;
    PORT
      LAYER M5 ;
        RECT  183.024 25.836 183.048 25.92 ;
    END
  END q[490]
  PIN q[491]
    DIRECTION OUTPUT ;
    USE SIGNAL ;
    PORT
      LAYER M5 ;
        RECT  183.312 25.836 183.336 25.92 ;
    END
  END q[491]
  PIN q[492]
    DIRECTION OUTPUT ;
    USE SIGNAL ;
    PORT
      LAYER M5 ;
        RECT  183.6 25.836 183.624 25.92 ;
    END
  END q[492]
  PIN q[493]
    DIRECTION OUTPUT ;
    USE SIGNAL ;
    PORT
      LAYER M5 ;
        RECT  183.888 25.836 183.912 25.92 ;
    END
  END q[493]
  PIN q[494]
    DIRECTION OUTPUT ;
    USE SIGNAL ;
    PORT
      LAYER M5 ;
        RECT  184.176 25.836 184.2 25.92 ;
    END
  END q[494]
  PIN q[495]
    DIRECTION OUTPUT ;
    USE SIGNAL ;
    PORT
      LAYER M5 ;
        RECT  184.464 25.836 184.488 25.92 ;
    END
  END q[495]
  PIN q[496]
    DIRECTION OUTPUT ;
    USE SIGNAL ;
    PORT
      LAYER M5 ;
        RECT  184.752 25.836 184.776 25.92 ;
    END
  END q[496]
  PIN q[497]
    DIRECTION OUTPUT ;
    USE SIGNAL ;
    PORT
      LAYER M5 ;
        RECT  185.04 25.836 185.064 25.92 ;
    END
  END q[497]
  PIN q[498]
    DIRECTION OUTPUT ;
    USE SIGNAL ;
    PORT
      LAYER M5 ;
        RECT  185.328 25.836 185.352 25.92 ;
    END
  END q[498]
  PIN q[499]
    DIRECTION OUTPUT ;
    USE SIGNAL ;
    PORT
      LAYER M5 ;
        RECT  185.616 25.836 185.64 25.92 ;
    END
  END q[499]
  PIN q[49]
    DIRECTION OUTPUT ;
    USE SIGNAL ;
    PORT
      LAYER M5 ;
        RECT  53.136 25.836 53.16 25.92 ;
    END
  END q[49]
  PIN q[4]
    DIRECTION OUTPUT ;
    USE SIGNAL ;
    PORT
      LAYER M5 ;
        RECT  40.176 25.836 40.2 25.92 ;
    END
  END q[4]
  PIN q[500]
    DIRECTION OUTPUT ;
    USE SIGNAL ;
    PORT
      LAYER M5 ;
        RECT  185.904 25.836 185.928 25.92 ;
    END
  END q[500]
  PIN q[501]
    DIRECTION OUTPUT ;
    USE SIGNAL ;
    PORT
      LAYER M5 ;
        RECT  186.192 25.836 186.216 25.92 ;
    END
  END q[501]
  PIN q[502]
    DIRECTION OUTPUT ;
    USE SIGNAL ;
    PORT
      LAYER M5 ;
        RECT  186.48 25.836 186.504 25.92 ;
    END
  END q[502]
  PIN q[503]
    DIRECTION OUTPUT ;
    USE SIGNAL ;
    PORT
      LAYER M5 ;
        RECT  186.768 25.836 186.792 25.92 ;
    END
  END q[503]
  PIN q[504]
    DIRECTION OUTPUT ;
    USE SIGNAL ;
    PORT
      LAYER M5 ;
        RECT  187.056 25.836 187.08 25.92 ;
    END
  END q[504]
  PIN q[505]
    DIRECTION OUTPUT ;
    USE SIGNAL ;
    PORT
      LAYER M5 ;
        RECT  187.344 25.836 187.368 25.92 ;
    END
  END q[505]
  PIN q[506]
    DIRECTION OUTPUT ;
    USE SIGNAL ;
    PORT
      LAYER M5 ;
        RECT  187.632 25.836 187.656 25.92 ;
    END
  END q[506]
  PIN q[507]
    DIRECTION OUTPUT ;
    USE SIGNAL ;
    PORT
      LAYER M5 ;
        RECT  187.92 25.836 187.944 25.92 ;
    END
  END q[507]
  PIN q[508]
    DIRECTION OUTPUT ;
    USE SIGNAL ;
    PORT
      LAYER M5 ;
        RECT  188.208 25.836 188.232 25.92 ;
    END
  END q[508]
  PIN q[509]
    DIRECTION OUTPUT ;
    USE SIGNAL ;
    PORT
      LAYER M5 ;
        RECT  188.496 25.836 188.52 25.92 ;
    END
  END q[509]
  PIN q[50]
    DIRECTION OUTPUT ;
    USE SIGNAL ;
    PORT
      LAYER M5 ;
        RECT  53.424 25.836 53.448 25.92 ;
    END
  END q[50]
  PIN q[510]
    DIRECTION OUTPUT ;
    USE SIGNAL ;
    PORT
      LAYER M5 ;
        RECT  188.784 25.836 188.808 25.92 ;
    END
  END q[510]
  PIN q[511]
    DIRECTION OUTPUT ;
    USE SIGNAL ;
    PORT
      LAYER M5 ;
        RECT  189.072 25.836 189.096 25.92 ;
    END
  END q[511]
  PIN q[512]
    DIRECTION OUTPUT ;
    USE SIGNAL ;
    PORT
      LAYER M5 ;
        RECT  189.36 25.836 189.384 25.92 ;
    END
  END q[512]
  PIN q[513]
    DIRECTION OUTPUT ;
    USE SIGNAL ;
    PORT
      LAYER M5 ;
        RECT  189.648 25.836 189.672 25.92 ;
    END
  END q[513]
  PIN q[514]
    DIRECTION OUTPUT ;
    USE SIGNAL ;
    PORT
      LAYER M5 ;
        RECT  189.936 25.836 189.96 25.92 ;
    END
  END q[514]
  PIN q[51]
    DIRECTION OUTPUT ;
    USE SIGNAL ;
    PORT
      LAYER M5 ;
        RECT  53.712 25.836 53.736 25.92 ;
    END
  END q[51]
  PIN q[52]
    DIRECTION OUTPUT ;
    USE SIGNAL ;
    PORT
      LAYER M5 ;
        RECT  54 25.836 54.024 25.92 ;
    END
  END q[52]
  PIN q[53]
    DIRECTION OUTPUT ;
    USE SIGNAL ;
    PORT
      LAYER M5 ;
        RECT  54.288 25.836 54.312 25.92 ;
    END
  END q[53]
  PIN q[54]
    DIRECTION OUTPUT ;
    USE SIGNAL ;
    PORT
      LAYER M5 ;
        RECT  54.576 25.836 54.6 25.92 ;
    END
  END q[54]
  PIN q[55]
    DIRECTION OUTPUT ;
    USE SIGNAL ;
    PORT
      LAYER M5 ;
        RECT  54.864 25.836 54.888 25.92 ;
    END
  END q[55]
  PIN q[56]
    DIRECTION OUTPUT ;
    USE SIGNAL ;
    PORT
      LAYER M5 ;
        RECT  55.152 25.836 55.176 25.92 ;
    END
  END q[56]
  PIN q[57]
    DIRECTION OUTPUT ;
    USE SIGNAL ;
    PORT
      LAYER M5 ;
        RECT  55.44 25.836 55.464 25.92 ;
    END
  END q[57]
  PIN q[58]
    DIRECTION OUTPUT ;
    USE SIGNAL ;
    PORT
      LAYER M5 ;
        RECT  55.728 25.836 55.752 25.92 ;
    END
  END q[58]
  PIN q[59]
    DIRECTION OUTPUT ;
    USE SIGNAL ;
    PORT
      LAYER M5 ;
        RECT  56.016 25.836 56.04 25.92 ;
    END
  END q[59]
  PIN q[5]
    DIRECTION OUTPUT ;
    USE SIGNAL ;
    PORT
      LAYER M5 ;
        RECT  40.464 25.836 40.488 25.92 ;
    END
  END q[5]
  PIN q[60]
    DIRECTION OUTPUT ;
    USE SIGNAL ;
    PORT
      LAYER M5 ;
        RECT  56.304 25.836 56.328 25.92 ;
    END
  END q[60]
  PIN q[61]
    DIRECTION OUTPUT ;
    USE SIGNAL ;
    PORT
      LAYER M5 ;
        RECT  56.592 25.836 56.616 25.92 ;
    END
  END q[61]
  PIN q[62]
    DIRECTION OUTPUT ;
    USE SIGNAL ;
    PORT
      LAYER M5 ;
        RECT  56.88 25.836 56.904 25.92 ;
    END
  END q[62]
  PIN q[63]
    DIRECTION OUTPUT ;
    USE SIGNAL ;
    PORT
      LAYER M5 ;
        RECT  57.168 25.836 57.192 25.92 ;
    END
  END q[63]
  PIN q[64]
    DIRECTION OUTPUT ;
    USE SIGNAL ;
    PORT
      LAYER M5 ;
        RECT  57.456 25.836 57.48 25.92 ;
    END
  END q[64]
  PIN q[65]
    DIRECTION OUTPUT ;
    USE SIGNAL ;
    PORT
      LAYER M5 ;
        RECT  57.744 25.836 57.768 25.92 ;
    END
  END q[65]
  PIN q[66]
    DIRECTION OUTPUT ;
    USE SIGNAL ;
    PORT
      LAYER M5 ;
        RECT  58.032 25.836 58.056 25.92 ;
    END
  END q[66]
  PIN q[67]
    DIRECTION OUTPUT ;
    USE SIGNAL ;
    PORT
      LAYER M5 ;
        RECT  58.32 25.836 58.344 25.92 ;
    END
  END q[67]
  PIN q[68]
    DIRECTION OUTPUT ;
    USE SIGNAL ;
    PORT
      LAYER M5 ;
        RECT  58.608 25.836 58.632 25.92 ;
    END
  END q[68]
  PIN q[69]
    DIRECTION OUTPUT ;
    USE SIGNAL ;
    PORT
      LAYER M5 ;
        RECT  58.896 25.836 58.92 25.92 ;
    END
  END q[69]
  PIN q[6]
    DIRECTION OUTPUT ;
    USE SIGNAL ;
    PORT
      LAYER M5 ;
        RECT  40.752 25.836 40.776 25.92 ;
    END
  END q[6]
  PIN q[70]
    DIRECTION OUTPUT ;
    USE SIGNAL ;
    PORT
      LAYER M5 ;
        RECT  59.184 25.836 59.208 25.92 ;
    END
  END q[70]
  PIN q[71]
    DIRECTION OUTPUT ;
    USE SIGNAL ;
    PORT
      LAYER M5 ;
        RECT  59.472 25.836 59.496 25.92 ;
    END
  END q[71]
  PIN q[72]
    DIRECTION OUTPUT ;
    USE SIGNAL ;
    PORT
      LAYER M5 ;
        RECT  59.76 25.836 59.784 25.92 ;
    END
  END q[72]
  PIN q[73]
    DIRECTION OUTPUT ;
    USE SIGNAL ;
    PORT
      LAYER M5 ;
        RECT  60.048 25.836 60.072 25.92 ;
    END
  END q[73]
  PIN q[74]
    DIRECTION OUTPUT ;
    USE SIGNAL ;
    PORT
      LAYER M5 ;
        RECT  60.336 25.836 60.36 25.92 ;
    END
  END q[74]
  PIN q[75]
    DIRECTION OUTPUT ;
    USE SIGNAL ;
    PORT
      LAYER M5 ;
        RECT  60.624 25.836 60.648 25.92 ;
    END
  END q[75]
  PIN q[76]
    DIRECTION OUTPUT ;
    USE SIGNAL ;
    PORT
      LAYER M5 ;
        RECT  60.912 25.836 60.936 25.92 ;
    END
  END q[76]
  PIN q[77]
    DIRECTION OUTPUT ;
    USE SIGNAL ;
    PORT
      LAYER M5 ;
        RECT  61.2 25.836 61.224 25.92 ;
    END
  END q[77]
  PIN q[78]
    DIRECTION OUTPUT ;
    USE SIGNAL ;
    PORT
      LAYER M5 ;
        RECT  61.488 25.836 61.512 25.92 ;
    END
  END q[78]
  PIN q[79]
    DIRECTION OUTPUT ;
    USE SIGNAL ;
    PORT
      LAYER M5 ;
        RECT  61.776 25.836 61.8 25.92 ;
    END
  END q[79]
  PIN q[7]
    DIRECTION OUTPUT ;
    USE SIGNAL ;
    PORT
      LAYER M5 ;
        RECT  41.04 25.836 41.064 25.92 ;
    END
  END q[7]
  PIN q[80]
    DIRECTION OUTPUT ;
    USE SIGNAL ;
    PORT
      LAYER M5 ;
        RECT  62.064 25.836 62.088 25.92 ;
    END
  END q[80]
  PIN q[81]
    DIRECTION OUTPUT ;
    USE SIGNAL ;
    PORT
      LAYER M5 ;
        RECT  62.352 25.836 62.376 25.92 ;
    END
  END q[81]
  PIN q[82]
    DIRECTION OUTPUT ;
    USE SIGNAL ;
    PORT
      LAYER M5 ;
        RECT  62.64 25.836 62.664 25.92 ;
    END
  END q[82]
  PIN q[83]
    DIRECTION OUTPUT ;
    USE SIGNAL ;
    PORT
      LAYER M5 ;
        RECT  62.928 25.836 62.952 25.92 ;
    END
  END q[83]
  PIN q[84]
    DIRECTION OUTPUT ;
    USE SIGNAL ;
    PORT
      LAYER M5 ;
        RECT  63.216 25.836 63.24 25.92 ;
    END
  END q[84]
  PIN q[85]
    DIRECTION OUTPUT ;
    USE SIGNAL ;
    PORT
      LAYER M5 ;
        RECT  63.504 25.836 63.528 25.92 ;
    END
  END q[85]
  PIN q[86]
    DIRECTION OUTPUT ;
    USE SIGNAL ;
    PORT
      LAYER M5 ;
        RECT  63.792 25.836 63.816 25.92 ;
    END
  END q[86]
  PIN q[87]
    DIRECTION OUTPUT ;
    USE SIGNAL ;
    PORT
      LAYER M5 ;
        RECT  64.08 25.836 64.104 25.92 ;
    END
  END q[87]
  PIN q[88]
    DIRECTION OUTPUT ;
    USE SIGNAL ;
    PORT
      LAYER M5 ;
        RECT  64.368 25.836 64.392 25.92 ;
    END
  END q[88]
  PIN q[89]
    DIRECTION OUTPUT ;
    USE SIGNAL ;
    PORT
      LAYER M5 ;
        RECT  64.656 25.836 64.68 25.92 ;
    END
  END q[89]
  PIN q[8]
    DIRECTION OUTPUT ;
    USE SIGNAL ;
    PORT
      LAYER M5 ;
        RECT  41.328 25.836 41.352 25.92 ;
    END
  END q[8]
  PIN q[90]
    DIRECTION OUTPUT ;
    USE SIGNAL ;
    PORT
      LAYER M5 ;
        RECT  64.944 25.836 64.968 25.92 ;
    END
  END q[90]
  PIN q[91]
    DIRECTION OUTPUT ;
    USE SIGNAL ;
    PORT
      LAYER M5 ;
        RECT  65.232 25.836 65.256 25.92 ;
    END
  END q[91]
  PIN q[92]
    DIRECTION OUTPUT ;
    USE SIGNAL ;
    PORT
      LAYER M5 ;
        RECT  65.52 25.836 65.544 25.92 ;
    END
  END q[92]
  PIN q[93]
    DIRECTION OUTPUT ;
    USE SIGNAL ;
    PORT
      LAYER M5 ;
        RECT  65.808 25.836 65.832 25.92 ;
    END
  END q[93]
  PIN q[94]
    DIRECTION OUTPUT ;
    USE SIGNAL ;
    PORT
      LAYER M5 ;
        RECT  66.096 25.836 66.12 25.92 ;
    END
  END q[94]
  PIN q[95]
    DIRECTION OUTPUT ;
    USE SIGNAL ;
    PORT
      LAYER M5 ;
        RECT  66.384 25.836 66.408 25.92 ;
    END
  END q[95]
  PIN q[96]
    DIRECTION OUTPUT ;
    USE SIGNAL ;
    PORT
      LAYER M5 ;
        RECT  66.672 25.836 66.696 25.92 ;
    END
  END q[96]
  PIN q[97]
    DIRECTION OUTPUT ;
    USE SIGNAL ;
    PORT
      LAYER M5 ;
        RECT  66.96 25.836 66.984 25.92 ;
    END
  END q[97]
  PIN q[98]
    DIRECTION OUTPUT ;
    USE SIGNAL ;
    PORT
      LAYER M5 ;
        RECT  67.248 25.836 67.272 25.92 ;
    END
  END q[98]
  PIN q[99]
    DIRECTION OUTPUT ;
    USE SIGNAL ;
    PORT
      LAYER M5 ;
        RECT  67.536 25.836 67.56 25.92 ;
    END
  END q[99]
  PIN q[9]
    DIRECTION OUTPUT ;
    USE SIGNAL ;
    PORT
      LAYER M5 ;
        RECT  41.616 25.836 41.64 25.92 ;
    END
  END q[9]
  PIN ready
    DIRECTION OUTPUT ;
    USE SIGNAL ;
    PORT
      LAYER M5 ;
        RECT  113.616 25.836 113.64 25.92 ;
    END
  END ready
  PIN rst_n
    DIRECTION INPUT ;
    USE SIGNAL ;
    PORT
      LAYER M5 ;
        RECT  113.328 25.836 113.352 25.92 ;
    END
  END rst_n
  PIN strap_k[0]
    DIRECTION INPUT ;
    USE SIGNAL ;
    PORT
      LAYER M5 ;
        RECT  114.192 25.836 114.216 25.92 ;
    END
  END strap_k[0]
  PIN strap_k[1]
    DIRECTION INPUT ;
    USE SIGNAL ;
    PORT
      LAYER M5 ;
        RECT  114.48 25.836 114.504 25.92 ;
    END
  END strap_k[1]
  PIN strap_k[2]
    DIRECTION INPUT ;
    USE SIGNAL ;
    PORT
      LAYER M5 ;
        RECT  114.768 25.836 114.792 25.92 ;
    END
  END strap_k[2]
  PIN strap_k[3]
    DIRECTION INPUT ;
    USE SIGNAL ;
    PORT
      LAYER M5 ;
        RECT  115.056 25.836 115.08 25.92 ;
    END
  END strap_k[3]
  PIN strap_k[4]
    DIRECTION INPUT ;
    USE SIGNAL ;
    PORT
      LAYER M5 ;
        RECT  115.344 25.836 115.368 25.92 ;
    END
  END strap_k[4]
  PIN strap_k[5]
    DIRECTION INPUT ;
    USE SIGNAL ;
    PORT
      LAYER M5 ;
        RECT  115.632 25.836 115.656 25.92 ;
    END
  END strap_k[5]
  PIN t_rst_n
    DIRECTION INPUT ;
    USE SIGNAL ;
    PORT
      LAYER M5 ;
        RECT  114.48 0 114.504 0.084 ;
    END
  END t_rst_n
  PIN VDD
    DIRECTION INOUT ;
    USE POWER ;
    PORT
      LAYER M5 ;
        RECT  222.516 4.311 222.636 21.609 ;
        RECT  218.196 4.311 218.316 21.609 ;
        RECT  213.876 4.311 213.996 21.609 ;
        RECT  209.556 4.311 209.676 21.609 ;
        RECT  205.236 4.311 205.356 21.609 ;
        RECT  200.916 4.311 201.036 21.609 ;
        RECT  196.596 4.311 196.716 21.609 ;
        RECT  192.276 4.311 192.396 21.609 ;
        RECT  187.956 4.311 188.076 21.609 ;
        RECT  183.636 4.311 183.756 21.609 ;
        RECT  179.316 4.311 179.436 21.609 ;
        RECT  174.996 4.311 175.116 21.609 ;
        RECT  170.676 4.311 170.796 21.609 ;
        RECT  166.356 4.311 166.476 21.609 ;
        RECT  162.036 4.311 162.156 21.609 ;
        RECT  157.716 4.311 157.836 21.609 ;
        RECT  153.396 4.311 153.516 21.609 ;
        RECT  149.076 4.311 149.196 21.609 ;
        RECT  144.756 4.311 144.876 21.609 ;
        RECT  140.436 4.311 140.556 21.609 ;
        RECT  136.116 4.311 136.236 21.609 ;
        RECT  131.796 4.311 131.916 21.609 ;
        RECT  127.476 4.311 127.596 21.609 ;
        RECT  123.156 4.311 123.276 21.609 ;
        RECT  118.836 4.311 118.956 21.609 ;
        RECT  114.516 4.311 114.636 21.609 ;
        RECT  110.196 4.311 110.316 21.609 ;
        RECT  105.876 4.311 105.996 21.609 ;
        RECT  101.556 4.311 101.676 21.609 ;
        RECT  97.236 4.311 97.356 21.609 ;
        RECT  92.916 4.311 93.036 21.609 ;
        RECT  88.596 4.311 88.716 21.609 ;
        RECT  84.276 4.311 84.396 21.609 ;
        RECT  79.956 4.311 80.076 21.609 ;
        RECT  75.636 4.311 75.756 21.609 ;
        RECT  71.316 4.311 71.436 21.609 ;
        RECT  66.996 4.311 67.116 21.609 ;
        RECT  62.676 4.311 62.796 21.609 ;
        RECT  58.356 4.311 58.476 21.609 ;
        RECT  54.036 4.311 54.156 21.609 ;
        RECT  49.716 4.311 49.836 21.609 ;
        RECT  45.396 4.311 45.516 21.609 ;
        RECT  41.076 4.311 41.196 21.609 ;
        RECT  36.756 4.311 36.876 21.609 ;
        RECT  32.436 4.311 32.556 21.609 ;
        RECT  28.116 4.311 28.236 21.609 ;
        RECT  23.796 4.311 23.916 21.609 ;
        RECT  19.476 4.311 19.596 21.609 ;
        RECT  15.156 4.311 15.276 21.609 ;
        RECT  10.836 4.311 10.956 21.609 ;
        RECT  6.516 4.311 6.636 21.609 ;
    END
  END VDD
  PIN VSS
    DIRECTION INOUT ;
    USE GROUND ;
    PORT
      LAYER M5 ;
        RECT  222.324 4.297 222.444 21.623 ;
        RECT  218.004 4.297 218.124 21.623 ;
        RECT  213.684 4.297 213.804 21.623 ;
        RECT  209.364 4.297 209.484 21.623 ;
        RECT  205.044 4.297 205.164 21.623 ;
        RECT  200.724 4.297 200.844 21.623 ;
        RECT  196.404 4.297 196.524 21.623 ;
        RECT  192.084 4.297 192.204 21.623 ;
        RECT  187.764 4.297 187.884 21.623 ;
        RECT  183.444 4.297 183.564 21.623 ;
        RECT  179.124 4.297 179.244 21.623 ;
        RECT  174.804 4.297 174.924 21.623 ;
        RECT  170.484 4.297 170.604 21.623 ;
        RECT  166.164 4.297 166.284 21.623 ;
        RECT  161.844 4.297 161.964 21.623 ;
        RECT  157.524 4.297 157.644 21.623 ;
        RECT  153.204 4.297 153.324 21.623 ;
        RECT  148.884 4.297 149.004 21.623 ;
        RECT  144.564 4.297 144.684 21.623 ;
        RECT  140.244 4.297 140.364 21.623 ;
        RECT  135.924 4.297 136.044 21.623 ;
        RECT  131.604 4.297 131.724 21.623 ;
        RECT  127.284 4.297 127.404 21.623 ;
        RECT  122.964 4.297 123.084 21.623 ;
        RECT  118.644 4.297 118.764 21.623 ;
        RECT  114.324 4.297 114.444 21.623 ;
        RECT  110.004 4.297 110.124 21.623 ;
        RECT  105.684 4.297 105.804 21.623 ;
        RECT  101.364 4.297 101.484 21.623 ;
        RECT  97.044 4.297 97.164 21.623 ;
        RECT  92.724 4.297 92.844 21.623 ;
        RECT  88.404 4.297 88.524 21.623 ;
        RECT  84.084 4.297 84.204 21.623 ;
        RECT  79.764 4.297 79.884 21.623 ;
        RECT  75.444 4.297 75.564 21.623 ;
        RECT  71.124 4.297 71.244 21.623 ;
        RECT  66.804 4.297 66.924 21.623 ;
        RECT  62.484 4.297 62.604 21.623 ;
        RECT  58.164 4.297 58.284 21.623 ;
        RECT  53.844 4.297 53.964 21.623 ;
        RECT  49.524 4.297 49.644 21.623 ;
        RECT  45.204 4.297 45.324 21.623 ;
        RECT  40.884 4.297 41.004 21.623 ;
        RECT  36.564 4.297 36.684 21.623 ;
        RECT  32.244 4.297 32.364 21.623 ;
        RECT  27.924 4.297 28.044 21.623 ;
        RECT  23.604 4.297 23.724 21.623 ;
        RECT  19.284 4.297 19.404 21.623 ;
        RECT  14.964 4.297 15.084 21.623 ;
        RECT  10.644 4.297 10.764 21.623 ;
        RECT  6.324 4.297 6.444 21.623 ;
    END
  END VSS
  OBS
    LAYER RVTN ;
     RECT  4.32 0 224.64 25.92 ;
    LAYER RVTP ;
     RECT  4.32 0 224.64 25.92 ;
    LAYER M1 ;
     RECT  4.32 0 224.64 25.92 ;
    LAYER M2 ;
     RECT  4.32 0 224.64 25.92 ;
    LAYER M3 ;
     RECT  4.32 0 224.64 25.92 ;
    LAYER M4 ;
     RECT  4.32 0 224.64 25.92 ;
    LAYER M5 ;
     RECT  4.32 0 224.64 25.92 ;
  END
END sle_cland_w515_s_201
END LIBRARY
